VERSION 5.8 ;
BUSBITCHARS "[]" ;
DIVIDERCHAR "/" ;
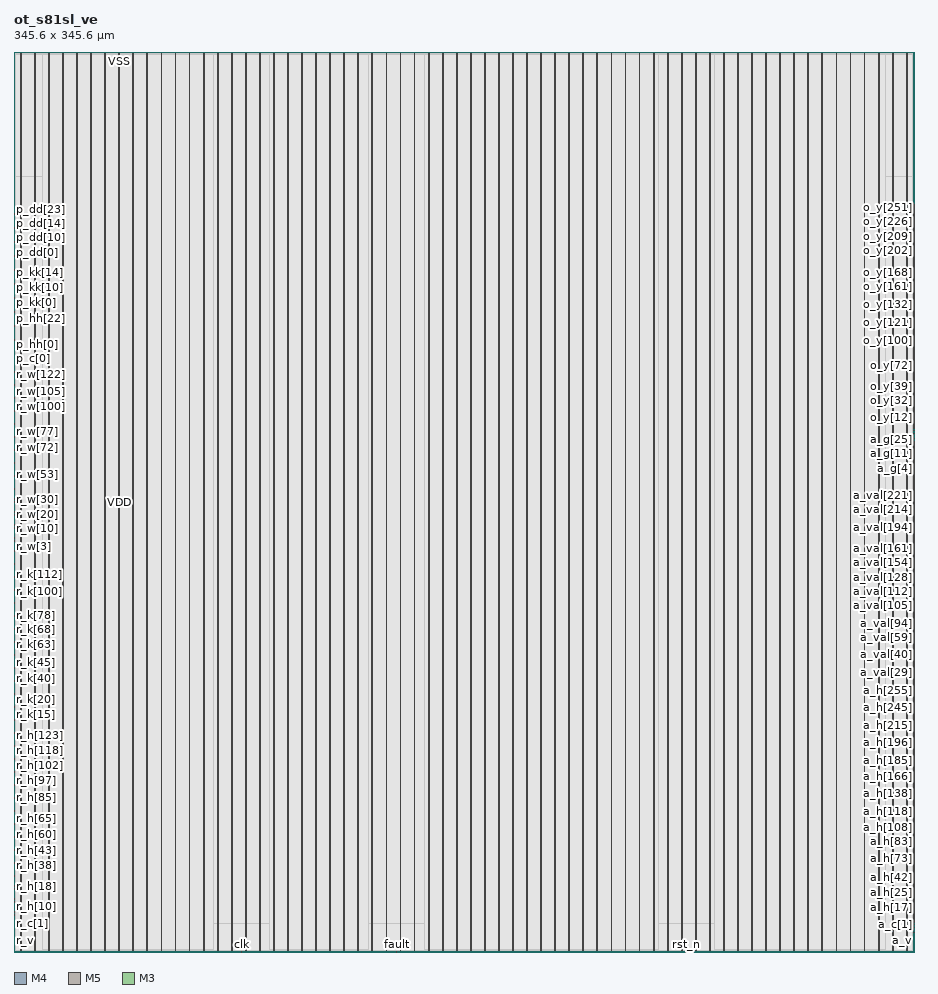
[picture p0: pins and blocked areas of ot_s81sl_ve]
MACRO ot_s81sl_ve
  CLASS BLOCK ;
  ORIGIN 0 0 ;
  FOREIGN ot_s81sl_ve 0 0 ;
  SIZE 345.6 BY 345.6 ;
  SYMMETRY X Y ;
  PIN r_v
    DIRECTION INPUT ;
    USE SIGNAL ;
    PORT
      LAYER M4 ;
        RECT 0.000 7.632 0.192 7.656 ;
    END
  END r_v
  PIN r_c[0]
    DIRECTION INPUT ;
    USE SIGNAL ;
    PORT
      LAYER M4 ;
        RECT 0.000 9.552 0.192 9.576 ;
    END
  END r_c[0]
  PIN r_c[1]
    DIRECTION INPUT ;
    USE SIGNAL ;
    PORT
      LAYER M4 ;
        RECT 0.000 10.992 0.192 11.016 ;
    END
  END r_c[1]
  PIN r_h[0]
    DIRECTION INPUT ;
    USE SIGNAL ;
    PORT
      LAYER M4 ;
        RECT 0.000 12.000 0.192 12.024 ;
    END
  END r_h[0]
  PIN r_h[1]
    DIRECTION INPUT ;
    USE SIGNAL ;
    PORT
      LAYER M4 ;
        RECT 0.000 12.576 0.192 12.600 ;
    END
  END r_h[1]
  PIN r_h[2]
    DIRECTION INPUT ;
    USE SIGNAL ;
    PORT
      LAYER M4 ;
        RECT 0.000 13.104 0.192 13.128 ;
    END
  END r_h[2]
  PIN r_h[3]
    DIRECTION INPUT ;
    USE SIGNAL ;
    PORT
      LAYER M4 ;
        RECT 0.000 13.680 0.192 13.704 ;
    END
  END r_h[3]
  PIN r_h[4]
    DIRECTION INPUT ;
    USE SIGNAL ;
    PORT
      LAYER M4 ;
        RECT 0.000 14.208 0.192 14.232 ;
    END
  END r_h[4]
  PIN r_h[5]
    DIRECTION INPUT ;
    USE SIGNAL ;
    PORT
      LAYER M4 ;
        RECT 0.000 14.784 0.192 14.808 ;
    END
  END r_h[5]
  PIN r_h[6]
    DIRECTION INPUT ;
    USE SIGNAL ;
    PORT
      LAYER M4 ;
        RECT 0.000 15.360 0.192 15.384 ;
    END
  END r_h[6]
  PIN r_h[7]
    DIRECTION INPUT ;
    USE SIGNAL ;
    PORT
      LAYER M4 ;
        RECT 0.000 15.888 0.192 15.912 ;
    END
  END r_h[7]
  PIN r_h[8]
    DIRECTION INPUT ;
    USE SIGNAL ;
    PORT
      LAYER M4 ;
        RECT 0.000 16.464 0.192 16.488 ;
    END
  END r_h[8]
  PIN r_h[9]
    DIRECTION INPUT ;
    USE SIGNAL ;
    PORT
      LAYER M4 ;
        RECT 0.000 16.992 0.192 17.016 ;
    END
  END r_h[9]
  PIN r_h[10]
    DIRECTION INPUT ;
    USE SIGNAL ;
    PORT
      LAYER M4 ;
        RECT 0.000 17.568 0.192 17.592 ;
    END
  END r_h[10]
  PIN r_h[11]
    DIRECTION INPUT ;
    USE SIGNAL ;
    PORT
      LAYER M4 ;
        RECT 0.000 18.096 0.192 18.120 ;
    END
  END r_h[11]
  PIN r_h[12]
    DIRECTION INPUT ;
    USE SIGNAL ;
    PORT
      LAYER M4 ;
        RECT 0.000 18.672 0.192 18.696 ;
    END
  END r_h[12]
  PIN r_h[13]
    DIRECTION INPUT ;
    USE SIGNAL ;
    PORT
      LAYER M4 ;
        RECT 0.000 19.200 0.192 19.224 ;
    END
  END r_h[13]
  PIN r_h[14]
    DIRECTION INPUT ;
    USE SIGNAL ;
    PORT
      LAYER M4 ;
        RECT 0.000 19.776 0.192 19.800 ;
    END
  END r_h[14]
  PIN r_h[15]
    DIRECTION INPUT ;
    USE SIGNAL ;
    PORT
      LAYER M4 ;
        RECT 0.000 20.352 0.192 20.376 ;
    END
  END r_h[15]
  PIN r_h[16]
    DIRECTION INPUT ;
    USE SIGNAL ;
    PORT
      LAYER M4 ;
        RECT 0.000 20.880 0.192 20.904 ;
    END
  END r_h[16]
  PIN r_h[17]
    DIRECTION INPUT ;
    USE SIGNAL ;
    PORT
      LAYER M4 ;
        RECT 0.000 21.456 0.192 21.480 ;
    END
  END r_h[17]
  PIN r_h[18]
    DIRECTION INPUT ;
    USE SIGNAL ;
    PORT
      LAYER M4 ;
        RECT 0.000 21.984 0.192 22.008 ;
    END
  END r_h[18]
  PIN r_h[19]
    DIRECTION INPUT ;
    USE SIGNAL ;
    PORT
      LAYER M4 ;
        RECT 0.000 22.560 0.192 22.584 ;
    END
  END r_h[19]
  PIN r_h[20]
    DIRECTION INPUT ;
    USE SIGNAL ;
    PORT
      LAYER M4 ;
        RECT 0.000 23.088 0.192 23.112 ;
    END
  END r_h[20]
  PIN r_h[21]
    DIRECTION INPUT ;
    USE SIGNAL ;
    PORT
      LAYER M4 ;
        RECT 0.000 23.664 0.192 23.688 ;
    END
  END r_h[21]
  PIN r_h[22]
    DIRECTION INPUT ;
    USE SIGNAL ;
    PORT
      LAYER M4 ;
        RECT 0.000 24.192 0.192 24.216 ;
    END
  END r_h[22]
  PIN r_h[23]
    DIRECTION INPUT ;
    USE SIGNAL ;
    PORT
      LAYER M4 ;
        RECT 0.000 24.768 0.192 24.792 ;
    END
  END r_h[23]
  PIN r_h[24]
    DIRECTION INPUT ;
    USE SIGNAL ;
    PORT
      LAYER M4 ;
        RECT 0.000 25.344 0.192 25.368 ;
    END
  END r_h[24]
  PIN r_h[25]
    DIRECTION INPUT ;
    USE SIGNAL ;
    PORT
      LAYER M4 ;
        RECT 0.000 25.872 0.192 25.896 ;
    END
  END r_h[25]
  PIN r_h[26]
    DIRECTION INPUT ;
    USE SIGNAL ;
    PORT
      LAYER M4 ;
        RECT 0.000 26.448 0.192 26.472 ;
    END
  END r_h[26]
  PIN r_h[27]
    DIRECTION INPUT ;
    USE SIGNAL ;
    PORT
      LAYER M4 ;
        RECT 0.000 26.976 0.192 27.000 ;
    END
  END r_h[27]
  PIN r_h[28]
    DIRECTION INPUT ;
    USE SIGNAL ;
    PORT
      LAYER M4 ;
        RECT 0.000 27.552 0.192 27.576 ;
    END
  END r_h[28]
  PIN r_h[29]
    DIRECTION INPUT ;
    USE SIGNAL ;
    PORT
      LAYER M4 ;
        RECT 0.000 28.080 0.192 28.104 ;
    END
  END r_h[29]
  PIN r_h[30]
    DIRECTION INPUT ;
    USE SIGNAL ;
    PORT
      LAYER M4 ;
        RECT 0.000 28.656 0.192 28.680 ;
    END
  END r_h[30]
  PIN r_h[31]
    DIRECTION INPUT ;
    USE SIGNAL ;
    PORT
      LAYER M4 ;
        RECT 0.000 29.184 0.192 29.208 ;
    END
  END r_h[31]
  PIN r_h[32]
    DIRECTION INPUT ;
    USE SIGNAL ;
    PORT
      LAYER M4 ;
        RECT 0.000 29.760 0.192 29.784 ;
    END
  END r_h[32]
  PIN r_h[33]
    DIRECTION INPUT ;
    USE SIGNAL ;
    PORT
      LAYER M4 ;
        RECT 0.000 30.288 0.192 30.312 ;
    END
  END r_h[33]
  PIN r_h[34]
    DIRECTION INPUT ;
    USE SIGNAL ;
    PORT
      LAYER M4 ;
        RECT 0.000 30.864 0.192 30.888 ;
    END
  END r_h[34]
  PIN r_h[35]
    DIRECTION INPUT ;
    USE SIGNAL ;
    PORT
      LAYER M4 ;
        RECT 0.000 31.440 0.192 31.464 ;
    END
  END r_h[35]
  PIN r_h[36]
    DIRECTION INPUT ;
    USE SIGNAL ;
    PORT
      LAYER M4 ;
        RECT 0.000 31.968 0.192 31.992 ;
    END
  END r_h[36]
  PIN r_h[37]
    DIRECTION INPUT ;
    USE SIGNAL ;
    PORT
      LAYER M4 ;
        RECT 0.000 32.544 0.192 32.568 ;
    END
  END r_h[37]
  PIN r_h[38]
    DIRECTION INPUT ;
    USE SIGNAL ;
    PORT
      LAYER M4 ;
        RECT 0.000 33.072 0.192 33.096 ;
    END
  END r_h[38]
  PIN r_h[39]
    DIRECTION INPUT ;
    USE SIGNAL ;
    PORT
      LAYER M4 ;
        RECT 0.000 33.648 0.192 33.672 ;
    END
  END r_h[39]
  PIN r_h[40]
    DIRECTION INPUT ;
    USE SIGNAL ;
    PORT
      LAYER M4 ;
        RECT 0.000 34.176 0.192 34.200 ;
    END
  END r_h[40]
  PIN r_h[41]
    DIRECTION INPUT ;
    USE SIGNAL ;
    PORT
      LAYER M4 ;
        RECT 0.000 34.752 0.192 34.776 ;
    END
  END r_h[41]
  PIN r_h[42]
    DIRECTION INPUT ;
    USE SIGNAL ;
    PORT
      LAYER M4 ;
        RECT 0.000 35.280 0.192 35.304 ;
    END
  END r_h[42]
  PIN r_h[43]
    DIRECTION INPUT ;
    USE SIGNAL ;
    PORT
      LAYER M4 ;
        RECT 0.000 35.856 0.192 35.880 ;
    END
  END r_h[43]
  PIN r_h[44]
    DIRECTION INPUT ;
    USE SIGNAL ;
    PORT
      LAYER M4 ;
        RECT 0.000 36.432 0.192 36.456 ;
    END
  END r_h[44]
  PIN r_h[45]
    DIRECTION INPUT ;
    USE SIGNAL ;
    PORT
      LAYER M4 ;
        RECT 0.000 36.960 0.192 36.984 ;
    END
  END r_h[45]
  PIN r_h[46]
    DIRECTION INPUT ;
    USE SIGNAL ;
    PORT
      LAYER M4 ;
        RECT 0.000 37.536 0.192 37.560 ;
    END
  END r_h[46]
  PIN r_h[47]
    DIRECTION INPUT ;
    USE SIGNAL ;
    PORT
      LAYER M4 ;
        RECT 0.000 38.064 0.192 38.088 ;
    END
  END r_h[47]
  PIN r_h[48]
    DIRECTION INPUT ;
    USE SIGNAL ;
    PORT
      LAYER M4 ;
        RECT 0.000 38.640 0.192 38.664 ;
    END
  END r_h[48]
  PIN r_h[49]
    DIRECTION INPUT ;
    USE SIGNAL ;
    PORT
      LAYER M4 ;
        RECT 0.000 39.168 0.192 39.192 ;
    END
  END r_h[49]
  PIN r_h[50]
    DIRECTION INPUT ;
    USE SIGNAL ;
    PORT
      LAYER M4 ;
        RECT 0.000 39.744 0.192 39.768 ;
    END
  END r_h[50]
  PIN r_h[51]
    DIRECTION INPUT ;
    USE SIGNAL ;
    PORT
      LAYER M4 ;
        RECT 0.000 40.272 0.192 40.296 ;
    END
  END r_h[51]
  PIN r_h[52]
    DIRECTION INPUT ;
    USE SIGNAL ;
    PORT
      LAYER M4 ;
        RECT 0.000 40.848 0.192 40.872 ;
    END
  END r_h[52]
  PIN r_h[53]
    DIRECTION INPUT ;
    USE SIGNAL ;
    PORT
      LAYER M4 ;
        RECT 0.000 41.424 0.192 41.448 ;
    END
  END r_h[53]
  PIN r_h[54]
    DIRECTION INPUT ;
    USE SIGNAL ;
    PORT
      LAYER M4 ;
        RECT 0.000 41.952 0.192 41.976 ;
    END
  END r_h[54]
  PIN r_h[55]
    DIRECTION INPUT ;
    USE SIGNAL ;
    PORT
      LAYER M4 ;
        RECT 0.000 42.528 0.192 42.552 ;
    END
  END r_h[55]
  PIN r_h[56]
    DIRECTION INPUT ;
    USE SIGNAL ;
    PORT
      LAYER M4 ;
        RECT 0.000 43.056 0.192 43.080 ;
    END
  END r_h[56]
  PIN r_h[57]
    DIRECTION INPUT ;
    USE SIGNAL ;
    PORT
      LAYER M4 ;
        RECT 0.000 43.632 0.192 43.656 ;
    END
  END r_h[57]
  PIN r_h[58]
    DIRECTION INPUT ;
    USE SIGNAL ;
    PORT
      LAYER M4 ;
        RECT 0.000 44.160 0.192 44.184 ;
    END
  END r_h[58]
  PIN r_h[59]
    DIRECTION INPUT ;
    USE SIGNAL ;
    PORT
      LAYER M4 ;
        RECT 0.000 44.736 0.192 44.760 ;
    END
  END r_h[59]
  PIN r_h[60]
    DIRECTION INPUT ;
    USE SIGNAL ;
    PORT
      LAYER M4 ;
        RECT 0.000 45.264 0.192 45.288 ;
    END
  END r_h[60]
  PIN r_h[61]
    DIRECTION INPUT ;
    USE SIGNAL ;
    PORT
      LAYER M4 ;
        RECT 0.000 45.840 0.192 45.864 ;
    END
  END r_h[61]
  PIN r_h[62]
    DIRECTION INPUT ;
    USE SIGNAL ;
    PORT
      LAYER M4 ;
        RECT 0.000 46.416 0.192 46.440 ;
    END
  END r_h[62]
  PIN r_h[63]
    DIRECTION INPUT ;
    USE SIGNAL ;
    PORT
      LAYER M4 ;
        RECT 0.000 46.944 0.192 46.968 ;
    END
  END r_h[63]
  PIN r_h[64]
    DIRECTION INPUT ;
    USE SIGNAL ;
    PORT
      LAYER M4 ;
        RECT 0.000 47.520 0.192 47.544 ;
    END
  END r_h[64]
  PIN r_h[65]
    DIRECTION INPUT ;
    USE SIGNAL ;
    PORT
      LAYER M4 ;
        RECT 0.000 48.048 0.192 48.072 ;
    END
  END r_h[65]
  PIN r_h[66]
    DIRECTION INPUT ;
    USE SIGNAL ;
    PORT
      LAYER M4 ;
        RECT 0.000 48.624 0.192 48.648 ;
    END
  END r_h[66]
  PIN r_h[67]
    DIRECTION INPUT ;
    USE SIGNAL ;
    PORT
      LAYER M4 ;
        RECT 0.000 49.152 0.192 49.176 ;
    END
  END r_h[67]
  PIN r_h[68]
    DIRECTION INPUT ;
    USE SIGNAL ;
    PORT
      LAYER M4 ;
        RECT 0.000 49.728 0.192 49.752 ;
    END
  END r_h[68]
  PIN r_h[69]
    DIRECTION INPUT ;
    USE SIGNAL ;
    PORT
      LAYER M4 ;
        RECT 0.000 50.256 0.192 50.280 ;
    END
  END r_h[69]
  PIN r_h[70]
    DIRECTION INPUT ;
    USE SIGNAL ;
    PORT
      LAYER M4 ;
        RECT 0.000 50.832 0.192 50.856 ;
    END
  END r_h[70]
  PIN r_h[71]
    DIRECTION INPUT ;
    USE SIGNAL ;
    PORT
      LAYER M4 ;
        RECT 0.000 51.360 0.192 51.384 ;
    END
  END r_h[71]
  PIN r_h[72]
    DIRECTION INPUT ;
    USE SIGNAL ;
    PORT
      LAYER M4 ;
        RECT 0.000 51.936 0.192 51.960 ;
    END
  END r_h[72]
  PIN r_h[73]
    DIRECTION INPUT ;
    USE SIGNAL ;
    PORT
      LAYER M4 ;
        RECT 0.000 52.512 0.192 52.536 ;
    END
  END r_h[73]
  PIN r_h[74]
    DIRECTION INPUT ;
    USE SIGNAL ;
    PORT
      LAYER M4 ;
        RECT 0.000 53.040 0.192 53.064 ;
    END
  END r_h[74]
  PIN r_h[75]
    DIRECTION INPUT ;
    USE SIGNAL ;
    PORT
      LAYER M4 ;
        RECT 0.000 53.616 0.192 53.640 ;
    END
  END r_h[75]
  PIN r_h[76]
    DIRECTION INPUT ;
    USE SIGNAL ;
    PORT
      LAYER M4 ;
        RECT 0.000 54.144 0.192 54.168 ;
    END
  END r_h[76]
  PIN r_h[77]
    DIRECTION INPUT ;
    USE SIGNAL ;
    PORT
      LAYER M4 ;
        RECT 0.000 54.720 0.192 54.744 ;
    END
  END r_h[77]
  PIN r_h[78]
    DIRECTION INPUT ;
    USE SIGNAL ;
    PORT
      LAYER M4 ;
        RECT 0.000 55.248 0.192 55.272 ;
    END
  END r_h[78]
  PIN r_h[79]
    DIRECTION INPUT ;
    USE SIGNAL ;
    PORT
      LAYER M4 ;
        RECT 0.000 55.824 0.192 55.848 ;
    END
  END r_h[79]
  PIN r_h[80]
    DIRECTION INPUT ;
    USE SIGNAL ;
    PORT
      LAYER M4 ;
        RECT 0.000 56.352 0.192 56.376 ;
    END
  END r_h[80]
  PIN r_h[81]
    DIRECTION INPUT ;
    USE SIGNAL ;
    PORT
      LAYER M4 ;
        RECT 0.000 56.928 0.192 56.952 ;
    END
  END r_h[81]
  PIN r_h[82]
    DIRECTION INPUT ;
    USE SIGNAL ;
    PORT
      LAYER M4 ;
        RECT 0.000 57.504 0.192 57.528 ;
    END
  END r_h[82]
  PIN r_h[83]
    DIRECTION INPUT ;
    USE SIGNAL ;
    PORT
      LAYER M4 ;
        RECT 0.000 58.032 0.192 58.056 ;
    END
  END r_h[83]
  PIN r_h[84]
    DIRECTION INPUT ;
    USE SIGNAL ;
    PORT
      LAYER M4 ;
        RECT 0.000 58.608 0.192 58.632 ;
    END
  END r_h[84]
  PIN r_h[85]
    DIRECTION INPUT ;
    USE SIGNAL ;
    PORT
      LAYER M4 ;
        RECT 0.000 59.136 0.192 59.160 ;
    END
  END r_h[85]
  PIN r_h[86]
    DIRECTION INPUT ;
    USE SIGNAL ;
    PORT
      LAYER M4 ;
        RECT 0.000 59.712 0.192 59.736 ;
    END
  END r_h[86]
  PIN r_h[87]
    DIRECTION INPUT ;
    USE SIGNAL ;
    PORT
      LAYER M4 ;
        RECT 0.000 60.240 0.192 60.264 ;
    END
  END r_h[87]
  PIN r_h[88]
    DIRECTION INPUT ;
    USE SIGNAL ;
    PORT
      LAYER M4 ;
        RECT 0.000 60.816 0.192 60.840 ;
    END
  END r_h[88]
  PIN r_h[89]
    DIRECTION INPUT ;
    USE SIGNAL ;
    PORT
      LAYER M4 ;
        RECT 0.000 61.344 0.192 61.368 ;
    END
  END r_h[89]
  PIN r_h[90]
    DIRECTION INPUT ;
    USE SIGNAL ;
    PORT
      LAYER M4 ;
        RECT 0.000 61.920 0.192 61.944 ;
    END
  END r_h[90]
  PIN r_h[91]
    DIRECTION INPUT ;
    USE SIGNAL ;
    PORT
      LAYER M4 ;
        RECT 0.000 62.496 0.192 62.520 ;
    END
  END r_h[91]
  PIN r_h[92]
    DIRECTION INPUT ;
    USE SIGNAL ;
    PORT
      LAYER M4 ;
        RECT 0.000 63.024 0.192 63.048 ;
    END
  END r_h[92]
  PIN r_h[93]
    DIRECTION INPUT ;
    USE SIGNAL ;
    PORT
      LAYER M4 ;
        RECT 0.000 63.600 0.192 63.624 ;
    END
  END r_h[93]
  PIN r_h[94]
    DIRECTION INPUT ;
    USE SIGNAL ;
    PORT
      LAYER M4 ;
        RECT 0.000 64.128 0.192 64.152 ;
    END
  END r_h[94]
  PIN r_h[95]
    DIRECTION INPUT ;
    USE SIGNAL ;
    PORT
      LAYER M4 ;
        RECT 0.000 64.704 0.192 64.728 ;
    END
  END r_h[95]
  PIN r_h[96]
    DIRECTION INPUT ;
    USE SIGNAL ;
    PORT
      LAYER M4 ;
        RECT 0.000 65.232 0.192 65.256 ;
    END
  END r_h[96]
  PIN r_h[97]
    DIRECTION INPUT ;
    USE SIGNAL ;
    PORT
      LAYER M4 ;
        RECT 0.000 65.808 0.192 65.832 ;
    END
  END r_h[97]
  PIN r_h[98]
    DIRECTION INPUT ;
    USE SIGNAL ;
    PORT
      LAYER M4 ;
        RECT 0.000 66.336 0.192 66.360 ;
    END
  END r_h[98]
  PIN r_h[99]
    DIRECTION INPUT ;
    USE SIGNAL ;
    PORT
      LAYER M4 ;
        RECT 0.000 66.912 0.192 66.936 ;
    END
  END r_h[99]
  PIN r_h[100]
    DIRECTION INPUT ;
    USE SIGNAL ;
    PORT
      LAYER M4 ;
        RECT 0.000 67.440 0.192 67.464 ;
    END
  END r_h[100]
  PIN r_h[101]
    DIRECTION INPUT ;
    USE SIGNAL ;
    PORT
      LAYER M4 ;
        RECT 0.000 68.016 0.192 68.040 ;
    END
  END r_h[101]
  PIN r_h[102]
    DIRECTION INPUT ;
    USE SIGNAL ;
    PORT
      LAYER M4 ;
        RECT 0.000 68.592 0.192 68.616 ;
    END
  END r_h[102]
  PIN r_h[103]
    DIRECTION INPUT ;
    USE SIGNAL ;
    PORT
      LAYER M4 ;
        RECT 0.000 69.120 0.192 69.144 ;
    END
  END r_h[103]
  PIN r_h[104]
    DIRECTION INPUT ;
    USE SIGNAL ;
    PORT
      LAYER M4 ;
        RECT 0.000 69.696 0.192 69.720 ;
    END
  END r_h[104]
  PIN r_h[105]
    DIRECTION INPUT ;
    USE SIGNAL ;
    PORT
      LAYER M4 ;
        RECT 0.000 70.224 0.192 70.248 ;
    END
  END r_h[105]
  PIN r_h[106]
    DIRECTION INPUT ;
    USE SIGNAL ;
    PORT
      LAYER M4 ;
        RECT 0.000 70.800 0.192 70.824 ;
    END
  END r_h[106]
  PIN r_h[107]
    DIRECTION INPUT ;
    USE SIGNAL ;
    PORT
      LAYER M4 ;
        RECT 0.000 71.328 0.192 71.352 ;
    END
  END r_h[107]
  PIN r_h[108]
    DIRECTION INPUT ;
    USE SIGNAL ;
    PORT
      LAYER M4 ;
        RECT 0.000 71.904 0.192 71.928 ;
    END
  END r_h[108]
  PIN r_h[109]
    DIRECTION INPUT ;
    USE SIGNAL ;
    PORT
      LAYER M4 ;
        RECT 0.000 72.432 0.192 72.456 ;
    END
  END r_h[109]
  PIN r_h[110]
    DIRECTION INPUT ;
    USE SIGNAL ;
    PORT
      LAYER M4 ;
        RECT 0.000 73.008 0.192 73.032 ;
    END
  END r_h[110]
  PIN r_h[111]
    DIRECTION INPUT ;
    USE SIGNAL ;
    PORT
      LAYER M4 ;
        RECT 0.000 73.584 0.192 73.608 ;
    END
  END r_h[111]
  PIN r_h[112]
    DIRECTION INPUT ;
    USE SIGNAL ;
    PORT
      LAYER M4 ;
        RECT 0.000 74.112 0.192 74.136 ;
    END
  END r_h[112]
  PIN r_h[113]
    DIRECTION INPUT ;
    USE SIGNAL ;
    PORT
      LAYER M4 ;
        RECT 0.000 74.688 0.192 74.712 ;
    END
  END r_h[113]
  PIN r_h[114]
    DIRECTION INPUT ;
    USE SIGNAL ;
    PORT
      LAYER M4 ;
        RECT 0.000 75.216 0.192 75.240 ;
    END
  END r_h[114]
  PIN r_h[115]
    DIRECTION INPUT ;
    USE SIGNAL ;
    PORT
      LAYER M4 ;
        RECT 0.000 75.792 0.192 75.816 ;
    END
  END r_h[115]
  PIN r_h[116]
    DIRECTION INPUT ;
    USE SIGNAL ;
    PORT
      LAYER M4 ;
        RECT 0.000 76.320 0.192 76.344 ;
    END
  END r_h[116]
  PIN r_h[117]
    DIRECTION INPUT ;
    USE SIGNAL ;
    PORT
      LAYER M4 ;
        RECT 0.000 76.896 0.192 76.920 ;
    END
  END r_h[117]
  PIN r_h[118]
    DIRECTION INPUT ;
    USE SIGNAL ;
    PORT
      LAYER M4 ;
        RECT 0.000 77.424 0.192 77.448 ;
    END
  END r_h[118]
  PIN r_h[119]
    DIRECTION INPUT ;
    USE SIGNAL ;
    PORT
      LAYER M4 ;
        RECT 0.000 78.000 0.192 78.024 ;
    END
  END r_h[119]
  PIN r_h[120]
    DIRECTION INPUT ;
    USE SIGNAL ;
    PORT
      LAYER M4 ;
        RECT 0.000 78.576 0.192 78.600 ;
    END
  END r_h[120]
  PIN r_h[121]
    DIRECTION INPUT ;
    USE SIGNAL ;
    PORT
      LAYER M4 ;
        RECT 0.000 79.104 0.192 79.128 ;
    END
  END r_h[121]
  PIN r_h[122]
    DIRECTION INPUT ;
    USE SIGNAL ;
    PORT
      LAYER M4 ;
        RECT 0.000 79.680 0.192 79.704 ;
    END
  END r_h[122]
  PIN r_h[123]
    DIRECTION INPUT ;
    USE SIGNAL ;
    PORT
      LAYER M4 ;
        RECT 0.000 80.208 0.192 80.232 ;
    END
  END r_h[123]
  PIN r_h[124]
    DIRECTION INPUT ;
    USE SIGNAL ;
    PORT
      LAYER M4 ;
        RECT 0.000 80.784 0.192 80.808 ;
    END
  END r_h[124]
  PIN r_h[125]
    DIRECTION INPUT ;
    USE SIGNAL ;
    PORT
      LAYER M4 ;
        RECT 0.000 81.312 0.192 81.336 ;
    END
  END r_h[125]
  PIN r_h[126]
    DIRECTION INPUT ;
    USE SIGNAL ;
    PORT
      LAYER M4 ;
        RECT 0.000 81.888 0.192 81.912 ;
    END
  END r_h[126]
  PIN r_h[127]
    DIRECTION INPUT ;
    USE SIGNAL ;
    PORT
      LAYER M4 ;
        RECT 0.000 82.416 0.192 82.440 ;
    END
  END r_h[127]
  PIN r_k[0]
    DIRECTION INPUT ;
    USE SIGNAL ;
    PORT
      LAYER M4 ;
        RECT 0.000 82.992 0.192 83.016 ;
    END
  END r_k[0]
  PIN r_k[1]
    DIRECTION INPUT ;
    USE SIGNAL ;
    PORT
      LAYER M4 ;
        RECT 0.000 83.520 0.192 83.544 ;
    END
  END r_k[1]
  PIN r_k[2]
    DIRECTION INPUT ;
    USE SIGNAL ;
    PORT
      LAYER M4 ;
        RECT 0.000 84.096 0.192 84.120 ;
    END
  END r_k[2]
  PIN r_k[3]
    DIRECTION INPUT ;
    USE SIGNAL ;
    PORT
      LAYER M4 ;
        RECT 0.000 84.672 0.192 84.696 ;
    END
  END r_k[3]
  PIN r_k[4]
    DIRECTION INPUT ;
    USE SIGNAL ;
    PORT
      LAYER M4 ;
        RECT 0.000 85.200 0.192 85.224 ;
    END
  END r_k[4]
  PIN r_k[5]
    DIRECTION INPUT ;
    USE SIGNAL ;
    PORT
      LAYER M4 ;
        RECT 0.000 85.776 0.192 85.800 ;
    END
  END r_k[5]
  PIN r_k[6]
    DIRECTION INPUT ;
    USE SIGNAL ;
    PORT
      LAYER M4 ;
        RECT 0.000 86.304 0.192 86.328 ;
    END
  END r_k[6]
  PIN r_k[7]
    DIRECTION INPUT ;
    USE SIGNAL ;
    PORT
      LAYER M4 ;
        RECT 0.000 86.880 0.192 86.904 ;
    END
  END r_k[7]
  PIN r_k[8]
    DIRECTION INPUT ;
    USE SIGNAL ;
    PORT
      LAYER M4 ;
        RECT 0.000 87.408 0.192 87.432 ;
    END
  END r_k[8]
  PIN r_k[9]
    DIRECTION INPUT ;
    USE SIGNAL ;
    PORT
      LAYER M4 ;
        RECT 0.000 87.984 0.192 88.008 ;
    END
  END r_k[9]
  PIN r_k[10]
    DIRECTION INPUT ;
    USE SIGNAL ;
    PORT
      LAYER M4 ;
        RECT 0.000 88.512 0.192 88.536 ;
    END
  END r_k[10]
  PIN r_k[11]
    DIRECTION INPUT ;
    USE SIGNAL ;
    PORT
      LAYER M4 ;
        RECT 0.000 89.088 0.192 89.112 ;
    END
  END r_k[11]
  PIN r_k[12]
    DIRECTION INPUT ;
    USE SIGNAL ;
    PORT
      LAYER M4 ;
        RECT 0.000 89.664 0.192 89.688 ;
    END
  END r_k[12]
  PIN r_k[13]
    DIRECTION INPUT ;
    USE SIGNAL ;
    PORT
      LAYER M4 ;
        RECT 0.000 90.192 0.192 90.216 ;
    END
  END r_k[13]
  PIN r_k[14]
    DIRECTION INPUT ;
    USE SIGNAL ;
    PORT
      LAYER M4 ;
        RECT 0.000 90.768 0.192 90.792 ;
    END
  END r_k[14]
  PIN r_k[15]
    DIRECTION INPUT ;
    USE SIGNAL ;
    PORT
      LAYER M4 ;
        RECT 0.000 91.296 0.192 91.320 ;
    END
  END r_k[15]
  PIN r_k[16]
    DIRECTION INPUT ;
    USE SIGNAL ;
    PORT
      LAYER M4 ;
        RECT 0.000 91.872 0.192 91.896 ;
    END
  END r_k[16]
  PIN r_k[17]
    DIRECTION INPUT ;
    USE SIGNAL ;
    PORT
      LAYER M4 ;
        RECT 0.000 92.400 0.192 92.424 ;
    END
  END r_k[17]
  PIN r_k[18]
    DIRECTION INPUT ;
    USE SIGNAL ;
    PORT
      LAYER M4 ;
        RECT 0.000 92.976 0.192 93.000 ;
    END
  END r_k[18]
  PIN r_k[19]
    DIRECTION INPUT ;
    USE SIGNAL ;
    PORT
      LAYER M4 ;
        RECT 0.000 93.504 0.192 93.528 ;
    END
  END r_k[19]
  PIN r_k[20]
    DIRECTION INPUT ;
    USE SIGNAL ;
    PORT
      LAYER M4 ;
        RECT 0.000 94.080 0.192 94.104 ;
    END
  END r_k[20]
  PIN r_k[21]
    DIRECTION INPUT ;
    USE SIGNAL ;
    PORT
      LAYER M4 ;
        RECT 0.000 94.656 0.192 94.680 ;
    END
  END r_k[21]
  PIN r_k[22]
    DIRECTION INPUT ;
    USE SIGNAL ;
    PORT
      LAYER M4 ;
        RECT 0.000 95.184 0.192 95.208 ;
    END
  END r_k[22]
  PIN r_k[23]
    DIRECTION INPUT ;
    USE SIGNAL ;
    PORT
      LAYER M4 ;
        RECT 0.000 95.760 0.192 95.784 ;
    END
  END r_k[23]
  PIN r_k[24]
    DIRECTION INPUT ;
    USE SIGNAL ;
    PORT
      LAYER M4 ;
        RECT 0.000 96.288 0.192 96.312 ;
    END
  END r_k[24]
  PIN r_k[25]
    DIRECTION INPUT ;
    USE SIGNAL ;
    PORT
      LAYER M4 ;
        RECT 0.000 96.864 0.192 96.888 ;
    END
  END r_k[25]
  PIN r_k[26]
    DIRECTION INPUT ;
    USE SIGNAL ;
    PORT
      LAYER M4 ;
        RECT 0.000 97.392 0.192 97.416 ;
    END
  END r_k[26]
  PIN r_k[27]
    DIRECTION INPUT ;
    USE SIGNAL ;
    PORT
      LAYER M4 ;
        RECT 0.000 97.968 0.192 97.992 ;
    END
  END r_k[27]
  PIN r_k[28]
    DIRECTION INPUT ;
    USE SIGNAL ;
    PORT
      LAYER M4 ;
        RECT 0.000 98.496 0.192 98.520 ;
    END
  END r_k[28]
  PIN r_k[29]
    DIRECTION INPUT ;
    USE SIGNAL ;
    PORT
      LAYER M4 ;
        RECT 0.000 99.072 0.192 99.096 ;
    END
  END r_k[29]
  PIN r_k[30]
    DIRECTION INPUT ;
    USE SIGNAL ;
    PORT
      LAYER M4 ;
        RECT 0.000 99.648 0.192 99.672 ;
    END
  END r_k[30]
  PIN r_k[31]
    DIRECTION INPUT ;
    USE SIGNAL ;
    PORT
      LAYER M4 ;
        RECT 0.000 100.176 0.192 100.200 ;
    END
  END r_k[31]
  PIN r_k[32]
    DIRECTION INPUT ;
    USE SIGNAL ;
    PORT
      LAYER M4 ;
        RECT 0.000 100.752 0.192 100.776 ;
    END
  END r_k[32]
  PIN r_k[33]
    DIRECTION INPUT ;
    USE SIGNAL ;
    PORT
      LAYER M4 ;
        RECT 0.000 101.280 0.192 101.304 ;
    END
  END r_k[33]
  PIN r_k[34]
    DIRECTION INPUT ;
    USE SIGNAL ;
    PORT
      LAYER M4 ;
        RECT 0.000 101.856 0.192 101.880 ;
    END
  END r_k[34]
  PIN r_k[35]
    DIRECTION INPUT ;
    USE SIGNAL ;
    PORT
      LAYER M4 ;
        RECT 0.000 102.384 0.192 102.408 ;
    END
  END r_k[35]
  PIN r_k[36]
    DIRECTION INPUT ;
    USE SIGNAL ;
    PORT
      LAYER M4 ;
        RECT 0.000 102.960 0.192 102.984 ;
    END
  END r_k[36]
  PIN r_k[37]
    DIRECTION INPUT ;
    USE SIGNAL ;
    PORT
      LAYER M4 ;
        RECT 0.000 103.488 0.192 103.512 ;
    END
  END r_k[37]
  PIN r_k[38]
    DIRECTION INPUT ;
    USE SIGNAL ;
    PORT
      LAYER M4 ;
        RECT 0.000 104.064 0.192 104.088 ;
    END
  END r_k[38]
  PIN r_k[39]
    DIRECTION INPUT ;
    USE SIGNAL ;
    PORT
      LAYER M4 ;
        RECT 0.000 104.592 0.192 104.616 ;
    END
  END r_k[39]
  PIN r_k[40]
    DIRECTION INPUT ;
    USE SIGNAL ;
    PORT
      LAYER M4 ;
        RECT 0.000 105.168 0.192 105.192 ;
    END
  END r_k[40]
  PIN r_k[41]
    DIRECTION INPUT ;
    USE SIGNAL ;
    PORT
      LAYER M4 ;
        RECT 0.000 105.744 0.192 105.768 ;
    END
  END r_k[41]
  PIN r_k[42]
    DIRECTION INPUT ;
    USE SIGNAL ;
    PORT
      LAYER M4 ;
        RECT 0.000 106.272 0.192 106.296 ;
    END
  END r_k[42]
  PIN r_k[43]
    DIRECTION INPUT ;
    USE SIGNAL ;
    PORT
      LAYER M4 ;
        RECT 0.000 106.848 0.192 106.872 ;
    END
  END r_k[43]
  PIN r_k[44]
    DIRECTION INPUT ;
    USE SIGNAL ;
    PORT
      LAYER M4 ;
        RECT 0.000 107.376 0.192 107.400 ;
    END
  END r_k[44]
  PIN r_k[45]
    DIRECTION INPUT ;
    USE SIGNAL ;
    PORT
      LAYER M4 ;
        RECT 0.000 107.952 0.192 107.976 ;
    END
  END r_k[45]
  PIN r_k[46]
    DIRECTION INPUT ;
    USE SIGNAL ;
    PORT
      LAYER M4 ;
        RECT 0.000 108.480 0.192 108.504 ;
    END
  END r_k[46]
  PIN r_k[47]
    DIRECTION INPUT ;
    USE SIGNAL ;
    PORT
      LAYER M4 ;
        RECT 0.000 109.056 0.192 109.080 ;
    END
  END r_k[47]
  PIN r_k[48]
    DIRECTION INPUT ;
    USE SIGNAL ;
    PORT
      LAYER M4 ;
        RECT 0.000 109.584 0.192 109.608 ;
    END
  END r_k[48]
  PIN r_k[49]
    DIRECTION INPUT ;
    USE SIGNAL ;
    PORT
      LAYER M4 ;
        RECT 0.000 110.160 0.192 110.184 ;
    END
  END r_k[49]
  PIN r_k[50]
    DIRECTION INPUT ;
    USE SIGNAL ;
    PORT
      LAYER M4 ;
        RECT 0.000 110.736 0.192 110.760 ;
    END
  END r_k[50]
  PIN r_k[51]
    DIRECTION INPUT ;
    USE SIGNAL ;
    PORT
      LAYER M4 ;
        RECT 0.000 111.264 0.192 111.288 ;
    END
  END r_k[51]
  PIN r_k[52]
    DIRECTION INPUT ;
    USE SIGNAL ;
    PORT
      LAYER M4 ;
        RECT 0.000 111.840 0.192 111.864 ;
    END
  END r_k[52]
  PIN r_k[53]
    DIRECTION INPUT ;
    USE SIGNAL ;
    PORT
      LAYER M4 ;
        RECT 0.000 112.368 0.192 112.392 ;
    END
  END r_k[53]
  PIN r_k[54]
    DIRECTION INPUT ;
    USE SIGNAL ;
    PORT
      LAYER M4 ;
        RECT 0.000 112.944 0.192 112.968 ;
    END
  END r_k[54]
  PIN r_k[55]
    DIRECTION INPUT ;
    USE SIGNAL ;
    PORT
      LAYER M4 ;
        RECT 0.000 113.472 0.192 113.496 ;
    END
  END r_k[55]
  PIN r_k[56]
    DIRECTION INPUT ;
    USE SIGNAL ;
    PORT
      LAYER M4 ;
        RECT 0.000 114.048 0.192 114.072 ;
    END
  END r_k[56]
  PIN r_k[57]
    DIRECTION INPUT ;
    USE SIGNAL ;
    PORT
      LAYER M4 ;
        RECT 0.000 114.576 0.192 114.600 ;
    END
  END r_k[57]
  PIN r_k[58]
    DIRECTION INPUT ;
    USE SIGNAL ;
    PORT
      LAYER M4 ;
        RECT 0.000 115.152 0.192 115.176 ;
    END
  END r_k[58]
  PIN r_k[59]
    DIRECTION INPUT ;
    USE SIGNAL ;
    PORT
      LAYER M4 ;
        RECT 0.000 115.728 0.192 115.752 ;
    END
  END r_k[59]
  PIN r_k[60]
    DIRECTION INPUT ;
    USE SIGNAL ;
    PORT
      LAYER M4 ;
        RECT 0.000 116.256 0.192 116.280 ;
    END
  END r_k[60]
  PIN r_k[61]
    DIRECTION INPUT ;
    USE SIGNAL ;
    PORT
      LAYER M4 ;
        RECT 0.000 116.832 0.192 116.856 ;
    END
  END r_k[61]
  PIN r_k[62]
    DIRECTION INPUT ;
    USE SIGNAL ;
    PORT
      LAYER M4 ;
        RECT 0.000 117.360 0.192 117.384 ;
    END
  END r_k[62]
  PIN r_k[63]
    DIRECTION INPUT ;
    USE SIGNAL ;
    PORT
      LAYER M4 ;
        RECT 0.000 117.936 0.192 117.960 ;
    END
  END r_k[63]
  PIN r_k[64]
    DIRECTION INPUT ;
    USE SIGNAL ;
    PORT
      LAYER M4 ;
        RECT 0.000 118.464 0.192 118.488 ;
    END
  END r_k[64]
  PIN r_k[65]
    DIRECTION INPUT ;
    USE SIGNAL ;
    PORT
      LAYER M4 ;
        RECT 0.000 119.040 0.192 119.064 ;
    END
  END r_k[65]
  PIN r_k[66]
    DIRECTION INPUT ;
    USE SIGNAL ;
    PORT
      LAYER M4 ;
        RECT 0.000 119.568 0.192 119.592 ;
    END
  END r_k[66]
  PIN r_k[67]
    DIRECTION INPUT ;
    USE SIGNAL ;
    PORT
      LAYER M4 ;
        RECT 0.000 120.144 0.192 120.168 ;
    END
  END r_k[67]
  PIN r_k[68]
    DIRECTION INPUT ;
    USE SIGNAL ;
    PORT
      LAYER M4 ;
        RECT 0.000 120.672 0.192 120.696 ;
    END
  END r_k[68]
  PIN r_k[69]
    DIRECTION INPUT ;
    USE SIGNAL ;
    PORT
      LAYER M4 ;
        RECT 0.000 121.248 0.192 121.272 ;
    END
  END r_k[69]
  PIN r_k[70]
    DIRECTION INPUT ;
    USE SIGNAL ;
    PORT
      LAYER M4 ;
        RECT 0.000 121.824 0.192 121.848 ;
    END
  END r_k[70]
  PIN r_k[71]
    DIRECTION INPUT ;
    USE SIGNAL ;
    PORT
      LAYER M4 ;
        RECT 0.000 122.352 0.192 122.376 ;
    END
  END r_k[71]
  PIN r_k[72]
    DIRECTION INPUT ;
    USE SIGNAL ;
    PORT
      LAYER M4 ;
        RECT 0.000 122.928 0.192 122.952 ;
    END
  END r_k[72]
  PIN r_k[73]
    DIRECTION INPUT ;
    USE SIGNAL ;
    PORT
      LAYER M4 ;
        RECT 0.000 123.456 0.192 123.480 ;
    END
  END r_k[73]
  PIN r_k[74]
    DIRECTION INPUT ;
    USE SIGNAL ;
    PORT
      LAYER M4 ;
        RECT 0.000 124.032 0.192 124.056 ;
    END
  END r_k[74]
  PIN r_k[75]
    DIRECTION INPUT ;
    USE SIGNAL ;
    PORT
      LAYER M4 ;
        RECT 0.000 124.560 0.192 124.584 ;
    END
  END r_k[75]
  PIN r_k[76]
    DIRECTION INPUT ;
    USE SIGNAL ;
    PORT
      LAYER M4 ;
        RECT 0.000 125.136 0.192 125.160 ;
    END
  END r_k[76]
  PIN r_k[77]
    DIRECTION INPUT ;
    USE SIGNAL ;
    PORT
      LAYER M4 ;
        RECT 0.000 125.664 0.192 125.688 ;
    END
  END r_k[77]
  PIN r_k[78]
    DIRECTION INPUT ;
    USE SIGNAL ;
    PORT
      LAYER M4 ;
        RECT 0.000 126.240 0.192 126.264 ;
    END
  END r_k[78]
  PIN r_k[79]
    DIRECTION INPUT ;
    USE SIGNAL ;
    PORT
      LAYER M4 ;
        RECT 0.000 126.816 0.192 126.840 ;
    END
  END r_k[79]
  PIN r_k[80]
    DIRECTION INPUT ;
    USE SIGNAL ;
    PORT
      LAYER M4 ;
        RECT 0.000 127.344 0.192 127.368 ;
    END
  END r_k[80]
  PIN r_k[81]
    DIRECTION INPUT ;
    USE SIGNAL ;
    PORT
      LAYER M4 ;
        RECT 0.000 127.920 0.192 127.944 ;
    END
  END r_k[81]
  PIN r_k[82]
    DIRECTION INPUT ;
    USE SIGNAL ;
    PORT
      LAYER M4 ;
        RECT 0.000 128.448 0.192 128.472 ;
    END
  END r_k[82]
  PIN r_k[83]
    DIRECTION INPUT ;
    USE SIGNAL ;
    PORT
      LAYER M4 ;
        RECT 0.000 129.024 0.192 129.048 ;
    END
  END r_k[83]
  PIN r_k[84]
    DIRECTION INPUT ;
    USE SIGNAL ;
    PORT
      LAYER M4 ;
        RECT 0.000 129.552 0.192 129.576 ;
    END
  END r_k[84]
  PIN r_k[85]
    DIRECTION INPUT ;
    USE SIGNAL ;
    PORT
      LAYER M4 ;
        RECT 0.000 130.128 0.192 130.152 ;
    END
  END r_k[85]
  PIN r_k[86]
    DIRECTION INPUT ;
    USE SIGNAL ;
    PORT
      LAYER M4 ;
        RECT 0.000 130.656 0.192 130.680 ;
    END
  END r_k[86]
  PIN r_k[87]
    DIRECTION INPUT ;
    USE SIGNAL ;
    PORT
      LAYER M4 ;
        RECT 0.000 131.232 0.192 131.256 ;
    END
  END r_k[87]
  PIN r_k[88]
    DIRECTION INPUT ;
    USE SIGNAL ;
    PORT
      LAYER M4 ;
        RECT 0.000 131.808 0.192 131.832 ;
    END
  END r_k[88]
  PIN r_k[89]
    DIRECTION INPUT ;
    USE SIGNAL ;
    PORT
      LAYER M4 ;
        RECT 0.000 132.336 0.192 132.360 ;
    END
  END r_k[89]
  PIN r_k[90]
    DIRECTION INPUT ;
    USE SIGNAL ;
    PORT
      LAYER M4 ;
        RECT 0.000 132.912 0.192 132.936 ;
    END
  END r_k[90]
  PIN r_k[91]
    DIRECTION INPUT ;
    USE SIGNAL ;
    PORT
      LAYER M4 ;
        RECT 0.000 133.440 0.192 133.464 ;
    END
  END r_k[91]
  PIN r_k[92]
    DIRECTION INPUT ;
    USE SIGNAL ;
    PORT
      LAYER M4 ;
        RECT 0.000 134.016 0.192 134.040 ;
    END
  END r_k[92]
  PIN r_k[93]
    DIRECTION INPUT ;
    USE SIGNAL ;
    PORT
      LAYER M4 ;
        RECT 0.000 134.544 0.192 134.568 ;
    END
  END r_k[93]
  PIN r_k[94]
    DIRECTION INPUT ;
    USE SIGNAL ;
    PORT
      LAYER M4 ;
        RECT 0.000 135.120 0.192 135.144 ;
    END
  END r_k[94]
  PIN r_k[95]
    DIRECTION INPUT ;
    USE SIGNAL ;
    PORT
      LAYER M4 ;
        RECT 0.000 135.648 0.192 135.672 ;
    END
  END r_k[95]
  PIN r_k[96]
    DIRECTION INPUT ;
    USE SIGNAL ;
    PORT
      LAYER M4 ;
        RECT 0.000 136.224 0.192 136.248 ;
    END
  END r_k[96]
  PIN r_k[97]
    DIRECTION INPUT ;
    USE SIGNAL ;
    PORT
      LAYER M4 ;
        RECT 0.000 136.800 0.192 136.824 ;
    END
  END r_k[97]
  PIN r_k[98]
    DIRECTION INPUT ;
    USE SIGNAL ;
    PORT
      LAYER M4 ;
        RECT 0.000 137.328 0.192 137.352 ;
    END
  END r_k[98]
  PIN r_k[99]
    DIRECTION INPUT ;
    USE SIGNAL ;
    PORT
      LAYER M4 ;
        RECT 0.000 137.904 0.192 137.928 ;
    END
  END r_k[99]
  PIN r_k[100]
    DIRECTION INPUT ;
    USE SIGNAL ;
    PORT
      LAYER M4 ;
        RECT 0.000 138.432 0.192 138.456 ;
    END
  END r_k[100]
  PIN r_k[101]
    DIRECTION INPUT ;
    USE SIGNAL ;
    PORT
      LAYER M4 ;
        RECT 0.000 139.008 0.192 139.032 ;
    END
  END r_k[101]
  PIN r_k[102]
    DIRECTION INPUT ;
    USE SIGNAL ;
    PORT
      LAYER M4 ;
        RECT 0.000 139.536 0.192 139.560 ;
    END
  END r_k[102]
  PIN r_k[103]
    DIRECTION INPUT ;
    USE SIGNAL ;
    PORT
      LAYER M4 ;
        RECT 0.000 140.112 0.192 140.136 ;
    END
  END r_k[103]
  PIN r_k[104]
    DIRECTION INPUT ;
    USE SIGNAL ;
    PORT
      LAYER M4 ;
        RECT 0.000 140.640 0.192 140.664 ;
    END
  END r_k[104]
  PIN r_k[105]
    DIRECTION INPUT ;
    USE SIGNAL ;
    PORT
      LAYER M4 ;
        RECT 0.000 141.216 0.192 141.240 ;
    END
  END r_k[105]
  PIN r_k[106]
    DIRECTION INPUT ;
    USE SIGNAL ;
    PORT
      LAYER M4 ;
        RECT 0.000 141.744 0.192 141.768 ;
    END
  END r_k[106]
  PIN r_k[107]
    DIRECTION INPUT ;
    USE SIGNAL ;
    PORT
      LAYER M4 ;
        RECT 0.000 142.320 0.192 142.344 ;
    END
  END r_k[107]
  PIN r_k[108]
    DIRECTION INPUT ;
    USE SIGNAL ;
    PORT
      LAYER M4 ;
        RECT 0.000 142.896 0.192 142.920 ;
    END
  END r_k[108]
  PIN r_k[109]
    DIRECTION INPUT ;
    USE SIGNAL ;
    PORT
      LAYER M4 ;
        RECT 0.000 143.424 0.192 143.448 ;
    END
  END r_k[109]
  PIN r_k[110]
    DIRECTION INPUT ;
    USE SIGNAL ;
    PORT
      LAYER M4 ;
        RECT 0.000 144.000 0.192 144.024 ;
    END
  END r_k[110]
  PIN r_k[111]
    DIRECTION INPUT ;
    USE SIGNAL ;
    PORT
      LAYER M4 ;
        RECT 0.000 144.528 0.192 144.552 ;
    END
  END r_k[111]
  PIN r_k[112]
    DIRECTION INPUT ;
    USE SIGNAL ;
    PORT
      LAYER M4 ;
        RECT 0.000 145.104 0.192 145.128 ;
    END
  END r_k[112]
  PIN r_k[113]
    DIRECTION INPUT ;
    USE SIGNAL ;
    PORT
      LAYER M4 ;
        RECT 0.000 145.632 0.192 145.656 ;
    END
  END r_k[113]
  PIN r_k[114]
    DIRECTION INPUT ;
    USE SIGNAL ;
    PORT
      LAYER M4 ;
        RECT 0.000 146.208 0.192 146.232 ;
    END
  END r_k[114]
  PIN r_k[115]
    DIRECTION INPUT ;
    USE SIGNAL ;
    PORT
      LAYER M4 ;
        RECT 0.000 146.736 0.192 146.760 ;
    END
  END r_k[115]
  PIN r_k[116]
    DIRECTION INPUT ;
    USE SIGNAL ;
    PORT
      LAYER M4 ;
        RECT 0.000 147.312 0.192 147.336 ;
    END
  END r_k[116]
  PIN r_k[117]
    DIRECTION INPUT ;
    USE SIGNAL ;
    PORT
      LAYER M4 ;
        RECT 0.000 147.888 0.192 147.912 ;
    END
  END r_k[117]
  PIN r_k[118]
    DIRECTION INPUT ;
    USE SIGNAL ;
    PORT
      LAYER M4 ;
        RECT 0.000 148.416 0.192 148.440 ;
    END
  END r_k[118]
  PIN r_k[119]
    DIRECTION INPUT ;
    USE SIGNAL ;
    PORT
      LAYER M4 ;
        RECT 0.000 148.992 0.192 149.016 ;
    END
  END r_k[119]
  PIN r_k[120]
    DIRECTION INPUT ;
    USE SIGNAL ;
    PORT
      LAYER M4 ;
        RECT 0.000 149.520 0.192 149.544 ;
    END
  END r_k[120]
  PIN r_k[121]
    DIRECTION INPUT ;
    USE SIGNAL ;
    PORT
      LAYER M4 ;
        RECT 0.000 150.096 0.192 150.120 ;
    END
  END r_k[121]
  PIN r_k[122]
    DIRECTION INPUT ;
    USE SIGNAL ;
    PORT
      LAYER M4 ;
        RECT 0.000 150.624 0.192 150.648 ;
    END
  END r_k[122]
  PIN r_k[123]
    DIRECTION INPUT ;
    USE SIGNAL ;
    PORT
      LAYER M4 ;
        RECT 0.000 151.200 0.192 151.224 ;
    END
  END r_k[123]
  PIN r_k[124]
    DIRECTION INPUT ;
    USE SIGNAL ;
    PORT
      LAYER M4 ;
        RECT 0.000 151.728 0.192 151.752 ;
    END
  END r_k[124]
  PIN r_k[125]
    DIRECTION INPUT ;
    USE SIGNAL ;
    PORT
      LAYER M4 ;
        RECT 0.000 152.304 0.192 152.328 ;
    END
  END r_k[125]
  PIN r_k[126]
    DIRECTION INPUT ;
    USE SIGNAL ;
    PORT
      LAYER M4 ;
        RECT 0.000 152.880 0.192 152.904 ;
    END
  END r_k[126]
  PIN r_k[127]
    DIRECTION INPUT ;
    USE SIGNAL ;
    PORT
      LAYER M4 ;
        RECT 0.000 153.408 0.192 153.432 ;
    END
  END r_k[127]
  PIN r_w[0]
    DIRECTION INPUT ;
    USE SIGNAL ;
    PORT
      LAYER M4 ;
        RECT 0.000 153.984 0.192 154.008 ;
    END
  END r_w[0]
  PIN r_w[1]
    DIRECTION INPUT ;
    USE SIGNAL ;
    PORT
      LAYER M4 ;
        RECT 0.000 154.512 0.192 154.536 ;
    END
  END r_w[1]
  PIN r_w[2]
    DIRECTION INPUT ;
    USE SIGNAL ;
    PORT
      LAYER M4 ;
        RECT 0.000 155.088 0.192 155.112 ;
    END
  END r_w[2]
  PIN r_w[3]
    DIRECTION INPUT ;
    USE SIGNAL ;
    PORT
      LAYER M4 ;
        RECT 0.000 155.616 0.192 155.640 ;
    END
  END r_w[3]
  PIN r_w[4]
    DIRECTION INPUT ;
    USE SIGNAL ;
    PORT
      LAYER M4 ;
        RECT 0.000 156.192 0.192 156.216 ;
    END
  END r_w[4]
  PIN r_w[5]
    DIRECTION INPUT ;
    USE SIGNAL ;
    PORT
      LAYER M4 ;
        RECT 0.000 156.720 0.192 156.744 ;
    END
  END r_w[5]
  PIN r_w[6]
    DIRECTION INPUT ;
    USE SIGNAL ;
    PORT
      LAYER M4 ;
        RECT 0.000 157.296 0.192 157.320 ;
    END
  END r_w[6]
  PIN r_w[7]
    DIRECTION INPUT ;
    USE SIGNAL ;
    PORT
      LAYER M4 ;
        RECT 0.000 157.824 0.192 157.848 ;
    END
  END r_w[7]
  PIN r_w[8]
    DIRECTION INPUT ;
    USE SIGNAL ;
    PORT
      LAYER M4 ;
        RECT 0.000 158.400 0.192 158.424 ;
    END
  END r_w[8]
  PIN r_w[9]
    DIRECTION INPUT ;
    USE SIGNAL ;
    PORT
      LAYER M4 ;
        RECT 0.000 158.976 0.192 159.000 ;
    END
  END r_w[9]
  PIN r_w[10]
    DIRECTION INPUT ;
    USE SIGNAL ;
    PORT
      LAYER M4 ;
        RECT 0.000 159.504 0.192 159.528 ;
    END
  END r_w[10]
  PIN r_w[11]
    DIRECTION INPUT ;
    USE SIGNAL ;
    PORT
      LAYER M4 ;
        RECT 0.000 160.080 0.192 160.104 ;
    END
  END r_w[11]
  PIN r_w[12]
    DIRECTION INPUT ;
    USE SIGNAL ;
    PORT
      LAYER M4 ;
        RECT 0.000 160.608 0.192 160.632 ;
    END
  END r_w[12]
  PIN r_w[13]
    DIRECTION INPUT ;
    USE SIGNAL ;
    PORT
      LAYER M4 ;
        RECT 0.000 161.184 0.192 161.208 ;
    END
  END r_w[13]
  PIN r_w[14]
    DIRECTION INPUT ;
    USE SIGNAL ;
    PORT
      LAYER M4 ;
        RECT 0.000 161.712 0.192 161.736 ;
    END
  END r_w[14]
  PIN r_w[15]
    DIRECTION INPUT ;
    USE SIGNAL ;
    PORT
      LAYER M4 ;
        RECT 0.000 162.288 0.192 162.312 ;
    END
  END r_w[15]
  PIN r_w[16]
    DIRECTION INPUT ;
    USE SIGNAL ;
    PORT
      LAYER M4 ;
        RECT 0.000 162.816 0.192 162.840 ;
    END
  END r_w[16]
  PIN r_w[17]
    DIRECTION INPUT ;
    USE SIGNAL ;
    PORT
      LAYER M4 ;
        RECT 0.000 163.392 0.192 163.416 ;
    END
  END r_w[17]
  PIN r_w[18]
    DIRECTION INPUT ;
    USE SIGNAL ;
    PORT
      LAYER M4 ;
        RECT 0.000 163.968 0.192 163.992 ;
    END
  END r_w[18]
  PIN r_w[19]
    DIRECTION INPUT ;
    USE SIGNAL ;
    PORT
      LAYER M4 ;
        RECT 0.000 164.496 0.192 164.520 ;
    END
  END r_w[19]
  PIN r_w[20]
    DIRECTION INPUT ;
    USE SIGNAL ;
    PORT
      LAYER M4 ;
        RECT 0.000 165.072 0.192 165.096 ;
    END
  END r_w[20]
  PIN r_w[21]
    DIRECTION INPUT ;
    USE SIGNAL ;
    PORT
      LAYER M4 ;
        RECT 0.000 165.600 0.192 165.624 ;
    END
  END r_w[21]
  PIN r_w[22]
    DIRECTION INPUT ;
    USE SIGNAL ;
    PORT
      LAYER M4 ;
        RECT 0.000 166.176 0.192 166.200 ;
    END
  END r_w[22]
  PIN r_w[23]
    DIRECTION INPUT ;
    USE SIGNAL ;
    PORT
      LAYER M4 ;
        RECT 0.000 166.704 0.192 166.728 ;
    END
  END r_w[23]
  PIN r_w[24]
    DIRECTION INPUT ;
    USE SIGNAL ;
    PORT
      LAYER M4 ;
        RECT 0.000 167.280 0.192 167.304 ;
    END
  END r_w[24]
  PIN r_w[25]
    DIRECTION INPUT ;
    USE SIGNAL ;
    PORT
      LAYER M4 ;
        RECT 0.000 167.808 0.192 167.832 ;
    END
  END r_w[25]
  PIN r_w[26]
    DIRECTION INPUT ;
    USE SIGNAL ;
    PORT
      LAYER M4 ;
        RECT 0.000 168.384 0.192 168.408 ;
    END
  END r_w[26]
  PIN r_w[27]
    DIRECTION INPUT ;
    USE SIGNAL ;
    PORT
      LAYER M4 ;
        RECT 0.000 168.960 0.192 168.984 ;
    END
  END r_w[27]
  PIN r_w[28]
    DIRECTION INPUT ;
    USE SIGNAL ;
    PORT
      LAYER M4 ;
        RECT 0.000 169.488 0.192 169.512 ;
    END
  END r_w[28]
  PIN r_w[29]
    DIRECTION INPUT ;
    USE SIGNAL ;
    PORT
      LAYER M4 ;
        RECT 0.000 170.064 0.192 170.088 ;
    END
  END r_w[29]
  PIN r_w[30]
    DIRECTION INPUT ;
    USE SIGNAL ;
    PORT
      LAYER M4 ;
        RECT 0.000 170.592 0.192 170.616 ;
    END
  END r_w[30]
  PIN r_w[31]
    DIRECTION INPUT ;
    USE SIGNAL ;
    PORT
      LAYER M4 ;
        RECT 0.000 171.168 0.192 171.192 ;
    END
  END r_w[31]
  PIN r_w[32]
    DIRECTION INPUT ;
    USE SIGNAL ;
    PORT
      LAYER M4 ;
        RECT 0.000 171.696 0.192 171.720 ;
    END
  END r_w[32]
  PIN r_w[33]
    DIRECTION INPUT ;
    USE SIGNAL ;
    PORT
      LAYER M4 ;
        RECT 0.000 172.272 0.192 172.296 ;
    END
  END r_w[33]
  PIN r_w[34]
    DIRECTION INPUT ;
    USE SIGNAL ;
    PORT
      LAYER M4 ;
        RECT 0.000 172.800 0.192 172.824 ;
    END
  END r_w[34]
  PIN r_w[35]
    DIRECTION INPUT ;
    USE SIGNAL ;
    PORT
      LAYER M4 ;
        RECT 0.000 173.376 0.192 173.400 ;
    END
  END r_w[35]
  PIN r_w[36]
    DIRECTION INPUT ;
    USE SIGNAL ;
    PORT
      LAYER M4 ;
        RECT 0.000 173.952 0.192 173.976 ;
    END
  END r_w[36]
  PIN r_w[37]
    DIRECTION INPUT ;
    USE SIGNAL ;
    PORT
      LAYER M4 ;
        RECT 0.000 174.480 0.192 174.504 ;
    END
  END r_w[37]
  PIN r_w[38]
    DIRECTION INPUT ;
    USE SIGNAL ;
    PORT
      LAYER M4 ;
        RECT 0.000 175.056 0.192 175.080 ;
    END
  END r_w[38]
  PIN r_w[39]
    DIRECTION INPUT ;
    USE SIGNAL ;
    PORT
      LAYER M4 ;
        RECT 0.000 175.584 0.192 175.608 ;
    END
  END r_w[39]
  PIN r_w[40]
    DIRECTION INPUT ;
    USE SIGNAL ;
    PORT
      LAYER M4 ;
        RECT 0.000 176.160 0.192 176.184 ;
    END
  END r_w[40]
  PIN r_w[41]
    DIRECTION INPUT ;
    USE SIGNAL ;
    PORT
      LAYER M4 ;
        RECT 0.000 176.688 0.192 176.712 ;
    END
  END r_w[41]
  PIN r_w[42]
    DIRECTION INPUT ;
    USE SIGNAL ;
    PORT
      LAYER M4 ;
        RECT 0.000 177.264 0.192 177.288 ;
    END
  END r_w[42]
  PIN r_w[43]
    DIRECTION INPUT ;
    USE SIGNAL ;
    PORT
      LAYER M4 ;
        RECT 0.000 177.792 0.192 177.816 ;
    END
  END r_w[43]
  PIN r_w[44]
    DIRECTION INPUT ;
    USE SIGNAL ;
    PORT
      LAYER M4 ;
        RECT 0.000 178.368 0.192 178.392 ;
    END
  END r_w[44]
  PIN r_w[45]
    DIRECTION INPUT ;
    USE SIGNAL ;
    PORT
      LAYER M4 ;
        RECT 0.000 178.896 0.192 178.920 ;
    END
  END r_w[45]
  PIN r_w[46]
    DIRECTION INPUT ;
    USE SIGNAL ;
    PORT
      LAYER M4 ;
        RECT 0.000 179.472 0.192 179.496 ;
    END
  END r_w[46]
  PIN r_w[47]
    DIRECTION INPUT ;
    USE SIGNAL ;
    PORT
      LAYER M4 ;
        RECT 0.000 180.048 0.192 180.072 ;
    END
  END r_w[47]
  PIN r_w[48]
    DIRECTION INPUT ;
    USE SIGNAL ;
    PORT
      LAYER M4 ;
        RECT 0.000 180.576 0.192 180.600 ;
    END
  END r_w[48]
  PIN r_w[49]
    DIRECTION INPUT ;
    USE SIGNAL ;
    PORT
      LAYER M4 ;
        RECT 0.000 181.152 0.192 181.176 ;
    END
  END r_w[49]
  PIN r_w[50]
    DIRECTION INPUT ;
    USE SIGNAL ;
    PORT
      LAYER M4 ;
        RECT 0.000 181.680 0.192 181.704 ;
    END
  END r_w[50]
  PIN r_w[51]
    DIRECTION INPUT ;
    USE SIGNAL ;
    PORT
      LAYER M4 ;
        RECT 0.000 182.256 0.192 182.280 ;
    END
  END r_w[51]
  PIN r_w[52]
    DIRECTION INPUT ;
    USE SIGNAL ;
    PORT
      LAYER M4 ;
        RECT 0.000 182.784 0.192 182.808 ;
    END
  END r_w[52]
  PIN r_w[53]
    DIRECTION INPUT ;
    USE SIGNAL ;
    PORT
      LAYER M4 ;
        RECT 0.000 183.360 0.192 183.384 ;
    END
  END r_w[53]
  PIN r_w[54]
    DIRECTION INPUT ;
    USE SIGNAL ;
    PORT
      LAYER M4 ;
        RECT 0.000 183.888 0.192 183.912 ;
    END
  END r_w[54]
  PIN r_w[55]
    DIRECTION INPUT ;
    USE SIGNAL ;
    PORT
      LAYER M4 ;
        RECT 0.000 184.464 0.192 184.488 ;
    END
  END r_w[55]
  PIN r_w[56]
    DIRECTION INPUT ;
    USE SIGNAL ;
    PORT
      LAYER M4 ;
        RECT 0.000 185.040 0.192 185.064 ;
    END
  END r_w[56]
  PIN r_w[57]
    DIRECTION INPUT ;
    USE SIGNAL ;
    PORT
      LAYER M4 ;
        RECT 0.000 185.568 0.192 185.592 ;
    END
  END r_w[57]
  PIN r_w[58]
    DIRECTION INPUT ;
    USE SIGNAL ;
    PORT
      LAYER M4 ;
        RECT 0.000 186.144 0.192 186.168 ;
    END
  END r_w[58]
  PIN r_w[59]
    DIRECTION INPUT ;
    USE SIGNAL ;
    PORT
      LAYER M4 ;
        RECT 0.000 186.672 0.192 186.696 ;
    END
  END r_w[59]
  PIN r_w[60]
    DIRECTION INPUT ;
    USE SIGNAL ;
    PORT
      LAYER M4 ;
        RECT 0.000 187.248 0.192 187.272 ;
    END
  END r_w[60]
  PIN r_w[61]
    DIRECTION INPUT ;
    USE SIGNAL ;
    PORT
      LAYER M4 ;
        RECT 0.000 187.776 0.192 187.800 ;
    END
  END r_w[61]
  PIN r_w[62]
    DIRECTION INPUT ;
    USE SIGNAL ;
    PORT
      LAYER M4 ;
        RECT 0.000 188.352 0.192 188.376 ;
    END
  END r_w[62]
  PIN r_w[63]
    DIRECTION INPUT ;
    USE SIGNAL ;
    PORT
      LAYER M4 ;
        RECT 0.000 188.880 0.192 188.904 ;
    END
  END r_w[63]
  PIN r_w[64]
    DIRECTION INPUT ;
    USE SIGNAL ;
    PORT
      LAYER M4 ;
        RECT 0.000 189.456 0.192 189.480 ;
    END
  END r_w[64]
  PIN r_w[65]
    DIRECTION INPUT ;
    USE SIGNAL ;
    PORT
      LAYER M4 ;
        RECT 0.000 190.032 0.192 190.056 ;
    END
  END r_w[65]
  PIN r_w[66]
    DIRECTION INPUT ;
    USE SIGNAL ;
    PORT
      LAYER M4 ;
        RECT 0.000 190.560 0.192 190.584 ;
    END
  END r_w[66]
  PIN r_w[67]
    DIRECTION INPUT ;
    USE SIGNAL ;
    PORT
      LAYER M4 ;
        RECT 0.000 191.136 0.192 191.160 ;
    END
  END r_w[67]
  PIN r_w[68]
    DIRECTION INPUT ;
    USE SIGNAL ;
    PORT
      LAYER M4 ;
        RECT 0.000 191.664 0.192 191.688 ;
    END
  END r_w[68]
  PIN r_w[69]
    DIRECTION INPUT ;
    USE SIGNAL ;
    PORT
      LAYER M4 ;
        RECT 0.000 192.240 0.192 192.264 ;
    END
  END r_w[69]
  PIN r_w[70]
    DIRECTION INPUT ;
    USE SIGNAL ;
    PORT
      LAYER M4 ;
        RECT 0.000 192.768 0.192 192.792 ;
    END
  END r_w[70]
  PIN r_w[71]
    DIRECTION INPUT ;
    USE SIGNAL ;
    PORT
      LAYER M4 ;
        RECT 0.000 193.344 0.192 193.368 ;
    END
  END r_w[71]
  PIN r_w[72]
    DIRECTION INPUT ;
    USE SIGNAL ;
    PORT
      LAYER M4 ;
        RECT 0.000 193.872 0.192 193.896 ;
    END
  END r_w[72]
  PIN r_w[73]
    DIRECTION INPUT ;
    USE SIGNAL ;
    PORT
      LAYER M4 ;
        RECT 0.000 194.448 0.192 194.472 ;
    END
  END r_w[73]
  PIN r_w[74]
    DIRECTION INPUT ;
    USE SIGNAL ;
    PORT
      LAYER M4 ;
        RECT 0.000 194.976 0.192 195.000 ;
    END
  END r_w[74]
  PIN r_w[75]
    DIRECTION INPUT ;
    USE SIGNAL ;
    PORT
      LAYER M4 ;
        RECT 0.000 195.552 0.192 195.576 ;
    END
  END r_w[75]
  PIN r_w[76]
    DIRECTION INPUT ;
    USE SIGNAL ;
    PORT
      LAYER M4 ;
        RECT 0.000 196.128 0.192 196.152 ;
    END
  END r_w[76]
  PIN r_w[77]
    DIRECTION INPUT ;
    USE SIGNAL ;
    PORT
      LAYER M4 ;
        RECT 0.000 196.656 0.192 196.680 ;
    END
  END r_w[77]
  PIN r_w[78]
    DIRECTION INPUT ;
    USE SIGNAL ;
    PORT
      LAYER M4 ;
        RECT 0.000 197.232 0.192 197.256 ;
    END
  END r_w[78]
  PIN r_w[79]
    DIRECTION INPUT ;
    USE SIGNAL ;
    PORT
      LAYER M4 ;
        RECT 0.000 197.760 0.192 197.784 ;
    END
  END r_w[79]
  PIN r_w[80]
    DIRECTION INPUT ;
    USE SIGNAL ;
    PORT
      LAYER M4 ;
        RECT 0.000 198.336 0.192 198.360 ;
    END
  END r_w[80]
  PIN r_w[81]
    DIRECTION INPUT ;
    USE SIGNAL ;
    PORT
      LAYER M4 ;
        RECT 0.000 198.864 0.192 198.888 ;
    END
  END r_w[81]
  PIN r_w[82]
    DIRECTION INPUT ;
    USE SIGNAL ;
    PORT
      LAYER M4 ;
        RECT 0.000 199.440 0.192 199.464 ;
    END
  END r_w[82]
  PIN r_w[83]
    DIRECTION INPUT ;
    USE SIGNAL ;
    PORT
      LAYER M4 ;
        RECT 0.000 199.968 0.192 199.992 ;
    END
  END r_w[83]
  PIN r_w[84]
    DIRECTION INPUT ;
    USE SIGNAL ;
    PORT
      LAYER M4 ;
        RECT 0.000 200.544 0.192 200.568 ;
    END
  END r_w[84]
  PIN r_w[85]
    DIRECTION INPUT ;
    USE SIGNAL ;
    PORT
      LAYER M4 ;
        RECT 0.000 201.120 0.192 201.144 ;
    END
  END r_w[85]
  PIN r_w[86]
    DIRECTION INPUT ;
    USE SIGNAL ;
    PORT
      LAYER M4 ;
        RECT 0.000 201.648 0.192 201.672 ;
    END
  END r_w[86]
  PIN r_w[87]
    DIRECTION INPUT ;
    USE SIGNAL ;
    PORT
      LAYER M4 ;
        RECT 0.000 202.224 0.192 202.248 ;
    END
  END r_w[87]
  PIN r_w[88]
    DIRECTION INPUT ;
    USE SIGNAL ;
    PORT
      LAYER M4 ;
        RECT 0.000 202.752 0.192 202.776 ;
    END
  END r_w[88]
  PIN r_w[89]
    DIRECTION INPUT ;
    USE SIGNAL ;
    PORT
      LAYER M4 ;
        RECT 0.000 203.328 0.192 203.352 ;
    END
  END r_w[89]
  PIN r_w[90]
    DIRECTION INPUT ;
    USE SIGNAL ;
    PORT
      LAYER M4 ;
        RECT 0.000 203.856 0.192 203.880 ;
    END
  END r_w[90]
  PIN r_w[91]
    DIRECTION INPUT ;
    USE SIGNAL ;
    PORT
      LAYER M4 ;
        RECT 0.000 204.432 0.192 204.456 ;
    END
  END r_w[91]
  PIN r_w[92]
    DIRECTION INPUT ;
    USE SIGNAL ;
    PORT
      LAYER M4 ;
        RECT 0.000 204.960 0.192 204.984 ;
    END
  END r_w[92]
  PIN r_w[93]
    DIRECTION INPUT ;
    USE SIGNAL ;
    PORT
      LAYER M4 ;
        RECT 0.000 205.536 0.192 205.560 ;
    END
  END r_w[93]
  PIN r_w[94]
    DIRECTION INPUT ;
    USE SIGNAL ;
    PORT
      LAYER M4 ;
        RECT 0.000 206.112 0.192 206.136 ;
    END
  END r_w[94]
  PIN r_w[95]
    DIRECTION INPUT ;
    USE SIGNAL ;
    PORT
      LAYER M4 ;
        RECT 0.000 206.640 0.192 206.664 ;
    END
  END r_w[95]
  PIN r_w[96]
    DIRECTION INPUT ;
    USE SIGNAL ;
    PORT
      LAYER M4 ;
        RECT 0.000 207.216 0.192 207.240 ;
    END
  END r_w[96]
  PIN r_w[97]
    DIRECTION INPUT ;
    USE SIGNAL ;
    PORT
      LAYER M4 ;
        RECT 0.000 207.744 0.192 207.768 ;
    END
  END r_w[97]
  PIN r_w[98]
    DIRECTION INPUT ;
    USE SIGNAL ;
    PORT
      LAYER M4 ;
        RECT 0.000 208.320 0.192 208.344 ;
    END
  END r_w[98]
  PIN r_w[99]
    DIRECTION INPUT ;
    USE SIGNAL ;
    PORT
      LAYER M4 ;
        RECT 0.000 208.848 0.192 208.872 ;
    END
  END r_w[99]
  PIN r_w[100]
    DIRECTION INPUT ;
    USE SIGNAL ;
    PORT
      LAYER M4 ;
        RECT 0.000 209.424 0.192 209.448 ;
    END
  END r_w[100]
  PIN r_w[101]
    DIRECTION INPUT ;
    USE SIGNAL ;
    PORT
      LAYER M4 ;
        RECT 0.000 209.952 0.192 209.976 ;
    END
  END r_w[101]
  PIN r_w[102]
    DIRECTION INPUT ;
    USE SIGNAL ;
    PORT
      LAYER M4 ;
        RECT 0.000 210.528 0.192 210.552 ;
    END
  END r_w[102]
  PIN r_w[103]
    DIRECTION INPUT ;
    USE SIGNAL ;
    PORT
      LAYER M4 ;
        RECT 0.000 211.056 0.192 211.080 ;
    END
  END r_w[103]
  PIN r_w[104]
    DIRECTION INPUT ;
    USE SIGNAL ;
    PORT
      LAYER M4 ;
        RECT 0.000 211.632 0.192 211.656 ;
    END
  END r_w[104]
  PIN r_w[105]
    DIRECTION INPUT ;
    USE SIGNAL ;
    PORT
      LAYER M4 ;
        RECT 0.000 212.208 0.192 212.232 ;
    END
  END r_w[105]
  PIN r_w[106]
    DIRECTION INPUT ;
    USE SIGNAL ;
    PORT
      LAYER M4 ;
        RECT 0.000 212.736 0.192 212.760 ;
    END
  END r_w[106]
  PIN r_w[107]
    DIRECTION INPUT ;
    USE SIGNAL ;
    PORT
      LAYER M4 ;
        RECT 0.000 213.312 0.192 213.336 ;
    END
  END r_w[107]
  PIN r_w[108]
    DIRECTION INPUT ;
    USE SIGNAL ;
    PORT
      LAYER M4 ;
        RECT 0.000 213.840 0.192 213.864 ;
    END
  END r_w[108]
  PIN r_w[109]
    DIRECTION INPUT ;
    USE SIGNAL ;
    PORT
      LAYER M4 ;
        RECT 0.000 214.416 0.192 214.440 ;
    END
  END r_w[109]
  PIN r_w[110]
    DIRECTION INPUT ;
    USE SIGNAL ;
    PORT
      LAYER M4 ;
        RECT 0.000 214.944 0.192 214.968 ;
    END
  END r_w[110]
  PIN r_w[111]
    DIRECTION INPUT ;
    USE SIGNAL ;
    PORT
      LAYER M4 ;
        RECT 0.000 215.520 0.192 215.544 ;
    END
  END r_w[111]
  PIN r_w[112]
    DIRECTION INPUT ;
    USE SIGNAL ;
    PORT
      LAYER M4 ;
        RECT 0.000 216.048 0.192 216.072 ;
    END
  END r_w[112]
  PIN r_w[113]
    DIRECTION INPUT ;
    USE SIGNAL ;
    PORT
      LAYER M4 ;
        RECT 0.000 216.624 0.192 216.648 ;
    END
  END r_w[113]
  PIN r_w[114]
    DIRECTION INPUT ;
    USE SIGNAL ;
    PORT
      LAYER M4 ;
        RECT 0.000 217.200 0.192 217.224 ;
    END
  END r_w[114]
  PIN r_w[115]
    DIRECTION INPUT ;
    USE SIGNAL ;
    PORT
      LAYER M4 ;
        RECT 0.000 217.728 0.192 217.752 ;
    END
  END r_w[115]
  PIN r_w[116]
    DIRECTION INPUT ;
    USE SIGNAL ;
    PORT
      LAYER M4 ;
        RECT 0.000 218.304 0.192 218.328 ;
    END
  END r_w[116]
  PIN r_w[117]
    DIRECTION INPUT ;
    USE SIGNAL ;
    PORT
      LAYER M4 ;
        RECT 0.000 218.832 0.192 218.856 ;
    END
  END r_w[117]
  PIN r_w[118]
    DIRECTION INPUT ;
    USE SIGNAL ;
    PORT
      LAYER M4 ;
        RECT 0.000 219.408 0.192 219.432 ;
    END
  END r_w[118]
  PIN r_w[119]
    DIRECTION INPUT ;
    USE SIGNAL ;
    PORT
      LAYER M4 ;
        RECT 0.000 219.936 0.192 219.960 ;
    END
  END r_w[119]
  PIN r_w[120]
    DIRECTION INPUT ;
    USE SIGNAL ;
    PORT
      LAYER M4 ;
        RECT 0.000 220.512 0.192 220.536 ;
    END
  END r_w[120]
  PIN r_w[121]
    DIRECTION INPUT ;
    USE SIGNAL ;
    PORT
      LAYER M4 ;
        RECT 0.000 221.040 0.192 221.064 ;
    END
  END r_w[121]
  PIN r_w[122]
    DIRECTION INPUT ;
    USE SIGNAL ;
    PORT
      LAYER M4 ;
        RECT 0.000 221.616 0.192 221.640 ;
    END
  END r_w[122]
  PIN r_w[123]
    DIRECTION INPUT ;
    USE SIGNAL ;
    PORT
      LAYER M4 ;
        RECT 0.000 222.192 0.192 222.216 ;
    END
  END r_w[123]
  PIN r_w[124]
    DIRECTION INPUT ;
    USE SIGNAL ;
    PORT
      LAYER M4 ;
        RECT 0.000 222.720 0.192 222.744 ;
    END
  END r_w[124]
  PIN r_w[125]
    DIRECTION INPUT ;
    USE SIGNAL ;
    PORT
      LAYER M4 ;
        RECT 0.000 223.296 0.192 223.320 ;
    END
  END r_w[125]
  PIN r_w[126]
    DIRECTION INPUT ;
    USE SIGNAL ;
    PORT
      LAYER M4 ;
        RECT 0.000 223.824 0.192 223.848 ;
    END
  END r_w[126]
  PIN r_w[127]
    DIRECTION INPUT ;
    USE SIGNAL ;
    PORT
      LAYER M4 ;
        RECT 0.000 224.400 0.192 224.424 ;
    END
  END r_w[127]
  PIN p_v
    DIRECTION OUTPUT ;
    USE SIGNAL ;
    PORT
      LAYER M4 ;
        RECT 0.000 225.840 0.192 225.864 ;
    END
  END p_v
  PIN p_c[0]
    DIRECTION OUTPUT ;
    USE SIGNAL ;
    PORT
      LAYER M4 ;
        RECT 0.000 227.760 0.192 227.784 ;
    END
  END p_c[0]
  PIN p_c[1]
    DIRECTION OUTPUT ;
    USE SIGNAL ;
    PORT
      LAYER M4 ;
        RECT 0.000 229.200 0.192 229.224 ;
    END
  END p_c[1]
  PIN p_hh[0]
    DIRECTION OUTPUT ;
    USE SIGNAL ;
    PORT
      LAYER M4 ;
        RECT 0.000 230.208 0.192 230.232 ;
    END
  END p_hh[0]
  PIN p_hh[1]
    DIRECTION OUTPUT ;
    USE SIGNAL ;
    PORT
      LAYER M4 ;
        RECT 0.000 230.832 0.192 230.856 ;
    END
  END p_hh[1]
  PIN p_hh[2]
    DIRECTION OUTPUT ;
    USE SIGNAL ;
    PORT
      LAYER M4 ;
        RECT 0.000 231.408 0.192 231.432 ;
    END
  END p_hh[2]
  PIN p_hh[3]
    DIRECTION OUTPUT ;
    USE SIGNAL ;
    PORT
      LAYER M4 ;
        RECT 0.000 232.032 0.192 232.056 ;
    END
  END p_hh[3]
  PIN p_hh[4]
    DIRECTION OUTPUT ;
    USE SIGNAL ;
    PORT
      LAYER M4 ;
        RECT 0.000 232.608 0.192 232.632 ;
    END
  END p_hh[4]
  PIN p_hh[5]
    DIRECTION OUTPUT ;
    USE SIGNAL ;
    PORT
      LAYER M4 ;
        RECT 0.000 233.232 0.192 233.256 ;
    END
  END p_hh[5]
  PIN p_hh[6]
    DIRECTION OUTPUT ;
    USE SIGNAL ;
    PORT
      LAYER M4 ;
        RECT 0.000 233.808 0.192 233.832 ;
    END
  END p_hh[6]
  PIN p_hh[7]
    DIRECTION OUTPUT ;
    USE SIGNAL ;
    PORT
      LAYER M4 ;
        RECT 0.000 234.432 0.192 234.456 ;
    END
  END p_hh[7]
  PIN p_hh[8]
    DIRECTION OUTPUT ;
    USE SIGNAL ;
    PORT
      LAYER M4 ;
        RECT 0.000 235.008 0.192 235.032 ;
    END
  END p_hh[8]
  PIN p_hh[9]
    DIRECTION OUTPUT ;
    USE SIGNAL ;
    PORT
      LAYER M4 ;
        RECT 0.000 235.584 0.192 235.608 ;
    END
  END p_hh[9]
  PIN p_hh[10]
    DIRECTION OUTPUT ;
    USE SIGNAL ;
    PORT
      LAYER M4 ;
        RECT 0.000 236.208 0.192 236.232 ;
    END
  END p_hh[10]
  PIN p_hh[11]
    DIRECTION OUTPUT ;
    USE SIGNAL ;
    PORT
      LAYER M4 ;
        RECT 0.000 236.784 0.192 236.808 ;
    END
  END p_hh[11]
  PIN p_hh[12]
    DIRECTION OUTPUT ;
    USE SIGNAL ;
    PORT
      LAYER M4 ;
        RECT 0.000 237.408 0.192 237.432 ;
    END
  END p_hh[12]
  PIN p_hh[13]
    DIRECTION OUTPUT ;
    USE SIGNAL ;
    PORT
      LAYER M4 ;
        RECT 0.000 237.984 0.192 238.008 ;
    END
  END p_hh[13]
  PIN p_hh[14]
    DIRECTION OUTPUT ;
    USE SIGNAL ;
    PORT
      LAYER M4 ;
        RECT 0.000 238.608 0.192 238.632 ;
    END
  END p_hh[14]
  PIN p_hh[15]
    DIRECTION OUTPUT ;
    USE SIGNAL ;
    PORT
      LAYER M4 ;
        RECT 0.000 239.184 0.192 239.208 ;
    END
  END p_hh[15]
  PIN p_hh[16]
    DIRECTION OUTPUT ;
    USE SIGNAL ;
    PORT
      LAYER M4 ;
        RECT 0.000 239.808 0.192 239.832 ;
    END
  END p_hh[16]
  PIN p_hh[17]
    DIRECTION OUTPUT ;
    USE SIGNAL ;
    PORT
      LAYER M4 ;
        RECT 0.000 240.384 0.192 240.408 ;
    END
  END p_hh[17]
  PIN p_hh[18]
    DIRECTION OUTPUT ;
    USE SIGNAL ;
    PORT
      LAYER M4 ;
        RECT 0.000 240.960 0.192 240.984 ;
    END
  END p_hh[18]
  PIN p_hh[19]
    DIRECTION OUTPUT ;
    USE SIGNAL ;
    PORT
      LAYER M4 ;
        RECT 0.000 241.584 0.192 241.608 ;
    END
  END p_hh[19]
  PIN p_hh[20]
    DIRECTION OUTPUT ;
    USE SIGNAL ;
    PORT
      LAYER M4 ;
        RECT 0.000 242.160 0.192 242.184 ;
    END
  END p_hh[20]
  PIN p_hh[21]
    DIRECTION OUTPUT ;
    USE SIGNAL ;
    PORT
      LAYER M4 ;
        RECT 0.000 242.784 0.192 242.808 ;
    END
  END p_hh[21]
  PIN p_hh[22]
    DIRECTION OUTPUT ;
    USE SIGNAL ;
    PORT
      LAYER M4 ;
        RECT 0.000 243.360 0.192 243.384 ;
    END
  END p_hh[22]
  PIN p_hh[23]
    DIRECTION OUTPUT ;
    USE SIGNAL ;
    PORT
      LAYER M4 ;
        RECT 0.000 243.984 0.192 244.008 ;
    END
  END p_hh[23]
  PIN p_hh[24]
    DIRECTION OUTPUT ;
    USE SIGNAL ;
    PORT
      LAYER M4 ;
        RECT 0.000 244.560 0.192 244.584 ;
    END
  END p_hh[24]
  PIN p_hh[25]
    DIRECTION OUTPUT ;
    USE SIGNAL ;
    PORT
      LAYER M4 ;
        RECT 0.000 245.184 0.192 245.208 ;
    END
  END p_hh[25]
  PIN p_hh[26]
    DIRECTION OUTPUT ;
    USE SIGNAL ;
    PORT
      LAYER M4 ;
        RECT 0.000 245.760 0.192 245.784 ;
    END
  END p_hh[26]
  PIN p_hh[27]
    DIRECTION OUTPUT ;
    USE SIGNAL ;
    PORT
      LAYER M4 ;
        RECT 0.000 246.336 0.192 246.360 ;
    END
  END p_hh[27]
  PIN p_hh[28]
    DIRECTION OUTPUT ;
    USE SIGNAL ;
    PORT
      LAYER M4 ;
        RECT 0.000 246.960 0.192 246.984 ;
    END
  END p_hh[28]
  PIN p_hh[29]
    DIRECTION OUTPUT ;
    USE SIGNAL ;
    PORT
      LAYER M4 ;
        RECT 0.000 247.536 0.192 247.560 ;
    END
  END p_hh[29]
  PIN p_hh[30]
    DIRECTION OUTPUT ;
    USE SIGNAL ;
    PORT
      LAYER M4 ;
        RECT 0.000 248.160 0.192 248.184 ;
    END
  END p_hh[30]
  PIN p_hh[31]
    DIRECTION OUTPUT ;
    USE SIGNAL ;
    PORT
      LAYER M4 ;
        RECT 0.000 248.736 0.192 248.760 ;
    END
  END p_hh[31]
  PIN p_kk[0]
    DIRECTION OUTPUT ;
    USE SIGNAL ;
    PORT
      LAYER M4 ;
        RECT 0.000 249.360 0.192 249.384 ;
    END
  END p_kk[0]
  PIN p_kk[1]
    DIRECTION OUTPUT ;
    USE SIGNAL ;
    PORT
      LAYER M4 ;
        RECT 0.000 249.936 0.192 249.960 ;
    END
  END p_kk[1]
  PIN p_kk[2]
    DIRECTION OUTPUT ;
    USE SIGNAL ;
    PORT
      LAYER M4 ;
        RECT 0.000 250.560 0.192 250.584 ;
    END
  END p_kk[2]
  PIN p_kk[3]
    DIRECTION OUTPUT ;
    USE SIGNAL ;
    PORT
      LAYER M4 ;
        RECT 0.000 251.136 0.192 251.160 ;
    END
  END p_kk[3]
  PIN p_kk[4]
    DIRECTION OUTPUT ;
    USE SIGNAL ;
    PORT
      LAYER M4 ;
        RECT 0.000 251.712 0.192 251.736 ;
    END
  END p_kk[4]
  PIN p_kk[5]
    DIRECTION OUTPUT ;
    USE SIGNAL ;
    PORT
      LAYER M4 ;
        RECT 0.000 252.336 0.192 252.360 ;
    END
  END p_kk[5]
  PIN p_kk[6]
    DIRECTION OUTPUT ;
    USE SIGNAL ;
    PORT
      LAYER M4 ;
        RECT 0.000 252.912 0.192 252.936 ;
    END
  END p_kk[6]
  PIN p_kk[7]
    DIRECTION OUTPUT ;
    USE SIGNAL ;
    PORT
      LAYER M4 ;
        RECT 0.000 253.536 0.192 253.560 ;
    END
  END p_kk[7]
  PIN p_kk[8]
    DIRECTION OUTPUT ;
    USE SIGNAL ;
    PORT
      LAYER M4 ;
        RECT 0.000 254.112 0.192 254.136 ;
    END
  END p_kk[8]
  PIN p_kk[9]
    DIRECTION OUTPUT ;
    USE SIGNAL ;
    PORT
      LAYER M4 ;
        RECT 0.000 254.736 0.192 254.760 ;
    END
  END p_kk[9]
  PIN p_kk[10]
    DIRECTION OUTPUT ;
    USE SIGNAL ;
    PORT
      LAYER M4 ;
        RECT 0.000 255.312 0.192 255.336 ;
    END
  END p_kk[10]
  PIN p_kk[11]
    DIRECTION OUTPUT ;
    USE SIGNAL ;
    PORT
      LAYER M4 ;
        RECT 0.000 255.936 0.192 255.960 ;
    END
  END p_kk[11]
  PIN p_kk[12]
    DIRECTION OUTPUT ;
    USE SIGNAL ;
    PORT
      LAYER M4 ;
        RECT 0.000 256.512 0.192 256.536 ;
    END
  END p_kk[12]
  PIN p_kk[13]
    DIRECTION OUTPUT ;
    USE SIGNAL ;
    PORT
      LAYER M4 ;
        RECT 0.000 257.088 0.192 257.112 ;
    END
  END p_kk[13]
  PIN p_kk[14]
    DIRECTION OUTPUT ;
    USE SIGNAL ;
    PORT
      LAYER M4 ;
        RECT 0.000 257.712 0.192 257.736 ;
    END
  END p_kk[14]
  PIN p_kk[15]
    DIRECTION OUTPUT ;
    USE SIGNAL ;
    PORT
      LAYER M4 ;
        RECT 0.000 258.288 0.192 258.312 ;
    END
  END p_kk[15]
  PIN p_kk[16]
    DIRECTION OUTPUT ;
    USE SIGNAL ;
    PORT
      LAYER M4 ;
        RECT 0.000 258.912 0.192 258.936 ;
    END
  END p_kk[16]
  PIN p_kk[17]
    DIRECTION OUTPUT ;
    USE SIGNAL ;
    PORT
      LAYER M4 ;
        RECT 0.000 259.488 0.192 259.512 ;
    END
  END p_kk[17]
  PIN p_kk[18]
    DIRECTION OUTPUT ;
    USE SIGNAL ;
    PORT
      LAYER M4 ;
        RECT 0.000 260.112 0.192 260.136 ;
    END
  END p_kk[18]
  PIN p_kk[19]
    DIRECTION OUTPUT ;
    USE SIGNAL ;
    PORT
      LAYER M4 ;
        RECT 0.000 260.688 0.192 260.712 ;
    END
  END p_kk[19]
  PIN p_kk[20]
    DIRECTION OUTPUT ;
    USE SIGNAL ;
    PORT
      LAYER M4 ;
        RECT 0.000 261.264 0.192 261.288 ;
    END
  END p_kk[20]
  PIN p_kk[21]
    DIRECTION OUTPUT ;
    USE SIGNAL ;
    PORT
      LAYER M4 ;
        RECT 0.000 261.888 0.192 261.912 ;
    END
  END p_kk[21]
  PIN p_kk[22]
    DIRECTION OUTPUT ;
    USE SIGNAL ;
    PORT
      LAYER M4 ;
        RECT 0.000 262.464 0.192 262.488 ;
    END
  END p_kk[22]
  PIN p_kk[23]
    DIRECTION OUTPUT ;
    USE SIGNAL ;
    PORT
      LAYER M4 ;
        RECT 0.000 263.088 0.192 263.112 ;
    END
  END p_kk[23]
  PIN p_kk[24]
    DIRECTION OUTPUT ;
    USE SIGNAL ;
    PORT
      LAYER M4 ;
        RECT 0.000 263.664 0.192 263.688 ;
    END
  END p_kk[24]
  PIN p_kk[25]
    DIRECTION OUTPUT ;
    USE SIGNAL ;
    PORT
      LAYER M4 ;
        RECT 0.000 264.288 0.192 264.312 ;
    END
  END p_kk[25]
  PIN p_kk[26]
    DIRECTION OUTPUT ;
    USE SIGNAL ;
    PORT
      LAYER M4 ;
        RECT 0.000 264.864 0.192 264.888 ;
    END
  END p_kk[26]
  PIN p_kk[27]
    DIRECTION OUTPUT ;
    USE SIGNAL ;
    PORT
      LAYER M4 ;
        RECT 0.000 265.488 0.192 265.512 ;
    END
  END p_kk[27]
  PIN p_kk[28]
    DIRECTION OUTPUT ;
    USE SIGNAL ;
    PORT
      LAYER M4 ;
        RECT 0.000 266.064 0.192 266.088 ;
    END
  END p_kk[28]
  PIN p_kk[29]
    DIRECTION OUTPUT ;
    USE SIGNAL ;
    PORT
      LAYER M4 ;
        RECT 0.000 266.640 0.192 266.664 ;
    END
  END p_kk[29]
  PIN p_kk[30]
    DIRECTION OUTPUT ;
    USE SIGNAL ;
    PORT
      LAYER M4 ;
        RECT 0.000 267.264 0.192 267.288 ;
    END
  END p_kk[30]
  PIN p_kk[31]
    DIRECTION OUTPUT ;
    USE SIGNAL ;
    PORT
      LAYER M4 ;
        RECT 0.000 267.840 0.192 267.864 ;
    END
  END p_kk[31]
  PIN p_dd[0]
    DIRECTION OUTPUT ;
    USE SIGNAL ;
    PORT
      LAYER M4 ;
        RECT 0.000 268.464 0.192 268.488 ;
    END
  END p_dd[0]
  PIN p_dd[1]
    DIRECTION OUTPUT ;
    USE SIGNAL ;
    PORT
      LAYER M4 ;
        RECT 0.000 269.040 0.192 269.064 ;
    END
  END p_dd[1]
  PIN p_dd[2]
    DIRECTION OUTPUT ;
    USE SIGNAL ;
    PORT
      LAYER M4 ;
        RECT 0.000 269.664 0.192 269.688 ;
    END
  END p_dd[2]
  PIN p_dd[3]
    DIRECTION OUTPUT ;
    USE SIGNAL ;
    PORT
      LAYER M4 ;
        RECT 0.000 270.240 0.192 270.264 ;
    END
  END p_dd[3]
  PIN p_dd[4]
    DIRECTION OUTPUT ;
    USE SIGNAL ;
    PORT
      LAYER M4 ;
        RECT 0.000 270.864 0.192 270.888 ;
    END
  END p_dd[4]
  PIN p_dd[5]
    DIRECTION OUTPUT ;
    USE SIGNAL ;
    PORT
      LAYER M4 ;
        RECT 0.000 271.440 0.192 271.464 ;
    END
  END p_dd[5]
  PIN p_dd[6]
    DIRECTION OUTPUT ;
    USE SIGNAL ;
    PORT
      LAYER M4 ;
        RECT 0.000 272.016 0.192 272.040 ;
    END
  END p_dd[6]
  PIN p_dd[7]
    DIRECTION OUTPUT ;
    USE SIGNAL ;
    PORT
      LAYER M4 ;
        RECT 0.000 272.640 0.192 272.664 ;
    END
  END p_dd[7]
  PIN p_dd[8]
    DIRECTION OUTPUT ;
    USE SIGNAL ;
    PORT
      LAYER M4 ;
        RECT 0.000 273.216 0.192 273.240 ;
    END
  END p_dd[8]
  PIN p_dd[9]
    DIRECTION OUTPUT ;
    USE SIGNAL ;
    PORT
      LAYER M4 ;
        RECT 0.000 273.840 0.192 273.864 ;
    END
  END p_dd[9]
  PIN p_dd[10]
    DIRECTION OUTPUT ;
    USE SIGNAL ;
    PORT
      LAYER M4 ;
        RECT 0.000 274.416 0.192 274.440 ;
    END
  END p_dd[10]
  PIN p_dd[11]
    DIRECTION OUTPUT ;
    USE SIGNAL ;
    PORT
      LAYER M4 ;
        RECT 0.000 275.040 0.192 275.064 ;
    END
  END p_dd[11]
  PIN p_dd[12]
    DIRECTION OUTPUT ;
    USE SIGNAL ;
    PORT
      LAYER M4 ;
        RECT 0.000 275.616 0.192 275.640 ;
    END
  END p_dd[12]
  PIN p_dd[13]
    DIRECTION OUTPUT ;
    USE SIGNAL ;
    PORT
      LAYER M4 ;
        RECT 0.000 276.240 0.192 276.264 ;
    END
  END p_dd[13]
  PIN p_dd[14]
    DIRECTION OUTPUT ;
    USE SIGNAL ;
    PORT
      LAYER M4 ;
        RECT 0.000 276.816 0.192 276.840 ;
    END
  END p_dd[14]
  PIN p_dd[15]
    DIRECTION OUTPUT ;
    USE SIGNAL ;
    PORT
      LAYER M4 ;
        RECT 0.000 277.392 0.192 277.416 ;
    END
  END p_dd[15]
  PIN p_dd[16]
    DIRECTION OUTPUT ;
    USE SIGNAL ;
    PORT
      LAYER M4 ;
        RECT 0.000 278.016 0.192 278.040 ;
    END
  END p_dd[16]
  PIN p_dd[17]
    DIRECTION OUTPUT ;
    USE SIGNAL ;
    PORT
      LAYER M4 ;
        RECT 0.000 278.592 0.192 278.616 ;
    END
  END p_dd[17]
  PIN p_dd[18]
    DIRECTION OUTPUT ;
    USE SIGNAL ;
    PORT
      LAYER M4 ;
        RECT 0.000 279.216 0.192 279.240 ;
    END
  END p_dd[18]
  PIN p_dd[19]
    DIRECTION OUTPUT ;
    USE SIGNAL ;
    PORT
      LAYER M4 ;
        RECT 0.000 279.792 0.192 279.816 ;
    END
  END p_dd[19]
  PIN p_dd[20]
    DIRECTION OUTPUT ;
    USE SIGNAL ;
    PORT
      LAYER M4 ;
        RECT 0.000 280.416 0.192 280.440 ;
    END
  END p_dd[20]
  PIN p_dd[21]
    DIRECTION OUTPUT ;
    USE SIGNAL ;
    PORT
      LAYER M4 ;
        RECT 0.000 280.992 0.192 281.016 ;
    END
  END p_dd[21]
  PIN p_dd[22]
    DIRECTION OUTPUT ;
    USE SIGNAL ;
    PORT
      LAYER M4 ;
        RECT 0.000 281.616 0.192 281.640 ;
    END
  END p_dd[22]
  PIN p_dd[23]
    DIRECTION OUTPUT ;
    USE SIGNAL ;
    PORT
      LAYER M4 ;
        RECT 0.000 282.192 0.192 282.216 ;
    END
  END p_dd[23]
  PIN p_dd[24]
    DIRECTION OUTPUT ;
    USE SIGNAL ;
    PORT
      LAYER M4 ;
        RECT 0.000 282.768 0.192 282.792 ;
    END
  END p_dd[24]
  PIN p_dd[25]
    DIRECTION OUTPUT ;
    USE SIGNAL ;
    PORT
      LAYER M4 ;
        RECT 0.000 283.392 0.192 283.416 ;
    END
  END p_dd[25]
  PIN p_dd[26]
    DIRECTION OUTPUT ;
    USE SIGNAL ;
    PORT
      LAYER M4 ;
        RECT 0.000 283.968 0.192 283.992 ;
    END
  END p_dd[26]
  PIN p_dd[27]
    DIRECTION OUTPUT ;
    USE SIGNAL ;
    PORT
      LAYER M4 ;
        RECT 0.000 284.592 0.192 284.616 ;
    END
  END p_dd[27]
  PIN p_dd[28]
    DIRECTION OUTPUT ;
    USE SIGNAL ;
    PORT
      LAYER M4 ;
        RECT 0.000 285.168 0.192 285.192 ;
    END
  END p_dd[28]
  PIN p_dd[29]
    DIRECTION OUTPUT ;
    USE SIGNAL ;
    PORT
      LAYER M4 ;
        RECT 0.000 285.792 0.192 285.816 ;
    END
  END p_dd[29]
  PIN p_dd[30]
    DIRECTION OUTPUT ;
    USE SIGNAL ;
    PORT
      LAYER M4 ;
        RECT 0.000 286.368 0.192 286.392 ;
    END
  END p_dd[30]
  PIN p_dd[31]
    DIRECTION OUTPUT ;
    USE SIGNAL ;
    PORT
      LAYER M4 ;
        RECT 0.000 286.992 0.192 287.016 ;
    END
  END p_dd[31]
  PIN a_v
    DIRECTION INPUT ;
    USE SIGNAL ;
    PORT
      LAYER M4 ;
        RECT 345.408 7.536 345.600 7.560 ;
    END
  END a_v
  PIN a_c[0]
    DIRECTION INPUT ;
    USE SIGNAL ;
    PORT
      LAYER M4 ;
        RECT 345.408 9.264 345.600 9.288 ;
    END
  END a_c[0]
  PIN a_c[1]
    DIRECTION INPUT ;
    USE SIGNAL ;
    PORT
      LAYER M4 ;
        RECT 345.408 10.464 345.600 10.488 ;
    END
  END a_c[1]
  PIN a_h[0]
    DIRECTION INPUT ;
    USE SIGNAL ;
    PORT
      LAYER M4 ;
        RECT 345.408 11.280 345.600 11.304 ;
    END
  END a_h[0]
  PIN a_h[1]
    DIRECTION INPUT ;
    USE SIGNAL ;
    PORT
      LAYER M4 ;
        RECT 345.408 11.616 345.600 11.640 ;
    END
  END a_h[1]
  PIN a_h[2]
    DIRECTION INPUT ;
    USE SIGNAL ;
    PORT
      LAYER M4 ;
        RECT 345.408 11.952 345.600 11.976 ;
    END
  END a_h[2]
  PIN a_h[3]
    DIRECTION INPUT ;
    USE SIGNAL ;
    PORT
      LAYER M4 ;
        RECT 345.408 12.288 345.600 12.312 ;
    END
  END a_h[3]
  PIN a_h[4]
    DIRECTION INPUT ;
    USE SIGNAL ;
    PORT
      LAYER M4 ;
        RECT 345.408 12.624 345.600 12.648 ;
    END
  END a_h[4]
  PIN a_h[5]
    DIRECTION INPUT ;
    USE SIGNAL ;
    PORT
      LAYER M4 ;
        RECT 345.408 12.960 345.600 12.984 ;
    END
  END a_h[5]
  PIN a_h[6]
    DIRECTION INPUT ;
    USE SIGNAL ;
    PORT
      LAYER M4 ;
        RECT 345.408 13.296 345.600 13.320 ;
    END
  END a_h[6]
  PIN a_h[7]
    DIRECTION INPUT ;
    USE SIGNAL ;
    PORT
      LAYER M4 ;
        RECT 345.408 13.632 345.600 13.656 ;
    END
  END a_h[7]
  PIN a_h[8]
    DIRECTION INPUT ;
    USE SIGNAL ;
    PORT
      LAYER M4 ;
        RECT 345.408 13.968 345.600 13.992 ;
    END
  END a_h[8]
  PIN a_h[9]
    DIRECTION INPUT ;
    USE SIGNAL ;
    PORT
      LAYER M4 ;
        RECT 345.408 14.304 345.600 14.328 ;
    END
  END a_h[9]
  PIN a_h[10]
    DIRECTION INPUT ;
    USE SIGNAL ;
    PORT
      LAYER M4 ;
        RECT 345.408 14.640 345.600 14.664 ;
    END
  END a_h[10]
  PIN a_h[11]
    DIRECTION INPUT ;
    USE SIGNAL ;
    PORT
      LAYER M4 ;
        RECT 345.408 14.976 345.600 15.000 ;
    END
  END a_h[11]
  PIN a_h[12]
    DIRECTION INPUT ;
    USE SIGNAL ;
    PORT
      LAYER M4 ;
        RECT 345.408 15.312 345.600 15.336 ;
    END
  END a_h[12]
  PIN a_h[13]
    DIRECTION INPUT ;
    USE SIGNAL ;
    PORT
      LAYER M4 ;
        RECT 345.408 15.648 345.600 15.672 ;
    END
  END a_h[13]
  PIN a_h[14]
    DIRECTION INPUT ;
    USE SIGNAL ;
    PORT
      LAYER M4 ;
        RECT 345.408 15.984 345.600 16.008 ;
    END
  END a_h[14]
  PIN a_h[15]
    DIRECTION INPUT ;
    USE SIGNAL ;
    PORT
      LAYER M4 ;
        RECT 345.408 16.320 345.600 16.344 ;
    END
  END a_h[15]
  PIN a_h[16]
    DIRECTION INPUT ;
    USE SIGNAL ;
    PORT
      LAYER M4 ;
        RECT 345.408 16.656 345.600 16.680 ;
    END
  END a_h[16]
  PIN a_h[17]
    DIRECTION INPUT ;
    USE SIGNAL ;
    PORT
      LAYER M4 ;
        RECT 345.408 16.992 345.600 17.016 ;
    END
  END a_h[17]
  PIN a_h[18]
    DIRECTION INPUT ;
    USE SIGNAL ;
    PORT
      LAYER M4 ;
        RECT 345.408 17.328 345.600 17.352 ;
    END
  END a_h[18]
  PIN a_h[19]
    DIRECTION INPUT ;
    USE SIGNAL ;
    PORT
      LAYER M4 ;
        RECT 345.408 17.664 345.600 17.688 ;
    END
  END a_h[19]
  PIN a_h[20]
    DIRECTION INPUT ;
    USE SIGNAL ;
    PORT
      LAYER M4 ;
        RECT 345.408 18.000 345.600 18.024 ;
    END
  END a_h[20]
  PIN a_h[21]
    DIRECTION INPUT ;
    USE SIGNAL ;
    PORT
      LAYER M4 ;
        RECT 345.408 18.384 345.600 18.408 ;
    END
  END a_h[21]
  PIN a_h[22]
    DIRECTION INPUT ;
    USE SIGNAL ;
    PORT
      LAYER M4 ;
        RECT 345.408 18.720 345.600 18.744 ;
    END
  END a_h[22]
  PIN a_h[23]
    DIRECTION INPUT ;
    USE SIGNAL ;
    PORT
      LAYER M4 ;
        RECT 345.408 19.056 345.600 19.080 ;
    END
  END a_h[23]
  PIN a_h[24]
    DIRECTION INPUT ;
    USE SIGNAL ;
    PORT
      LAYER M4 ;
        RECT 345.408 19.392 345.600 19.416 ;
    END
  END a_h[24]
  PIN a_h[25]
    DIRECTION INPUT ;
    USE SIGNAL ;
    PORT
      LAYER M4 ;
        RECT 345.408 19.728 345.600 19.752 ;
    END
  END a_h[25]
  PIN a_h[26]
    DIRECTION INPUT ;
    USE SIGNAL ;
    PORT
      LAYER M4 ;
        RECT 345.408 20.064 345.600 20.088 ;
    END
  END a_h[26]
  PIN a_h[27]
    DIRECTION INPUT ;
    USE SIGNAL ;
    PORT
      LAYER M4 ;
        RECT 345.408 20.400 345.600 20.424 ;
    END
  END a_h[27]
  PIN a_h[28]
    DIRECTION INPUT ;
    USE SIGNAL ;
    PORT
      LAYER M4 ;
        RECT 345.408 20.736 345.600 20.760 ;
    END
  END a_h[28]
  PIN a_h[29]
    DIRECTION INPUT ;
    USE SIGNAL ;
    PORT
      LAYER M4 ;
        RECT 345.408 21.072 345.600 21.096 ;
    END
  END a_h[29]
  PIN a_h[30]
    DIRECTION INPUT ;
    USE SIGNAL ;
    PORT
      LAYER M4 ;
        RECT 345.408 21.408 345.600 21.432 ;
    END
  END a_h[30]
  PIN a_h[31]
    DIRECTION INPUT ;
    USE SIGNAL ;
    PORT
      LAYER M4 ;
        RECT 345.408 21.744 345.600 21.768 ;
    END
  END a_h[31]
  PIN a_h[32]
    DIRECTION INPUT ;
    USE SIGNAL ;
    PORT
      LAYER M4 ;
        RECT 345.408 22.080 345.600 22.104 ;
    END
  END a_h[32]
  PIN a_h[33]
    DIRECTION INPUT ;
    USE SIGNAL ;
    PORT
      LAYER M4 ;
        RECT 345.408 22.416 345.600 22.440 ;
    END
  END a_h[33]
  PIN a_h[34]
    DIRECTION INPUT ;
    USE SIGNAL ;
    PORT
      LAYER M4 ;
        RECT 345.408 22.752 345.600 22.776 ;
    END
  END a_h[34]
  PIN a_h[35]
    DIRECTION INPUT ;
    USE SIGNAL ;
    PORT
      LAYER M4 ;
        RECT 345.408 23.088 345.600 23.112 ;
    END
  END a_h[35]
  PIN a_h[36]
    DIRECTION INPUT ;
    USE SIGNAL ;
    PORT
      LAYER M4 ;
        RECT 345.408 23.424 345.600 23.448 ;
    END
  END a_h[36]
  PIN a_h[37]
    DIRECTION INPUT ;
    USE SIGNAL ;
    PORT
      LAYER M4 ;
        RECT 345.408 23.760 345.600 23.784 ;
    END
  END a_h[37]
  PIN a_h[38]
    DIRECTION INPUT ;
    USE SIGNAL ;
    PORT
      LAYER M4 ;
        RECT 345.408 24.096 345.600 24.120 ;
    END
  END a_h[38]
  PIN a_h[39]
    DIRECTION INPUT ;
    USE SIGNAL ;
    PORT
      LAYER M4 ;
        RECT 345.408 24.432 345.600 24.456 ;
    END
  END a_h[39]
  PIN a_h[40]
    DIRECTION INPUT ;
    USE SIGNAL ;
    PORT
      LAYER M4 ;
        RECT 345.408 24.768 345.600 24.792 ;
    END
  END a_h[40]
  PIN a_h[41]
    DIRECTION INPUT ;
    USE SIGNAL ;
    PORT
      LAYER M4 ;
        RECT 345.408 25.104 345.600 25.128 ;
    END
  END a_h[41]
  PIN a_h[42]
    DIRECTION INPUT ;
    USE SIGNAL ;
    PORT
      LAYER M4 ;
        RECT 345.408 25.440 345.600 25.464 ;
    END
  END a_h[42]
  PIN a_h[43]
    DIRECTION INPUT ;
    USE SIGNAL ;
    PORT
      LAYER M4 ;
        RECT 345.408 25.776 345.600 25.800 ;
    END
  END a_h[43]
  PIN a_h[44]
    DIRECTION INPUT ;
    USE SIGNAL ;
    PORT
      LAYER M4 ;
        RECT 345.408 26.112 345.600 26.136 ;
    END
  END a_h[44]
  PIN a_h[45]
    DIRECTION INPUT ;
    USE SIGNAL ;
    PORT
      LAYER M4 ;
        RECT 345.408 26.448 345.600 26.472 ;
    END
  END a_h[45]
  PIN a_h[46]
    DIRECTION INPUT ;
    USE SIGNAL ;
    PORT
      LAYER M4 ;
        RECT 345.408 26.784 345.600 26.808 ;
    END
  END a_h[46]
  PIN a_h[47]
    DIRECTION INPUT ;
    USE SIGNAL ;
    PORT
      LAYER M4 ;
        RECT 345.408 27.120 345.600 27.144 ;
    END
  END a_h[47]
  PIN a_h[48]
    DIRECTION INPUT ;
    USE SIGNAL ;
    PORT
      LAYER M4 ;
        RECT 345.408 27.456 345.600 27.480 ;
    END
  END a_h[48]
  PIN a_h[49]
    DIRECTION INPUT ;
    USE SIGNAL ;
    PORT
      LAYER M4 ;
        RECT 345.408 27.792 345.600 27.816 ;
    END
  END a_h[49]
  PIN a_h[50]
    DIRECTION INPUT ;
    USE SIGNAL ;
    PORT
      LAYER M4 ;
        RECT 345.408 28.128 345.600 28.152 ;
    END
  END a_h[50]
  PIN a_h[51]
    DIRECTION INPUT ;
    USE SIGNAL ;
    PORT
      LAYER M4 ;
        RECT 345.408 28.464 345.600 28.488 ;
    END
  END a_h[51]
  PIN a_h[52]
    DIRECTION INPUT ;
    USE SIGNAL ;
    PORT
      LAYER M4 ;
        RECT 345.408 28.800 345.600 28.824 ;
    END
  END a_h[52]
  PIN a_h[53]
    DIRECTION INPUT ;
    USE SIGNAL ;
    PORT
      LAYER M4 ;
        RECT 345.408 29.136 345.600 29.160 ;
    END
  END a_h[53]
  PIN a_h[54]
    DIRECTION INPUT ;
    USE SIGNAL ;
    PORT
      LAYER M4 ;
        RECT 345.408 29.472 345.600 29.496 ;
    END
  END a_h[54]
  PIN a_h[55]
    DIRECTION INPUT ;
    USE SIGNAL ;
    PORT
      LAYER M4 ;
        RECT 345.408 29.856 345.600 29.880 ;
    END
  END a_h[55]
  PIN a_h[56]
    DIRECTION INPUT ;
    USE SIGNAL ;
    PORT
      LAYER M4 ;
        RECT 345.408 30.192 345.600 30.216 ;
    END
  END a_h[56]
  PIN a_h[57]
    DIRECTION INPUT ;
    USE SIGNAL ;
    PORT
      LAYER M4 ;
        RECT 345.408 30.528 345.600 30.552 ;
    END
  END a_h[57]
  PIN a_h[58]
    DIRECTION INPUT ;
    USE SIGNAL ;
    PORT
      LAYER M4 ;
        RECT 345.408 30.864 345.600 30.888 ;
    END
  END a_h[58]
  PIN a_h[59]
    DIRECTION INPUT ;
    USE SIGNAL ;
    PORT
      LAYER M4 ;
        RECT 345.408 31.200 345.600 31.224 ;
    END
  END a_h[59]
  PIN a_h[60]
    DIRECTION INPUT ;
    USE SIGNAL ;
    PORT
      LAYER M4 ;
        RECT 345.408 31.536 345.600 31.560 ;
    END
  END a_h[60]
  PIN a_h[61]
    DIRECTION INPUT ;
    USE SIGNAL ;
    PORT
      LAYER M4 ;
        RECT 345.408 31.872 345.600 31.896 ;
    END
  END a_h[61]
  PIN a_h[62]
    DIRECTION INPUT ;
    USE SIGNAL ;
    PORT
      LAYER M4 ;
        RECT 345.408 32.208 345.600 32.232 ;
    END
  END a_h[62]
  PIN a_h[63]
    DIRECTION INPUT ;
    USE SIGNAL ;
    PORT
      LAYER M4 ;
        RECT 345.408 32.544 345.600 32.568 ;
    END
  END a_h[63]
  PIN a_h[64]
    DIRECTION INPUT ;
    USE SIGNAL ;
    PORT
      LAYER M4 ;
        RECT 345.408 32.880 345.600 32.904 ;
    END
  END a_h[64]
  PIN a_h[65]
    DIRECTION INPUT ;
    USE SIGNAL ;
    PORT
      LAYER M4 ;
        RECT 345.408 33.216 345.600 33.240 ;
    END
  END a_h[65]
  PIN a_h[66]
    DIRECTION INPUT ;
    USE SIGNAL ;
    PORT
      LAYER M4 ;
        RECT 345.408 33.552 345.600 33.576 ;
    END
  END a_h[66]
  PIN a_h[67]
    DIRECTION INPUT ;
    USE SIGNAL ;
    PORT
      LAYER M4 ;
        RECT 345.408 33.888 345.600 33.912 ;
    END
  END a_h[67]
  PIN a_h[68]
    DIRECTION INPUT ;
    USE SIGNAL ;
    PORT
      LAYER M4 ;
        RECT 345.408 34.224 345.600 34.248 ;
    END
  END a_h[68]
  PIN a_h[69]
    DIRECTION INPUT ;
    USE SIGNAL ;
    PORT
      LAYER M4 ;
        RECT 345.408 34.560 345.600 34.584 ;
    END
  END a_h[69]
  PIN a_h[70]
    DIRECTION INPUT ;
    USE SIGNAL ;
    PORT
      LAYER M4 ;
        RECT 345.408 34.896 345.600 34.920 ;
    END
  END a_h[70]
  PIN a_h[71]
    DIRECTION INPUT ;
    USE SIGNAL ;
    PORT
      LAYER M4 ;
        RECT 345.408 35.232 345.600 35.256 ;
    END
  END a_h[71]
  PIN a_h[72]
    DIRECTION INPUT ;
    USE SIGNAL ;
    PORT
      LAYER M4 ;
        RECT 345.408 35.568 345.600 35.592 ;
    END
  END a_h[72]
  PIN a_h[73]
    DIRECTION INPUT ;
    USE SIGNAL ;
    PORT
      LAYER M4 ;
        RECT 345.408 35.904 345.600 35.928 ;
    END
  END a_h[73]
  PIN a_h[74]
    DIRECTION INPUT ;
    USE SIGNAL ;
    PORT
      LAYER M4 ;
        RECT 345.408 36.240 345.600 36.264 ;
    END
  END a_h[74]
  PIN a_h[75]
    DIRECTION INPUT ;
    USE SIGNAL ;
    PORT
      LAYER M4 ;
        RECT 345.408 36.576 345.600 36.600 ;
    END
  END a_h[75]
  PIN a_h[76]
    DIRECTION INPUT ;
    USE SIGNAL ;
    PORT
      LAYER M4 ;
        RECT 345.408 36.912 345.600 36.936 ;
    END
  END a_h[76]
  PIN a_h[77]
    DIRECTION INPUT ;
    USE SIGNAL ;
    PORT
      LAYER M4 ;
        RECT 345.408 37.248 345.600 37.272 ;
    END
  END a_h[77]
  PIN a_h[78]
    DIRECTION INPUT ;
    USE SIGNAL ;
    PORT
      LAYER M4 ;
        RECT 345.408 37.584 345.600 37.608 ;
    END
  END a_h[78]
  PIN a_h[79]
    DIRECTION INPUT ;
    USE SIGNAL ;
    PORT
      LAYER M4 ;
        RECT 345.408 37.920 345.600 37.944 ;
    END
  END a_h[79]
  PIN a_h[80]
    DIRECTION INPUT ;
    USE SIGNAL ;
    PORT
      LAYER M4 ;
        RECT 345.408 38.256 345.600 38.280 ;
    END
  END a_h[80]
  PIN a_h[81]
    DIRECTION INPUT ;
    USE SIGNAL ;
    PORT
      LAYER M4 ;
        RECT 345.408 38.592 345.600 38.616 ;
    END
  END a_h[81]
  PIN a_h[82]
    DIRECTION INPUT ;
    USE SIGNAL ;
    PORT
      LAYER M4 ;
        RECT 345.408 38.928 345.600 38.952 ;
    END
  END a_h[82]
  PIN a_h[83]
    DIRECTION INPUT ;
    USE SIGNAL ;
    PORT
      LAYER M4 ;
        RECT 345.408 39.264 345.600 39.288 ;
    END
  END a_h[83]
  PIN a_h[84]
    DIRECTION INPUT ;
    USE SIGNAL ;
    PORT
      LAYER M4 ;
        RECT 345.408 39.600 345.600 39.624 ;
    END
  END a_h[84]
  PIN a_h[85]
    DIRECTION INPUT ;
    USE SIGNAL ;
    PORT
      LAYER M4 ;
        RECT 345.408 39.936 345.600 39.960 ;
    END
  END a_h[85]
  PIN a_h[86]
    DIRECTION INPUT ;
    USE SIGNAL ;
    PORT
      LAYER M4 ;
        RECT 345.408 40.272 345.600 40.296 ;
    END
  END a_h[86]
  PIN a_h[87]
    DIRECTION INPUT ;
    USE SIGNAL ;
    PORT
      LAYER M4 ;
        RECT 345.408 40.608 345.600 40.632 ;
    END
  END a_h[87]
  PIN a_h[88]
    DIRECTION INPUT ;
    USE SIGNAL ;
    PORT
      LAYER M4 ;
        RECT 345.408 40.944 345.600 40.968 ;
    END
  END a_h[88]
  PIN a_h[89]
    DIRECTION INPUT ;
    USE SIGNAL ;
    PORT
      LAYER M4 ;
        RECT 345.408 41.328 345.600 41.352 ;
    END
  END a_h[89]
  PIN a_h[90]
    DIRECTION INPUT ;
    USE SIGNAL ;
    PORT
      LAYER M4 ;
        RECT 345.408 41.664 345.600 41.688 ;
    END
  END a_h[90]
  PIN a_h[91]
    DIRECTION INPUT ;
    USE SIGNAL ;
    PORT
      LAYER M4 ;
        RECT 345.408 42.000 345.600 42.024 ;
    END
  END a_h[91]
  PIN a_h[92]
    DIRECTION INPUT ;
    USE SIGNAL ;
    PORT
      LAYER M4 ;
        RECT 345.408 42.336 345.600 42.360 ;
    END
  END a_h[92]
  PIN a_h[93]
    DIRECTION INPUT ;
    USE SIGNAL ;
    PORT
      LAYER M4 ;
        RECT 345.408 42.672 345.600 42.696 ;
    END
  END a_h[93]
  PIN a_h[94]
    DIRECTION INPUT ;
    USE SIGNAL ;
    PORT
      LAYER M4 ;
        RECT 345.408 43.008 345.600 43.032 ;
    END
  END a_h[94]
  PIN a_h[95]
    DIRECTION INPUT ;
    USE SIGNAL ;
    PORT
      LAYER M4 ;
        RECT 345.408 43.344 345.600 43.368 ;
    END
  END a_h[95]
  PIN a_h[96]
    DIRECTION INPUT ;
    USE SIGNAL ;
    PORT
      LAYER M4 ;
        RECT 345.408 43.680 345.600 43.704 ;
    END
  END a_h[96]
  PIN a_h[97]
    DIRECTION INPUT ;
    USE SIGNAL ;
    PORT
      LAYER M4 ;
        RECT 345.408 44.016 345.600 44.040 ;
    END
  END a_h[97]
  PIN a_h[98]
    DIRECTION INPUT ;
    USE SIGNAL ;
    PORT
      LAYER M4 ;
        RECT 345.408 44.352 345.600 44.376 ;
    END
  END a_h[98]
  PIN a_h[99]
    DIRECTION INPUT ;
    USE SIGNAL ;
    PORT
      LAYER M4 ;
        RECT 345.408 44.688 345.600 44.712 ;
    END
  END a_h[99]
  PIN a_h[100]
    DIRECTION INPUT ;
    USE SIGNAL ;
    PORT
      LAYER M4 ;
        RECT 345.408 45.024 345.600 45.048 ;
    END
  END a_h[100]
  PIN a_h[101]
    DIRECTION INPUT ;
    USE SIGNAL ;
    PORT
      LAYER M4 ;
        RECT 345.408 45.360 345.600 45.384 ;
    END
  END a_h[101]
  PIN a_h[102]
    DIRECTION INPUT ;
    USE SIGNAL ;
    PORT
      LAYER M4 ;
        RECT 345.408 45.696 345.600 45.720 ;
    END
  END a_h[102]
  PIN a_h[103]
    DIRECTION INPUT ;
    USE SIGNAL ;
    PORT
      LAYER M4 ;
        RECT 345.408 46.032 345.600 46.056 ;
    END
  END a_h[103]
  PIN a_h[104]
    DIRECTION INPUT ;
    USE SIGNAL ;
    PORT
      LAYER M4 ;
        RECT 345.408 46.368 345.600 46.392 ;
    END
  END a_h[104]
  PIN a_h[105]
    DIRECTION INPUT ;
    USE SIGNAL ;
    PORT
      LAYER M4 ;
        RECT 345.408 46.704 345.600 46.728 ;
    END
  END a_h[105]
  PIN a_h[106]
    DIRECTION INPUT ;
    USE SIGNAL ;
    PORT
      LAYER M4 ;
        RECT 345.408 47.040 345.600 47.064 ;
    END
  END a_h[106]
  PIN a_h[107]
    DIRECTION INPUT ;
    USE SIGNAL ;
    PORT
      LAYER M4 ;
        RECT 345.408 47.376 345.600 47.400 ;
    END
  END a_h[107]
  PIN a_h[108]
    DIRECTION INPUT ;
    USE SIGNAL ;
    PORT
      LAYER M4 ;
        RECT 345.408 47.712 345.600 47.736 ;
    END
  END a_h[108]
  PIN a_h[109]
    DIRECTION INPUT ;
    USE SIGNAL ;
    PORT
      LAYER M4 ;
        RECT 345.408 48.048 345.600 48.072 ;
    END
  END a_h[109]
  PIN a_h[110]
    DIRECTION INPUT ;
    USE SIGNAL ;
    PORT
      LAYER M4 ;
        RECT 345.408 48.384 345.600 48.408 ;
    END
  END a_h[110]
  PIN a_h[111]
    DIRECTION INPUT ;
    USE SIGNAL ;
    PORT
      LAYER M4 ;
        RECT 345.408 48.720 345.600 48.744 ;
    END
  END a_h[111]
  PIN a_h[112]
    DIRECTION INPUT ;
    USE SIGNAL ;
    PORT
      LAYER M4 ;
        RECT 345.408 49.056 345.600 49.080 ;
    END
  END a_h[112]
  PIN a_h[113]
    DIRECTION INPUT ;
    USE SIGNAL ;
    PORT
      LAYER M4 ;
        RECT 345.408 49.392 345.600 49.416 ;
    END
  END a_h[113]
  PIN a_h[114]
    DIRECTION INPUT ;
    USE SIGNAL ;
    PORT
      LAYER M4 ;
        RECT 345.408 49.728 345.600 49.752 ;
    END
  END a_h[114]
  PIN a_h[115]
    DIRECTION INPUT ;
    USE SIGNAL ;
    PORT
      LAYER M4 ;
        RECT 345.408 50.064 345.600 50.088 ;
    END
  END a_h[115]
  PIN a_h[116]
    DIRECTION INPUT ;
    USE SIGNAL ;
    PORT
      LAYER M4 ;
        RECT 345.408 50.400 345.600 50.424 ;
    END
  END a_h[116]
  PIN a_h[117]
    DIRECTION INPUT ;
    USE SIGNAL ;
    PORT
      LAYER M4 ;
        RECT 345.408 50.736 345.600 50.760 ;
    END
  END a_h[117]
  PIN a_h[118]
    DIRECTION INPUT ;
    USE SIGNAL ;
    PORT
      LAYER M4 ;
        RECT 345.408 51.072 345.600 51.096 ;
    END
  END a_h[118]
  PIN a_h[119]
    DIRECTION INPUT ;
    USE SIGNAL ;
    PORT
      LAYER M4 ;
        RECT 345.408 51.408 345.600 51.432 ;
    END
  END a_h[119]
  PIN a_h[120]
    DIRECTION INPUT ;
    USE SIGNAL ;
    PORT
      LAYER M4 ;
        RECT 345.408 51.744 345.600 51.768 ;
    END
  END a_h[120]
  PIN a_h[121]
    DIRECTION INPUT ;
    USE SIGNAL ;
    PORT
      LAYER M4 ;
        RECT 345.408 52.080 345.600 52.104 ;
    END
  END a_h[121]
  PIN a_h[122]
    DIRECTION INPUT ;
    USE SIGNAL ;
    PORT
      LAYER M4 ;
        RECT 345.408 52.416 345.600 52.440 ;
    END
  END a_h[122]
  PIN a_h[123]
    DIRECTION INPUT ;
    USE SIGNAL ;
    PORT
      LAYER M4 ;
        RECT 345.408 52.800 345.600 52.824 ;
    END
  END a_h[123]
  PIN a_h[124]
    DIRECTION INPUT ;
    USE SIGNAL ;
    PORT
      LAYER M4 ;
        RECT 345.408 53.136 345.600 53.160 ;
    END
  END a_h[124]
  PIN a_h[125]
    DIRECTION INPUT ;
    USE SIGNAL ;
    PORT
      LAYER M4 ;
        RECT 345.408 53.472 345.600 53.496 ;
    END
  END a_h[125]
  PIN a_h[126]
    DIRECTION INPUT ;
    USE SIGNAL ;
    PORT
      LAYER M4 ;
        RECT 345.408 53.808 345.600 53.832 ;
    END
  END a_h[126]
  PIN a_h[127]
    DIRECTION INPUT ;
    USE SIGNAL ;
    PORT
      LAYER M4 ;
        RECT 345.408 54.144 345.600 54.168 ;
    END
  END a_h[127]
  PIN a_h[128]
    DIRECTION INPUT ;
    USE SIGNAL ;
    PORT
      LAYER M4 ;
        RECT 345.408 54.480 345.600 54.504 ;
    END
  END a_h[128]
  PIN a_h[129]
    DIRECTION INPUT ;
    USE SIGNAL ;
    PORT
      LAYER M4 ;
        RECT 345.408 54.816 345.600 54.840 ;
    END
  END a_h[129]
  PIN a_h[130]
    DIRECTION INPUT ;
    USE SIGNAL ;
    PORT
      LAYER M4 ;
        RECT 345.408 55.152 345.600 55.176 ;
    END
  END a_h[130]
  PIN a_h[131]
    DIRECTION INPUT ;
    USE SIGNAL ;
    PORT
      LAYER M4 ;
        RECT 345.408 55.488 345.600 55.512 ;
    END
  END a_h[131]
  PIN a_h[132]
    DIRECTION INPUT ;
    USE SIGNAL ;
    PORT
      LAYER M4 ;
        RECT 345.408 55.824 345.600 55.848 ;
    END
  END a_h[132]
  PIN a_h[133]
    DIRECTION INPUT ;
    USE SIGNAL ;
    PORT
      LAYER M4 ;
        RECT 345.408 56.160 345.600 56.184 ;
    END
  END a_h[133]
  PIN a_h[134]
    DIRECTION INPUT ;
    USE SIGNAL ;
    PORT
      LAYER M4 ;
        RECT 345.408 56.496 345.600 56.520 ;
    END
  END a_h[134]
  PIN a_h[135]
    DIRECTION INPUT ;
    USE SIGNAL ;
    PORT
      LAYER M4 ;
        RECT 345.408 56.832 345.600 56.856 ;
    END
  END a_h[135]
  PIN a_h[136]
    DIRECTION INPUT ;
    USE SIGNAL ;
    PORT
      LAYER M4 ;
        RECT 345.408 57.168 345.600 57.192 ;
    END
  END a_h[136]
  PIN a_h[137]
    DIRECTION INPUT ;
    USE SIGNAL ;
    PORT
      LAYER M4 ;
        RECT 345.408 57.504 345.600 57.528 ;
    END
  END a_h[137]
  PIN a_h[138]
    DIRECTION INPUT ;
    USE SIGNAL ;
    PORT
      LAYER M4 ;
        RECT 345.408 57.840 345.600 57.864 ;
    END
  END a_h[138]
  PIN a_h[139]
    DIRECTION INPUT ;
    USE SIGNAL ;
    PORT
      LAYER M4 ;
        RECT 345.408 58.176 345.600 58.200 ;
    END
  END a_h[139]
  PIN a_h[140]
    DIRECTION INPUT ;
    USE SIGNAL ;
    PORT
      LAYER M4 ;
        RECT 345.408 58.512 345.600 58.536 ;
    END
  END a_h[140]
  PIN a_h[141]
    DIRECTION INPUT ;
    USE SIGNAL ;
    PORT
      LAYER M4 ;
        RECT 345.408 58.848 345.600 58.872 ;
    END
  END a_h[141]
  PIN a_h[142]
    DIRECTION INPUT ;
    USE SIGNAL ;
    PORT
      LAYER M4 ;
        RECT 345.408 59.184 345.600 59.208 ;
    END
  END a_h[142]
  PIN a_h[143]
    DIRECTION INPUT ;
    USE SIGNAL ;
    PORT
      LAYER M4 ;
        RECT 345.408 59.520 345.600 59.544 ;
    END
  END a_h[143]
  PIN a_h[144]
    DIRECTION INPUT ;
    USE SIGNAL ;
    PORT
      LAYER M4 ;
        RECT 345.408 59.856 345.600 59.880 ;
    END
  END a_h[144]
  PIN a_h[145]
    DIRECTION INPUT ;
    USE SIGNAL ;
    PORT
      LAYER M4 ;
        RECT 345.408 60.192 345.600 60.216 ;
    END
  END a_h[145]
  PIN a_h[146]
    DIRECTION INPUT ;
    USE SIGNAL ;
    PORT
      LAYER M4 ;
        RECT 345.408 60.528 345.600 60.552 ;
    END
  END a_h[146]
  PIN a_h[147]
    DIRECTION INPUT ;
    USE SIGNAL ;
    PORT
      LAYER M4 ;
        RECT 345.408 60.864 345.600 60.888 ;
    END
  END a_h[147]
  PIN a_h[148]
    DIRECTION INPUT ;
    USE SIGNAL ;
    PORT
      LAYER M4 ;
        RECT 345.408 61.200 345.600 61.224 ;
    END
  END a_h[148]
  PIN a_h[149]
    DIRECTION INPUT ;
    USE SIGNAL ;
    PORT
      LAYER M4 ;
        RECT 345.408 61.536 345.600 61.560 ;
    END
  END a_h[149]
  PIN a_h[150]
    DIRECTION INPUT ;
    USE SIGNAL ;
    PORT
      LAYER M4 ;
        RECT 345.408 61.872 345.600 61.896 ;
    END
  END a_h[150]
  PIN a_h[151]
    DIRECTION INPUT ;
    USE SIGNAL ;
    PORT
      LAYER M4 ;
        RECT 345.408 62.208 345.600 62.232 ;
    END
  END a_h[151]
  PIN a_h[152]
    DIRECTION INPUT ;
    USE SIGNAL ;
    PORT
      LAYER M4 ;
        RECT 345.408 62.544 345.600 62.568 ;
    END
  END a_h[152]
  PIN a_h[153]
    DIRECTION INPUT ;
    USE SIGNAL ;
    PORT
      LAYER M4 ;
        RECT 345.408 62.880 345.600 62.904 ;
    END
  END a_h[153]
  PIN a_h[154]
    DIRECTION INPUT ;
    USE SIGNAL ;
    PORT
      LAYER M4 ;
        RECT 345.408 63.216 345.600 63.240 ;
    END
  END a_h[154]
  PIN a_h[155]
    DIRECTION INPUT ;
    USE SIGNAL ;
    PORT
      LAYER M4 ;
        RECT 345.408 63.552 345.600 63.576 ;
    END
  END a_h[155]
  PIN a_h[156]
    DIRECTION INPUT ;
    USE SIGNAL ;
    PORT
      LAYER M4 ;
        RECT 345.408 63.888 345.600 63.912 ;
    END
  END a_h[156]
  PIN a_h[157]
    DIRECTION INPUT ;
    USE SIGNAL ;
    PORT
      LAYER M4 ;
        RECT 345.408 64.272 345.600 64.296 ;
    END
  END a_h[157]
  PIN a_h[158]
    DIRECTION INPUT ;
    USE SIGNAL ;
    PORT
      LAYER M4 ;
        RECT 345.408 64.608 345.600 64.632 ;
    END
  END a_h[158]
  PIN a_h[159]
    DIRECTION INPUT ;
    USE SIGNAL ;
    PORT
      LAYER M4 ;
        RECT 345.408 64.944 345.600 64.968 ;
    END
  END a_h[159]
  PIN a_h[160]
    DIRECTION INPUT ;
    USE SIGNAL ;
    PORT
      LAYER M4 ;
        RECT 345.408 65.280 345.600 65.304 ;
    END
  END a_h[160]
  PIN a_h[161]
    DIRECTION INPUT ;
    USE SIGNAL ;
    PORT
      LAYER M4 ;
        RECT 345.408 65.616 345.600 65.640 ;
    END
  END a_h[161]
  PIN a_h[162]
    DIRECTION INPUT ;
    USE SIGNAL ;
    PORT
      LAYER M4 ;
        RECT 345.408 65.952 345.600 65.976 ;
    END
  END a_h[162]
  PIN a_h[163]
    DIRECTION INPUT ;
    USE SIGNAL ;
    PORT
      LAYER M4 ;
        RECT 345.408 66.288 345.600 66.312 ;
    END
  END a_h[163]
  PIN a_h[164]
    DIRECTION INPUT ;
    USE SIGNAL ;
    PORT
      LAYER M4 ;
        RECT 345.408 66.624 345.600 66.648 ;
    END
  END a_h[164]
  PIN a_h[165]
    DIRECTION INPUT ;
    USE SIGNAL ;
    PORT
      LAYER M4 ;
        RECT 345.408 66.960 345.600 66.984 ;
    END
  END a_h[165]
  PIN a_h[166]
    DIRECTION INPUT ;
    USE SIGNAL ;
    PORT
      LAYER M4 ;
        RECT 345.408 67.296 345.600 67.320 ;
    END
  END a_h[166]
  PIN a_h[167]
    DIRECTION INPUT ;
    USE SIGNAL ;
    PORT
      LAYER M4 ;
        RECT 345.408 67.632 345.600 67.656 ;
    END
  END a_h[167]
  PIN a_h[168]
    DIRECTION INPUT ;
    USE SIGNAL ;
    PORT
      LAYER M4 ;
        RECT 345.408 67.968 345.600 67.992 ;
    END
  END a_h[168]
  PIN a_h[169]
    DIRECTION INPUT ;
    USE SIGNAL ;
    PORT
      LAYER M4 ;
        RECT 345.408 68.304 345.600 68.328 ;
    END
  END a_h[169]
  PIN a_h[170]
    DIRECTION INPUT ;
    USE SIGNAL ;
    PORT
      LAYER M4 ;
        RECT 345.408 68.640 345.600 68.664 ;
    END
  END a_h[170]
  PIN a_h[171]
    DIRECTION INPUT ;
    USE SIGNAL ;
    PORT
      LAYER M4 ;
        RECT 345.408 68.976 345.600 69.000 ;
    END
  END a_h[171]
  PIN a_h[172]
    DIRECTION INPUT ;
    USE SIGNAL ;
    PORT
      LAYER M4 ;
        RECT 345.408 69.312 345.600 69.336 ;
    END
  END a_h[172]
  PIN a_h[173]
    DIRECTION INPUT ;
    USE SIGNAL ;
    PORT
      LAYER M4 ;
        RECT 345.408 69.648 345.600 69.672 ;
    END
  END a_h[173]
  PIN a_h[174]
    DIRECTION INPUT ;
    USE SIGNAL ;
    PORT
      LAYER M4 ;
        RECT 345.408 69.984 345.600 70.008 ;
    END
  END a_h[174]
  PIN a_h[175]
    DIRECTION INPUT ;
    USE SIGNAL ;
    PORT
      LAYER M4 ;
        RECT 345.408 70.320 345.600 70.344 ;
    END
  END a_h[175]
  PIN a_h[176]
    DIRECTION INPUT ;
    USE SIGNAL ;
    PORT
      LAYER M4 ;
        RECT 345.408 70.656 345.600 70.680 ;
    END
  END a_h[176]
  PIN a_h[177]
    DIRECTION INPUT ;
    USE SIGNAL ;
    PORT
      LAYER M4 ;
        RECT 345.408 70.992 345.600 71.016 ;
    END
  END a_h[177]
  PIN a_h[178]
    DIRECTION INPUT ;
    USE SIGNAL ;
    PORT
      LAYER M4 ;
        RECT 345.408 71.328 345.600 71.352 ;
    END
  END a_h[178]
  PIN a_h[179]
    DIRECTION INPUT ;
    USE SIGNAL ;
    PORT
      LAYER M4 ;
        RECT 345.408 71.664 345.600 71.688 ;
    END
  END a_h[179]
  PIN a_h[180]
    DIRECTION INPUT ;
    USE SIGNAL ;
    PORT
      LAYER M4 ;
        RECT 345.408 72.000 345.600 72.024 ;
    END
  END a_h[180]
  PIN a_h[181]
    DIRECTION INPUT ;
    USE SIGNAL ;
    PORT
      LAYER M4 ;
        RECT 345.408 72.336 345.600 72.360 ;
    END
  END a_h[181]
  PIN a_h[182]
    DIRECTION INPUT ;
    USE SIGNAL ;
    PORT
      LAYER M4 ;
        RECT 345.408 72.672 345.600 72.696 ;
    END
  END a_h[182]
  PIN a_h[183]
    DIRECTION INPUT ;
    USE SIGNAL ;
    PORT
      LAYER M4 ;
        RECT 345.408 73.008 345.600 73.032 ;
    END
  END a_h[183]
  PIN a_h[184]
    DIRECTION INPUT ;
    USE SIGNAL ;
    PORT
      LAYER M4 ;
        RECT 345.408 73.344 345.600 73.368 ;
    END
  END a_h[184]
  PIN a_h[185]
    DIRECTION INPUT ;
    USE SIGNAL ;
    PORT
      LAYER M4 ;
        RECT 345.408 73.680 345.600 73.704 ;
    END
  END a_h[185]
  PIN a_h[186]
    DIRECTION INPUT ;
    USE SIGNAL ;
    PORT
      LAYER M4 ;
        RECT 345.408 74.016 345.600 74.040 ;
    END
  END a_h[186]
  PIN a_h[187]
    DIRECTION INPUT ;
    USE SIGNAL ;
    PORT
      LAYER M4 ;
        RECT 345.408 74.352 345.600 74.376 ;
    END
  END a_h[187]
  PIN a_h[188]
    DIRECTION INPUT ;
    USE SIGNAL ;
    PORT
      LAYER M4 ;
        RECT 345.408 74.688 345.600 74.712 ;
    END
  END a_h[188]
  PIN a_h[189]
    DIRECTION INPUT ;
    USE SIGNAL ;
    PORT
      LAYER M4 ;
        RECT 345.408 75.024 345.600 75.048 ;
    END
  END a_h[189]
  PIN a_h[190]
    DIRECTION INPUT ;
    USE SIGNAL ;
    PORT
      LAYER M4 ;
        RECT 345.408 75.360 345.600 75.384 ;
    END
  END a_h[190]
  PIN a_h[191]
    DIRECTION INPUT ;
    USE SIGNAL ;
    PORT
      LAYER M4 ;
        RECT 345.408 75.744 345.600 75.768 ;
    END
  END a_h[191]
  PIN a_h[192]
    DIRECTION INPUT ;
    USE SIGNAL ;
    PORT
      LAYER M4 ;
        RECT 345.408 76.080 345.600 76.104 ;
    END
  END a_h[192]
  PIN a_h[193]
    DIRECTION INPUT ;
    USE SIGNAL ;
    PORT
      LAYER M4 ;
        RECT 345.408 76.416 345.600 76.440 ;
    END
  END a_h[193]
  PIN a_h[194]
    DIRECTION INPUT ;
    USE SIGNAL ;
    PORT
      LAYER M4 ;
        RECT 345.408 76.752 345.600 76.776 ;
    END
  END a_h[194]
  PIN a_h[195]
    DIRECTION INPUT ;
    USE SIGNAL ;
    PORT
      LAYER M4 ;
        RECT 345.408 77.088 345.600 77.112 ;
    END
  END a_h[195]
  PIN a_h[196]
    DIRECTION INPUT ;
    USE SIGNAL ;
    PORT
      LAYER M4 ;
        RECT 345.408 77.424 345.600 77.448 ;
    END
  END a_h[196]
  PIN a_h[197]
    DIRECTION INPUT ;
    USE SIGNAL ;
    PORT
      LAYER M4 ;
        RECT 345.408 77.760 345.600 77.784 ;
    END
  END a_h[197]
  PIN a_h[198]
    DIRECTION INPUT ;
    USE SIGNAL ;
    PORT
      LAYER M4 ;
        RECT 345.408 78.096 345.600 78.120 ;
    END
  END a_h[198]
  PIN a_h[199]
    DIRECTION INPUT ;
    USE SIGNAL ;
    PORT
      LAYER M4 ;
        RECT 345.408 78.432 345.600 78.456 ;
    END
  END a_h[199]
  PIN a_h[200]
    DIRECTION INPUT ;
    USE SIGNAL ;
    PORT
      LAYER M4 ;
        RECT 345.408 78.768 345.600 78.792 ;
    END
  END a_h[200]
  PIN a_h[201]
    DIRECTION INPUT ;
    USE SIGNAL ;
    PORT
      LAYER M4 ;
        RECT 345.408 79.104 345.600 79.128 ;
    END
  END a_h[201]
  PIN a_h[202]
    DIRECTION INPUT ;
    USE SIGNAL ;
    PORT
      LAYER M4 ;
        RECT 345.408 79.440 345.600 79.464 ;
    END
  END a_h[202]
  PIN a_h[203]
    DIRECTION INPUT ;
    USE SIGNAL ;
    PORT
      LAYER M4 ;
        RECT 345.408 79.776 345.600 79.800 ;
    END
  END a_h[203]
  PIN a_h[204]
    DIRECTION INPUT ;
    USE SIGNAL ;
    PORT
      LAYER M4 ;
        RECT 345.408 80.112 345.600 80.136 ;
    END
  END a_h[204]
  PIN a_h[205]
    DIRECTION INPUT ;
    USE SIGNAL ;
    PORT
      LAYER M4 ;
        RECT 345.408 80.448 345.600 80.472 ;
    END
  END a_h[205]
  PIN a_h[206]
    DIRECTION INPUT ;
    USE SIGNAL ;
    PORT
      LAYER M4 ;
        RECT 345.408 80.784 345.600 80.808 ;
    END
  END a_h[206]
  PIN a_h[207]
    DIRECTION INPUT ;
    USE SIGNAL ;
    PORT
      LAYER M4 ;
        RECT 345.408 81.120 345.600 81.144 ;
    END
  END a_h[207]
  PIN a_h[208]
    DIRECTION INPUT ;
    USE SIGNAL ;
    PORT
      LAYER M4 ;
        RECT 345.408 81.456 345.600 81.480 ;
    END
  END a_h[208]
  PIN a_h[209]
    DIRECTION INPUT ;
    USE SIGNAL ;
    PORT
      LAYER M4 ;
        RECT 345.408 81.792 345.600 81.816 ;
    END
  END a_h[209]
  PIN a_h[210]
    DIRECTION INPUT ;
    USE SIGNAL ;
    PORT
      LAYER M4 ;
        RECT 345.408 82.128 345.600 82.152 ;
    END
  END a_h[210]
  PIN a_h[211]
    DIRECTION INPUT ;
    USE SIGNAL ;
    PORT
      LAYER M4 ;
        RECT 345.408 82.464 345.600 82.488 ;
    END
  END a_h[211]
  PIN a_h[212]
    DIRECTION INPUT ;
    USE SIGNAL ;
    PORT
      LAYER M4 ;
        RECT 345.408 82.800 345.600 82.824 ;
    END
  END a_h[212]
  PIN a_h[213]
    DIRECTION INPUT ;
    USE SIGNAL ;
    PORT
      LAYER M4 ;
        RECT 345.408 83.136 345.600 83.160 ;
    END
  END a_h[213]
  PIN a_h[214]
    DIRECTION INPUT ;
    USE SIGNAL ;
    PORT
      LAYER M4 ;
        RECT 345.408 83.472 345.600 83.496 ;
    END
  END a_h[214]
  PIN a_h[215]
    DIRECTION INPUT ;
    USE SIGNAL ;
    PORT
      LAYER M4 ;
        RECT 345.408 83.808 345.600 83.832 ;
    END
  END a_h[215]
  PIN a_h[216]
    DIRECTION INPUT ;
    USE SIGNAL ;
    PORT
      LAYER M4 ;
        RECT 345.408 84.144 345.600 84.168 ;
    END
  END a_h[216]
  PIN a_h[217]
    DIRECTION INPUT ;
    USE SIGNAL ;
    PORT
      LAYER M4 ;
        RECT 345.408 84.480 345.600 84.504 ;
    END
  END a_h[217]
  PIN a_h[218]
    DIRECTION INPUT ;
    USE SIGNAL ;
    PORT
      LAYER M4 ;
        RECT 345.408 84.816 345.600 84.840 ;
    END
  END a_h[218]
  PIN a_h[219]
    DIRECTION INPUT ;
    USE SIGNAL ;
    PORT
      LAYER M4 ;
        RECT 345.408 85.152 345.600 85.176 ;
    END
  END a_h[219]
  PIN a_h[220]
    DIRECTION INPUT ;
    USE SIGNAL ;
    PORT
      LAYER M4 ;
        RECT 345.408 85.488 345.600 85.512 ;
    END
  END a_h[220]
  PIN a_h[221]
    DIRECTION INPUT ;
    USE SIGNAL ;
    PORT
      LAYER M4 ;
        RECT 345.408 85.824 345.600 85.848 ;
    END
  END a_h[221]
  PIN a_h[222]
    DIRECTION INPUT ;
    USE SIGNAL ;
    PORT
      LAYER M4 ;
        RECT 345.408 86.160 345.600 86.184 ;
    END
  END a_h[222]
  PIN a_h[223]
    DIRECTION INPUT ;
    USE SIGNAL ;
    PORT
      LAYER M4 ;
        RECT 345.408 86.496 345.600 86.520 ;
    END
  END a_h[223]
  PIN a_h[224]
    DIRECTION INPUT ;
    USE SIGNAL ;
    PORT
      LAYER M4 ;
        RECT 345.408 86.832 345.600 86.856 ;
    END
  END a_h[224]
  PIN a_h[225]
    DIRECTION INPUT ;
    USE SIGNAL ;
    PORT
      LAYER M4 ;
        RECT 345.408 87.168 345.600 87.192 ;
    END
  END a_h[225]
  PIN a_h[226]
    DIRECTION INPUT ;
    USE SIGNAL ;
    PORT
      LAYER M4 ;
        RECT 345.408 87.552 345.600 87.576 ;
    END
  END a_h[226]
  PIN a_h[227]
    DIRECTION INPUT ;
    USE SIGNAL ;
    PORT
      LAYER M4 ;
        RECT 345.408 87.888 345.600 87.912 ;
    END
  END a_h[227]
  PIN a_h[228]
    DIRECTION INPUT ;
    USE SIGNAL ;
    PORT
      LAYER M4 ;
        RECT 345.408 88.224 345.600 88.248 ;
    END
  END a_h[228]
  PIN a_h[229]
    DIRECTION INPUT ;
    USE SIGNAL ;
    PORT
      LAYER M4 ;
        RECT 345.408 88.560 345.600 88.584 ;
    END
  END a_h[229]
  PIN a_h[230]
    DIRECTION INPUT ;
    USE SIGNAL ;
    PORT
      LAYER M4 ;
        RECT 345.408 88.896 345.600 88.920 ;
    END
  END a_h[230]
  PIN a_h[231]
    DIRECTION INPUT ;
    USE SIGNAL ;
    PORT
      LAYER M4 ;
        RECT 345.408 89.232 345.600 89.256 ;
    END
  END a_h[231]
  PIN a_h[232]
    DIRECTION INPUT ;
    USE SIGNAL ;
    PORT
      LAYER M4 ;
        RECT 345.408 89.568 345.600 89.592 ;
    END
  END a_h[232]
  PIN a_h[233]
    DIRECTION INPUT ;
    USE SIGNAL ;
    PORT
      LAYER M4 ;
        RECT 345.408 89.904 345.600 89.928 ;
    END
  END a_h[233]
  PIN a_h[234]
    DIRECTION INPUT ;
    USE SIGNAL ;
    PORT
      LAYER M4 ;
        RECT 345.408 90.240 345.600 90.264 ;
    END
  END a_h[234]
  PIN a_h[235]
    DIRECTION INPUT ;
    USE SIGNAL ;
    PORT
      LAYER M4 ;
        RECT 345.408 90.576 345.600 90.600 ;
    END
  END a_h[235]
  PIN a_h[236]
    DIRECTION INPUT ;
    USE SIGNAL ;
    PORT
      LAYER M4 ;
        RECT 345.408 90.912 345.600 90.936 ;
    END
  END a_h[236]
  PIN a_h[237]
    DIRECTION INPUT ;
    USE SIGNAL ;
    PORT
      LAYER M4 ;
        RECT 345.408 91.248 345.600 91.272 ;
    END
  END a_h[237]
  PIN a_h[238]
    DIRECTION INPUT ;
    USE SIGNAL ;
    PORT
      LAYER M4 ;
        RECT 345.408 91.584 345.600 91.608 ;
    END
  END a_h[238]
  PIN a_h[239]
    DIRECTION INPUT ;
    USE SIGNAL ;
    PORT
      LAYER M4 ;
        RECT 345.408 91.920 345.600 91.944 ;
    END
  END a_h[239]
  PIN a_h[240]
    DIRECTION INPUT ;
    USE SIGNAL ;
    PORT
      LAYER M4 ;
        RECT 345.408 92.256 345.600 92.280 ;
    END
  END a_h[240]
  PIN a_h[241]
    DIRECTION INPUT ;
    USE SIGNAL ;
    PORT
      LAYER M4 ;
        RECT 345.408 92.592 345.600 92.616 ;
    END
  END a_h[241]
  PIN a_h[242]
    DIRECTION INPUT ;
    USE SIGNAL ;
    PORT
      LAYER M4 ;
        RECT 345.408 92.928 345.600 92.952 ;
    END
  END a_h[242]
  PIN a_h[243]
    DIRECTION INPUT ;
    USE SIGNAL ;
    PORT
      LAYER M4 ;
        RECT 345.408 93.264 345.600 93.288 ;
    END
  END a_h[243]
  PIN a_h[244]
    DIRECTION INPUT ;
    USE SIGNAL ;
    PORT
      LAYER M4 ;
        RECT 345.408 93.600 345.600 93.624 ;
    END
  END a_h[244]
  PIN a_h[245]
    DIRECTION INPUT ;
    USE SIGNAL ;
    PORT
      LAYER M4 ;
        RECT 345.408 93.936 345.600 93.960 ;
    END
  END a_h[245]
  PIN a_h[246]
    DIRECTION INPUT ;
    USE SIGNAL ;
    PORT
      LAYER M4 ;
        RECT 345.408 94.272 345.600 94.296 ;
    END
  END a_h[246]
  PIN a_h[247]
    DIRECTION INPUT ;
    USE SIGNAL ;
    PORT
      LAYER M4 ;
        RECT 345.408 94.608 345.600 94.632 ;
    END
  END a_h[247]
  PIN a_h[248]
    DIRECTION INPUT ;
    USE SIGNAL ;
    PORT
      LAYER M4 ;
        RECT 345.408 94.944 345.600 94.968 ;
    END
  END a_h[248]
  PIN a_h[249]
    DIRECTION INPUT ;
    USE SIGNAL ;
    PORT
      LAYER M4 ;
        RECT 345.408 95.280 345.600 95.304 ;
    END
  END a_h[249]
  PIN a_h[250]
    DIRECTION INPUT ;
    USE SIGNAL ;
    PORT
      LAYER M4 ;
        RECT 345.408 95.616 345.600 95.640 ;
    END
  END a_h[250]
  PIN a_h[251]
    DIRECTION INPUT ;
    USE SIGNAL ;
    PORT
      LAYER M4 ;
        RECT 345.408 95.952 345.600 95.976 ;
    END
  END a_h[251]
  PIN a_h[252]
    DIRECTION INPUT ;
    USE SIGNAL ;
    PORT
      LAYER M4 ;
        RECT 345.408 96.288 345.600 96.312 ;
    END
  END a_h[252]
  PIN a_h[253]
    DIRECTION INPUT ;
    USE SIGNAL ;
    PORT
      LAYER M4 ;
        RECT 345.408 96.624 345.600 96.648 ;
    END
  END a_h[253]
  PIN a_h[254]
    DIRECTION INPUT ;
    USE SIGNAL ;
    PORT
      LAYER M4 ;
        RECT 345.408 96.960 345.600 96.984 ;
    END
  END a_h[254]
  PIN a_h[255]
    DIRECTION INPUT ;
    USE SIGNAL ;
    PORT
      LAYER M4 ;
        RECT 345.408 97.296 345.600 97.320 ;
    END
  END a_h[255]
  PIN a_val[0]
    DIRECTION INPUT ;
    USE SIGNAL ;
    PORT
      LAYER M4 ;
        RECT 345.408 97.632 345.600 97.656 ;
    END
  END a_val[0]
  PIN a_val[1]
    DIRECTION INPUT ;
    USE SIGNAL ;
    PORT
      LAYER M4 ;
        RECT 345.408 97.968 345.600 97.992 ;
    END
  END a_val[1]
  PIN a_val[2]
    DIRECTION INPUT ;
    USE SIGNAL ;
    PORT
      LAYER M4 ;
        RECT 345.408 98.304 345.600 98.328 ;
    END
  END a_val[2]
  PIN a_val[3]
    DIRECTION INPUT ;
    USE SIGNAL ;
    PORT
      LAYER M4 ;
        RECT 345.408 98.640 345.600 98.664 ;
    END
  END a_val[3]
  PIN a_val[4]
    DIRECTION INPUT ;
    USE SIGNAL ;
    PORT
      LAYER M4 ;
        RECT 345.408 99.024 345.600 99.048 ;
    END
  END a_val[4]
  PIN a_val[5]
    DIRECTION INPUT ;
    USE SIGNAL ;
    PORT
      LAYER M4 ;
        RECT 345.408 99.360 345.600 99.384 ;
    END
  END a_val[5]
  PIN a_val[6]
    DIRECTION INPUT ;
    USE SIGNAL ;
    PORT
      LAYER M4 ;
        RECT 345.408 99.696 345.600 99.720 ;
    END
  END a_val[6]
  PIN a_val[7]
    DIRECTION INPUT ;
    USE SIGNAL ;
    PORT
      LAYER M4 ;
        RECT 345.408 100.032 345.600 100.056 ;
    END
  END a_val[7]
  PIN a_val[8]
    DIRECTION INPUT ;
    USE SIGNAL ;
    PORT
      LAYER M4 ;
        RECT 345.408 100.368 345.600 100.392 ;
    END
  END a_val[8]
  PIN a_val[9]
    DIRECTION INPUT ;
    USE SIGNAL ;
    PORT
      LAYER M4 ;
        RECT 345.408 100.704 345.600 100.728 ;
    END
  END a_val[9]
  PIN a_val[10]
    DIRECTION INPUT ;
    USE SIGNAL ;
    PORT
      LAYER M4 ;
        RECT 345.408 101.040 345.600 101.064 ;
    END
  END a_val[10]
  PIN a_val[11]
    DIRECTION INPUT ;
    USE SIGNAL ;
    PORT
      LAYER M4 ;
        RECT 345.408 101.376 345.600 101.400 ;
    END
  END a_val[11]
  PIN a_val[12]
    DIRECTION INPUT ;
    USE SIGNAL ;
    PORT
      LAYER M4 ;
        RECT 345.408 101.712 345.600 101.736 ;
    END
  END a_val[12]
  PIN a_val[13]
    DIRECTION INPUT ;
    USE SIGNAL ;
    PORT
      LAYER M4 ;
        RECT 345.408 102.048 345.600 102.072 ;
    END
  END a_val[13]
  PIN a_val[14]
    DIRECTION INPUT ;
    USE SIGNAL ;
    PORT
      LAYER M4 ;
        RECT 345.408 102.384 345.600 102.408 ;
    END
  END a_val[14]
  PIN a_val[15]
    DIRECTION INPUT ;
    USE SIGNAL ;
    PORT
      LAYER M4 ;
        RECT 345.408 102.720 345.600 102.744 ;
    END
  END a_val[15]
  PIN a_val[16]
    DIRECTION INPUT ;
    USE SIGNAL ;
    PORT
      LAYER M4 ;
        RECT 345.408 103.056 345.600 103.080 ;
    END
  END a_val[16]
  PIN a_val[17]
    DIRECTION INPUT ;
    USE SIGNAL ;
    PORT
      LAYER M4 ;
        RECT 345.408 103.392 345.600 103.416 ;
    END
  END a_val[17]
  PIN a_val[18]
    DIRECTION INPUT ;
    USE SIGNAL ;
    PORT
      LAYER M4 ;
        RECT 345.408 103.728 345.600 103.752 ;
    END
  END a_val[18]
  PIN a_val[19]
    DIRECTION INPUT ;
    USE SIGNAL ;
    PORT
      LAYER M4 ;
        RECT 345.408 104.064 345.600 104.088 ;
    END
  END a_val[19]
  PIN a_val[20]
    DIRECTION INPUT ;
    USE SIGNAL ;
    PORT
      LAYER M4 ;
        RECT 345.408 104.400 345.600 104.424 ;
    END
  END a_val[20]
  PIN a_val[21]
    DIRECTION INPUT ;
    USE SIGNAL ;
    PORT
      LAYER M4 ;
        RECT 345.408 104.736 345.600 104.760 ;
    END
  END a_val[21]
  PIN a_val[22]
    DIRECTION INPUT ;
    USE SIGNAL ;
    PORT
      LAYER M4 ;
        RECT 345.408 105.072 345.600 105.096 ;
    END
  END a_val[22]
  PIN a_val[23]
    DIRECTION INPUT ;
    USE SIGNAL ;
    PORT
      LAYER M4 ;
        RECT 345.408 105.408 345.600 105.432 ;
    END
  END a_val[23]
  PIN a_val[24]
    DIRECTION INPUT ;
    USE SIGNAL ;
    PORT
      LAYER M4 ;
        RECT 345.408 105.744 345.600 105.768 ;
    END
  END a_val[24]
  PIN a_val[25]
    DIRECTION INPUT ;
    USE SIGNAL ;
    PORT
      LAYER M4 ;
        RECT 345.408 106.080 345.600 106.104 ;
    END
  END a_val[25]
  PIN a_val[26]
    DIRECTION INPUT ;
    USE SIGNAL ;
    PORT
      LAYER M4 ;
        RECT 345.408 106.416 345.600 106.440 ;
    END
  END a_val[26]
  PIN a_val[27]
    DIRECTION INPUT ;
    USE SIGNAL ;
    PORT
      LAYER M4 ;
        RECT 345.408 106.752 345.600 106.776 ;
    END
  END a_val[27]
  PIN a_val[28]
    DIRECTION INPUT ;
    USE SIGNAL ;
    PORT
      LAYER M4 ;
        RECT 345.408 107.088 345.600 107.112 ;
    END
  END a_val[28]
  PIN a_val[29]
    DIRECTION INPUT ;
    USE SIGNAL ;
    PORT
      LAYER M4 ;
        RECT 345.408 107.424 345.600 107.448 ;
    END
  END a_val[29]
  PIN a_val[30]
    DIRECTION INPUT ;
    USE SIGNAL ;
    PORT
      LAYER M4 ;
        RECT 345.408 107.760 345.600 107.784 ;
    END
  END a_val[30]
  PIN a_val[31]
    DIRECTION INPUT ;
    USE SIGNAL ;
    PORT
      LAYER M4 ;
        RECT 345.408 108.096 345.600 108.120 ;
    END
  END a_val[31]
  PIN a_val[32]
    DIRECTION INPUT ;
    USE SIGNAL ;
    PORT
      LAYER M4 ;
        RECT 345.408 108.432 345.600 108.456 ;
    END
  END a_val[32]
  PIN a_val[33]
    DIRECTION INPUT ;
    USE SIGNAL ;
    PORT
      LAYER M4 ;
        RECT 345.408 108.768 345.600 108.792 ;
    END
  END a_val[33]
  PIN a_val[34]
    DIRECTION INPUT ;
    USE SIGNAL ;
    PORT
      LAYER M4 ;
        RECT 345.408 109.104 345.600 109.128 ;
    END
  END a_val[34]
  PIN a_val[35]
    DIRECTION INPUT ;
    USE SIGNAL ;
    PORT
      LAYER M4 ;
        RECT 345.408 109.440 345.600 109.464 ;
    END
  END a_val[35]
  PIN a_val[36]
    DIRECTION INPUT ;
    USE SIGNAL ;
    PORT
      LAYER M4 ;
        RECT 345.408 109.776 345.600 109.800 ;
    END
  END a_val[36]
  PIN a_val[37]
    DIRECTION INPUT ;
    USE SIGNAL ;
    PORT
      LAYER M4 ;
        RECT 345.408 110.160 345.600 110.184 ;
    END
  END a_val[37]
  PIN a_val[38]
    DIRECTION INPUT ;
    USE SIGNAL ;
    PORT
      LAYER M4 ;
        RECT 345.408 110.496 345.600 110.520 ;
    END
  END a_val[38]
  PIN a_val[39]
    DIRECTION INPUT ;
    USE SIGNAL ;
    PORT
      LAYER M4 ;
        RECT 345.408 110.832 345.600 110.856 ;
    END
  END a_val[39]
  PIN a_val[40]
    DIRECTION INPUT ;
    USE SIGNAL ;
    PORT
      LAYER M4 ;
        RECT 345.408 111.168 345.600 111.192 ;
    END
  END a_val[40]
  PIN a_val[41]
    DIRECTION INPUT ;
    USE SIGNAL ;
    PORT
      LAYER M4 ;
        RECT 345.408 111.504 345.600 111.528 ;
    END
  END a_val[41]
  PIN a_val[42]
    DIRECTION INPUT ;
    USE SIGNAL ;
    PORT
      LAYER M4 ;
        RECT 345.408 111.840 345.600 111.864 ;
    END
  END a_val[42]
  PIN a_val[43]
    DIRECTION INPUT ;
    USE SIGNAL ;
    PORT
      LAYER M4 ;
        RECT 345.408 112.176 345.600 112.200 ;
    END
  END a_val[43]
  PIN a_val[44]
    DIRECTION INPUT ;
    USE SIGNAL ;
    PORT
      LAYER M4 ;
        RECT 345.408 112.512 345.600 112.536 ;
    END
  END a_val[44]
  PIN a_val[45]
    DIRECTION INPUT ;
    USE SIGNAL ;
    PORT
      LAYER M4 ;
        RECT 345.408 112.848 345.600 112.872 ;
    END
  END a_val[45]
  PIN a_val[46]
    DIRECTION INPUT ;
    USE SIGNAL ;
    PORT
      LAYER M4 ;
        RECT 345.408 113.184 345.600 113.208 ;
    END
  END a_val[46]
  PIN a_val[47]
    DIRECTION INPUT ;
    USE SIGNAL ;
    PORT
      LAYER M4 ;
        RECT 345.408 113.520 345.600 113.544 ;
    END
  END a_val[47]
  PIN a_val[48]
    DIRECTION INPUT ;
    USE SIGNAL ;
    PORT
      LAYER M4 ;
        RECT 345.408 113.856 345.600 113.880 ;
    END
  END a_val[48]
  PIN a_val[49]
    DIRECTION INPUT ;
    USE SIGNAL ;
    PORT
      LAYER M4 ;
        RECT 345.408 114.192 345.600 114.216 ;
    END
  END a_val[49]
  PIN a_val[50]
    DIRECTION INPUT ;
    USE SIGNAL ;
    PORT
      LAYER M4 ;
        RECT 345.408 114.528 345.600 114.552 ;
    END
  END a_val[50]
  PIN a_val[51]
    DIRECTION INPUT ;
    USE SIGNAL ;
    PORT
      LAYER M4 ;
        RECT 345.408 114.864 345.600 114.888 ;
    END
  END a_val[51]
  PIN a_val[52]
    DIRECTION INPUT ;
    USE SIGNAL ;
    PORT
      LAYER M4 ;
        RECT 345.408 115.200 345.600 115.224 ;
    END
  END a_val[52]
  PIN a_val[53]
    DIRECTION INPUT ;
    USE SIGNAL ;
    PORT
      LAYER M4 ;
        RECT 345.408 115.536 345.600 115.560 ;
    END
  END a_val[53]
  PIN a_val[54]
    DIRECTION INPUT ;
    USE SIGNAL ;
    PORT
      LAYER M4 ;
        RECT 345.408 115.872 345.600 115.896 ;
    END
  END a_val[54]
  PIN a_val[55]
    DIRECTION INPUT ;
    USE SIGNAL ;
    PORT
      LAYER M4 ;
        RECT 345.408 116.208 345.600 116.232 ;
    END
  END a_val[55]
  PIN a_val[56]
    DIRECTION INPUT ;
    USE SIGNAL ;
    PORT
      LAYER M4 ;
        RECT 345.408 116.544 345.600 116.568 ;
    END
  END a_val[56]
  PIN a_val[57]
    DIRECTION INPUT ;
    USE SIGNAL ;
    PORT
      LAYER M4 ;
        RECT 345.408 116.880 345.600 116.904 ;
    END
  END a_val[57]
  PIN a_val[58]
    DIRECTION INPUT ;
    USE SIGNAL ;
    PORT
      LAYER M4 ;
        RECT 345.408 117.216 345.600 117.240 ;
    END
  END a_val[58]
  PIN a_val[59]
    DIRECTION INPUT ;
    USE SIGNAL ;
    PORT
      LAYER M4 ;
        RECT 345.408 117.552 345.600 117.576 ;
    END
  END a_val[59]
  PIN a_val[60]
    DIRECTION INPUT ;
    USE SIGNAL ;
    PORT
      LAYER M4 ;
        RECT 345.408 117.888 345.600 117.912 ;
    END
  END a_val[60]
  PIN a_val[61]
    DIRECTION INPUT ;
    USE SIGNAL ;
    PORT
      LAYER M4 ;
        RECT 345.408 118.224 345.600 118.248 ;
    END
  END a_val[61]
  PIN a_val[62]
    DIRECTION INPUT ;
    USE SIGNAL ;
    PORT
      LAYER M4 ;
        RECT 345.408 118.560 345.600 118.584 ;
    END
  END a_val[62]
  PIN a_val[63]
    DIRECTION INPUT ;
    USE SIGNAL ;
    PORT
      LAYER M4 ;
        RECT 345.408 118.896 345.600 118.920 ;
    END
  END a_val[63]
  PIN a_val[64]
    DIRECTION INPUT ;
    USE SIGNAL ;
    PORT
      LAYER M4 ;
        RECT 345.408 119.232 345.600 119.256 ;
    END
  END a_val[64]
  PIN a_val[65]
    DIRECTION INPUT ;
    USE SIGNAL ;
    PORT
      LAYER M4 ;
        RECT 345.408 119.568 345.600 119.592 ;
    END
  END a_val[65]
  PIN a_val[66]
    DIRECTION INPUT ;
    USE SIGNAL ;
    PORT
      LAYER M4 ;
        RECT 345.408 119.904 345.600 119.928 ;
    END
  END a_val[66]
  PIN a_val[67]
    DIRECTION INPUT ;
    USE SIGNAL ;
    PORT
      LAYER M4 ;
        RECT 345.408 120.240 345.600 120.264 ;
    END
  END a_val[67]
  PIN a_val[68]
    DIRECTION INPUT ;
    USE SIGNAL ;
    PORT
      LAYER M4 ;
        RECT 345.408 120.576 345.600 120.600 ;
    END
  END a_val[68]
  PIN a_val[69]
    DIRECTION INPUT ;
    USE SIGNAL ;
    PORT
      LAYER M4 ;
        RECT 345.408 120.912 345.600 120.936 ;
    END
  END a_val[69]
  PIN a_val[70]
    DIRECTION INPUT ;
    USE SIGNAL ;
    PORT
      LAYER M4 ;
        RECT 345.408 121.248 345.600 121.272 ;
    END
  END a_val[70]
  PIN a_val[71]
    DIRECTION INPUT ;
    USE SIGNAL ;
    PORT
      LAYER M4 ;
        RECT 345.408 121.632 345.600 121.656 ;
    END
  END a_val[71]
  PIN a_val[72]
    DIRECTION INPUT ;
    USE SIGNAL ;
    PORT
      LAYER M4 ;
        RECT 345.408 121.968 345.600 121.992 ;
    END
  END a_val[72]
  PIN a_val[73]
    DIRECTION INPUT ;
    USE SIGNAL ;
    PORT
      LAYER M4 ;
        RECT 345.408 122.304 345.600 122.328 ;
    END
  END a_val[73]
  PIN a_val[74]
    DIRECTION INPUT ;
    USE SIGNAL ;
    PORT
      LAYER M4 ;
        RECT 345.408 122.640 345.600 122.664 ;
    END
  END a_val[74]
  PIN a_val[75]
    DIRECTION INPUT ;
    USE SIGNAL ;
    PORT
      LAYER M4 ;
        RECT 345.408 122.976 345.600 123.000 ;
    END
  END a_val[75]
  PIN a_val[76]
    DIRECTION INPUT ;
    USE SIGNAL ;
    PORT
      LAYER M4 ;
        RECT 345.408 123.312 345.600 123.336 ;
    END
  END a_val[76]
  PIN a_val[77]
    DIRECTION INPUT ;
    USE SIGNAL ;
    PORT
      LAYER M4 ;
        RECT 345.408 123.648 345.600 123.672 ;
    END
  END a_val[77]
  PIN a_val[78]
    DIRECTION INPUT ;
    USE SIGNAL ;
    PORT
      LAYER M4 ;
        RECT 345.408 123.984 345.600 124.008 ;
    END
  END a_val[78]
  PIN a_val[79]
    DIRECTION INPUT ;
    USE SIGNAL ;
    PORT
      LAYER M4 ;
        RECT 345.408 124.320 345.600 124.344 ;
    END
  END a_val[79]
  PIN a_val[80]
    DIRECTION INPUT ;
    USE SIGNAL ;
    PORT
      LAYER M4 ;
        RECT 345.408 124.656 345.600 124.680 ;
    END
  END a_val[80]
  PIN a_val[81]
    DIRECTION INPUT ;
    USE SIGNAL ;
    PORT
      LAYER M4 ;
        RECT 345.408 124.992 345.600 125.016 ;
    END
  END a_val[81]
  PIN a_val[82]
    DIRECTION INPUT ;
    USE SIGNAL ;
    PORT
      LAYER M4 ;
        RECT 345.408 125.328 345.600 125.352 ;
    END
  END a_val[82]
  PIN a_val[83]
    DIRECTION INPUT ;
    USE SIGNAL ;
    PORT
      LAYER M4 ;
        RECT 345.408 125.664 345.600 125.688 ;
    END
  END a_val[83]
  PIN a_val[84]
    DIRECTION INPUT ;
    USE SIGNAL ;
    PORT
      LAYER M4 ;
        RECT 345.408 126.000 345.600 126.024 ;
    END
  END a_val[84]
  PIN a_val[85]
    DIRECTION INPUT ;
    USE SIGNAL ;
    PORT
      LAYER M4 ;
        RECT 345.408 126.336 345.600 126.360 ;
    END
  END a_val[85]
  PIN a_val[86]
    DIRECTION INPUT ;
    USE SIGNAL ;
    PORT
      LAYER M4 ;
        RECT 345.408 126.672 345.600 126.696 ;
    END
  END a_val[86]
  PIN a_val[87]
    DIRECTION INPUT ;
    USE SIGNAL ;
    PORT
      LAYER M4 ;
        RECT 345.408 127.008 345.600 127.032 ;
    END
  END a_val[87]
  PIN a_val[88]
    DIRECTION INPUT ;
    USE SIGNAL ;
    PORT
      LAYER M4 ;
        RECT 345.408 127.344 345.600 127.368 ;
    END
  END a_val[88]
  PIN a_val[89]
    DIRECTION INPUT ;
    USE SIGNAL ;
    PORT
      LAYER M4 ;
        RECT 345.408 127.680 345.600 127.704 ;
    END
  END a_val[89]
  PIN a_val[90]
    DIRECTION INPUT ;
    USE SIGNAL ;
    PORT
      LAYER M4 ;
        RECT 345.408 128.016 345.600 128.040 ;
    END
  END a_val[90]
  PIN a_val[91]
    DIRECTION INPUT ;
    USE SIGNAL ;
    PORT
      LAYER M4 ;
        RECT 345.408 128.352 345.600 128.376 ;
    END
  END a_val[91]
  PIN a_val[92]
    DIRECTION INPUT ;
    USE SIGNAL ;
    PORT
      LAYER M4 ;
        RECT 345.408 128.688 345.600 128.712 ;
    END
  END a_val[92]
  PIN a_val[93]
    DIRECTION INPUT ;
    USE SIGNAL ;
    PORT
      LAYER M4 ;
        RECT 345.408 129.024 345.600 129.048 ;
    END
  END a_val[93]
  PIN a_val[94]
    DIRECTION INPUT ;
    USE SIGNAL ;
    PORT
      LAYER M4 ;
        RECT 345.408 129.360 345.600 129.384 ;
    END
  END a_val[94]
  PIN a_val[95]
    DIRECTION INPUT ;
    USE SIGNAL ;
    PORT
      LAYER M4 ;
        RECT 345.408 129.696 345.600 129.720 ;
    END
  END a_val[95]
  PIN a_val[96]
    DIRECTION INPUT ;
    USE SIGNAL ;
    PORT
      LAYER M4 ;
        RECT 345.408 130.032 345.600 130.056 ;
    END
  END a_val[96]
  PIN a_val[97]
    DIRECTION INPUT ;
    USE SIGNAL ;
    PORT
      LAYER M4 ;
        RECT 345.408 130.368 345.600 130.392 ;
    END
  END a_val[97]
  PIN a_val[98]
    DIRECTION INPUT ;
    USE SIGNAL ;
    PORT
      LAYER M4 ;
        RECT 345.408 130.704 345.600 130.728 ;
    END
  END a_val[98]
  PIN a_val[99]
    DIRECTION INPUT ;
    USE SIGNAL ;
    PORT
      LAYER M4 ;
        RECT 345.408 131.040 345.600 131.064 ;
    END
  END a_val[99]
  PIN a_val[100]
    DIRECTION INPUT ;
    USE SIGNAL ;
    PORT
      LAYER M4 ;
        RECT 345.408 131.376 345.600 131.400 ;
    END
  END a_val[100]
  PIN a_val[101]
    DIRECTION INPUT ;
    USE SIGNAL ;
    PORT
      LAYER M4 ;
        RECT 345.408 131.712 345.600 131.736 ;
    END
  END a_val[101]
  PIN a_val[102]
    DIRECTION INPUT ;
    USE SIGNAL ;
    PORT
      LAYER M4 ;
        RECT 345.408 132.048 345.600 132.072 ;
    END
  END a_val[102]
  PIN a_val[103]
    DIRECTION INPUT ;
    USE SIGNAL ;
    PORT
      LAYER M4 ;
        RECT 345.408 132.384 345.600 132.408 ;
    END
  END a_val[103]
  PIN a_val[104]
    DIRECTION INPUT ;
    USE SIGNAL ;
    PORT
      LAYER M4 ;
        RECT 345.408 132.720 345.600 132.744 ;
    END
  END a_val[104]
  PIN a_val[105]
    DIRECTION INPUT ;
    USE SIGNAL ;
    PORT
      LAYER M4 ;
        RECT 345.408 133.104 345.600 133.128 ;
    END
  END a_val[105]
  PIN a_val[106]
    DIRECTION INPUT ;
    USE SIGNAL ;
    PORT
      LAYER M4 ;
        RECT 345.408 133.440 345.600 133.464 ;
    END
  END a_val[106]
  PIN a_val[107]
    DIRECTION INPUT ;
    USE SIGNAL ;
    PORT
      LAYER M4 ;
        RECT 345.408 133.776 345.600 133.800 ;
    END
  END a_val[107]
  PIN a_val[108]
    DIRECTION INPUT ;
    USE SIGNAL ;
    PORT
      LAYER M4 ;
        RECT 345.408 134.112 345.600 134.136 ;
    END
  END a_val[108]
  PIN a_val[109]
    DIRECTION INPUT ;
    USE SIGNAL ;
    PORT
      LAYER M4 ;
        RECT 345.408 134.448 345.600 134.472 ;
    END
  END a_val[109]
  PIN a_val[110]
    DIRECTION INPUT ;
    USE SIGNAL ;
    PORT
      LAYER M4 ;
        RECT 345.408 134.784 345.600 134.808 ;
    END
  END a_val[110]
  PIN a_val[111]
    DIRECTION INPUT ;
    USE SIGNAL ;
    PORT
      LAYER M4 ;
        RECT 345.408 135.120 345.600 135.144 ;
    END
  END a_val[111]
  PIN a_val[112]
    DIRECTION INPUT ;
    USE SIGNAL ;
    PORT
      LAYER M4 ;
        RECT 345.408 135.456 345.600 135.480 ;
    END
  END a_val[112]
  PIN a_val[113]
    DIRECTION INPUT ;
    USE SIGNAL ;
    PORT
      LAYER M4 ;
        RECT 345.408 135.792 345.600 135.816 ;
    END
  END a_val[113]
  PIN a_val[114]
    DIRECTION INPUT ;
    USE SIGNAL ;
    PORT
      LAYER M4 ;
        RECT 345.408 136.128 345.600 136.152 ;
    END
  END a_val[114]
  PIN a_val[115]
    DIRECTION INPUT ;
    USE SIGNAL ;
    PORT
      LAYER M4 ;
        RECT 345.408 136.464 345.600 136.488 ;
    END
  END a_val[115]
  PIN a_val[116]
    DIRECTION INPUT ;
    USE SIGNAL ;
    PORT
      LAYER M4 ;
        RECT 345.408 136.800 345.600 136.824 ;
    END
  END a_val[116]
  PIN a_val[117]
    DIRECTION INPUT ;
    USE SIGNAL ;
    PORT
      LAYER M4 ;
        RECT 345.408 137.136 345.600 137.160 ;
    END
  END a_val[117]
  PIN a_val[118]
    DIRECTION INPUT ;
    USE SIGNAL ;
    PORT
      LAYER M4 ;
        RECT 345.408 137.472 345.600 137.496 ;
    END
  END a_val[118]
  PIN a_val[119]
    DIRECTION INPUT ;
    USE SIGNAL ;
    PORT
      LAYER M4 ;
        RECT 345.408 137.808 345.600 137.832 ;
    END
  END a_val[119]
  PIN a_val[120]
    DIRECTION INPUT ;
    USE SIGNAL ;
    PORT
      LAYER M4 ;
        RECT 345.408 138.144 345.600 138.168 ;
    END
  END a_val[120]
  PIN a_val[121]
    DIRECTION INPUT ;
    USE SIGNAL ;
    PORT
      LAYER M4 ;
        RECT 345.408 138.480 345.600 138.504 ;
    END
  END a_val[121]
  PIN a_val[122]
    DIRECTION INPUT ;
    USE SIGNAL ;
    PORT
      LAYER M4 ;
        RECT 345.408 138.816 345.600 138.840 ;
    END
  END a_val[122]
  PIN a_val[123]
    DIRECTION INPUT ;
    USE SIGNAL ;
    PORT
      LAYER M4 ;
        RECT 345.408 139.152 345.600 139.176 ;
    END
  END a_val[123]
  PIN a_val[124]
    DIRECTION INPUT ;
    USE SIGNAL ;
    PORT
      LAYER M4 ;
        RECT 345.408 139.488 345.600 139.512 ;
    END
  END a_val[124]
  PIN a_val[125]
    DIRECTION INPUT ;
    USE SIGNAL ;
    PORT
      LAYER M4 ;
        RECT 345.408 139.824 345.600 139.848 ;
    END
  END a_val[125]
  PIN a_val[126]
    DIRECTION INPUT ;
    USE SIGNAL ;
    PORT
      LAYER M4 ;
        RECT 345.408 140.160 345.600 140.184 ;
    END
  END a_val[126]
  PIN a_val[127]
    DIRECTION INPUT ;
    USE SIGNAL ;
    PORT
      LAYER M4 ;
        RECT 345.408 140.496 345.600 140.520 ;
    END
  END a_val[127]
  PIN a_val[128]
    DIRECTION INPUT ;
    USE SIGNAL ;
    PORT
      LAYER M4 ;
        RECT 345.408 140.832 345.600 140.856 ;
    END
  END a_val[128]
  PIN a_val[129]
    DIRECTION INPUT ;
    USE SIGNAL ;
    PORT
      LAYER M4 ;
        RECT 345.408 141.168 345.600 141.192 ;
    END
  END a_val[129]
  PIN a_val[130]
    DIRECTION INPUT ;
    USE SIGNAL ;
    PORT
      LAYER M4 ;
        RECT 345.408 141.504 345.600 141.528 ;
    END
  END a_val[130]
  PIN a_val[131]
    DIRECTION INPUT ;
    USE SIGNAL ;
    PORT
      LAYER M4 ;
        RECT 345.408 141.840 345.600 141.864 ;
    END
  END a_val[131]
  PIN a_val[132]
    DIRECTION INPUT ;
    USE SIGNAL ;
    PORT
      LAYER M4 ;
        RECT 345.408 142.176 345.600 142.200 ;
    END
  END a_val[132]
  PIN a_val[133]
    DIRECTION INPUT ;
    USE SIGNAL ;
    PORT
      LAYER M4 ;
        RECT 345.408 142.512 345.600 142.536 ;
    END
  END a_val[133]
  PIN a_val[134]
    DIRECTION INPUT ;
    USE SIGNAL ;
    PORT
      LAYER M4 ;
        RECT 345.408 142.848 345.600 142.872 ;
    END
  END a_val[134]
  PIN a_val[135]
    DIRECTION INPUT ;
    USE SIGNAL ;
    PORT
      LAYER M4 ;
        RECT 345.408 143.184 345.600 143.208 ;
    END
  END a_val[135]
  PIN a_val[136]
    DIRECTION INPUT ;
    USE SIGNAL ;
    PORT
      LAYER M4 ;
        RECT 345.408 143.520 345.600 143.544 ;
    END
  END a_val[136]
  PIN a_val[137]
    DIRECTION INPUT ;
    USE SIGNAL ;
    PORT
      LAYER M4 ;
        RECT 345.408 143.856 345.600 143.880 ;
    END
  END a_val[137]
  PIN a_val[138]
    DIRECTION INPUT ;
    USE SIGNAL ;
    PORT
      LAYER M4 ;
        RECT 345.408 144.192 345.600 144.216 ;
    END
  END a_val[138]
  PIN a_val[139]
    DIRECTION INPUT ;
    USE SIGNAL ;
    PORT
      LAYER M4 ;
        RECT 345.408 144.576 345.600 144.600 ;
    END
  END a_val[139]
  PIN a_val[140]
    DIRECTION INPUT ;
    USE SIGNAL ;
    PORT
      LAYER M4 ;
        RECT 345.408 144.912 345.600 144.936 ;
    END
  END a_val[140]
  PIN a_val[141]
    DIRECTION INPUT ;
    USE SIGNAL ;
    PORT
      LAYER M4 ;
        RECT 345.408 145.248 345.600 145.272 ;
    END
  END a_val[141]
  PIN a_val[142]
    DIRECTION INPUT ;
    USE SIGNAL ;
    PORT
      LAYER M4 ;
        RECT 345.408 145.584 345.600 145.608 ;
    END
  END a_val[142]
  PIN a_val[143]
    DIRECTION INPUT ;
    USE SIGNAL ;
    PORT
      LAYER M4 ;
        RECT 345.408 145.920 345.600 145.944 ;
    END
  END a_val[143]
  PIN a_val[144]
    DIRECTION INPUT ;
    USE SIGNAL ;
    PORT
      LAYER M4 ;
        RECT 345.408 146.256 345.600 146.280 ;
    END
  END a_val[144]
  PIN a_val[145]
    DIRECTION INPUT ;
    USE SIGNAL ;
    PORT
      LAYER M4 ;
        RECT 345.408 146.592 345.600 146.616 ;
    END
  END a_val[145]
  PIN a_val[146]
    DIRECTION INPUT ;
    USE SIGNAL ;
    PORT
      LAYER M4 ;
        RECT 345.408 146.928 345.600 146.952 ;
    END
  END a_val[146]
  PIN a_val[147]
    DIRECTION INPUT ;
    USE SIGNAL ;
    PORT
      LAYER M4 ;
        RECT 345.408 147.264 345.600 147.288 ;
    END
  END a_val[147]
  PIN a_val[148]
    DIRECTION INPUT ;
    USE SIGNAL ;
    PORT
      LAYER M4 ;
        RECT 345.408 147.600 345.600 147.624 ;
    END
  END a_val[148]
  PIN a_val[149]
    DIRECTION INPUT ;
    USE SIGNAL ;
    PORT
      LAYER M4 ;
        RECT 345.408 147.936 345.600 147.960 ;
    END
  END a_val[149]
  PIN a_val[150]
    DIRECTION INPUT ;
    USE SIGNAL ;
    PORT
      LAYER M4 ;
        RECT 345.408 148.272 345.600 148.296 ;
    END
  END a_val[150]
  PIN a_val[151]
    DIRECTION INPUT ;
    USE SIGNAL ;
    PORT
      LAYER M4 ;
        RECT 345.408 148.608 345.600 148.632 ;
    END
  END a_val[151]
  PIN a_val[152]
    DIRECTION INPUT ;
    USE SIGNAL ;
    PORT
      LAYER M4 ;
        RECT 345.408 148.944 345.600 148.968 ;
    END
  END a_val[152]
  PIN a_val[153]
    DIRECTION INPUT ;
    USE SIGNAL ;
    PORT
      LAYER M4 ;
        RECT 345.408 149.280 345.600 149.304 ;
    END
  END a_val[153]
  PIN a_val[154]
    DIRECTION INPUT ;
    USE SIGNAL ;
    PORT
      LAYER M4 ;
        RECT 345.408 149.616 345.600 149.640 ;
    END
  END a_val[154]
  PIN a_val[155]
    DIRECTION INPUT ;
    USE SIGNAL ;
    PORT
      LAYER M4 ;
        RECT 345.408 149.952 345.600 149.976 ;
    END
  END a_val[155]
  PIN a_val[156]
    DIRECTION INPUT ;
    USE SIGNAL ;
    PORT
      LAYER M4 ;
        RECT 345.408 150.288 345.600 150.312 ;
    END
  END a_val[156]
  PIN a_val[157]
    DIRECTION INPUT ;
    USE SIGNAL ;
    PORT
      LAYER M4 ;
        RECT 345.408 150.624 345.600 150.648 ;
    END
  END a_val[157]
  PIN a_val[158]
    DIRECTION INPUT ;
    USE SIGNAL ;
    PORT
      LAYER M4 ;
        RECT 345.408 150.960 345.600 150.984 ;
    END
  END a_val[158]
  PIN a_val[159]
    DIRECTION INPUT ;
    USE SIGNAL ;
    PORT
      LAYER M4 ;
        RECT 345.408 151.296 345.600 151.320 ;
    END
  END a_val[159]
  PIN a_val[160]
    DIRECTION INPUT ;
    USE SIGNAL ;
    PORT
      LAYER M4 ;
        RECT 345.408 151.632 345.600 151.656 ;
    END
  END a_val[160]
  PIN a_val[161]
    DIRECTION INPUT ;
    USE SIGNAL ;
    PORT
      LAYER M4 ;
        RECT 345.408 151.968 345.600 151.992 ;
    END
  END a_val[161]
  PIN a_val[162]
    DIRECTION INPUT ;
    USE SIGNAL ;
    PORT
      LAYER M4 ;
        RECT 345.408 152.304 345.600 152.328 ;
    END
  END a_val[162]
  PIN a_val[163]
    DIRECTION INPUT ;
    USE SIGNAL ;
    PORT
      LAYER M4 ;
        RECT 345.408 152.640 345.600 152.664 ;
    END
  END a_val[163]
  PIN a_val[164]
    DIRECTION INPUT ;
    USE SIGNAL ;
    PORT
      LAYER M4 ;
        RECT 345.408 152.976 345.600 153.000 ;
    END
  END a_val[164]
  PIN a_val[165]
    DIRECTION INPUT ;
    USE SIGNAL ;
    PORT
      LAYER M4 ;
        RECT 345.408 153.312 345.600 153.336 ;
    END
  END a_val[165]
  PIN a_val[166]
    DIRECTION INPUT ;
    USE SIGNAL ;
    PORT
      LAYER M4 ;
        RECT 345.408 153.648 345.600 153.672 ;
    END
  END a_val[166]
  PIN a_val[167]
    DIRECTION INPUT ;
    USE SIGNAL ;
    PORT
      LAYER M4 ;
        RECT 345.408 153.984 345.600 154.008 ;
    END
  END a_val[167]
  PIN a_val[168]
    DIRECTION INPUT ;
    USE SIGNAL ;
    PORT
      LAYER M4 ;
        RECT 345.408 154.320 345.600 154.344 ;
    END
  END a_val[168]
  PIN a_val[169]
    DIRECTION INPUT ;
    USE SIGNAL ;
    PORT
      LAYER M4 ;
        RECT 345.408 154.656 345.600 154.680 ;
    END
  END a_val[169]
  PIN a_val[170]
    DIRECTION INPUT ;
    USE SIGNAL ;
    PORT
      LAYER M4 ;
        RECT 345.408 154.992 345.600 155.016 ;
    END
  END a_val[170]
  PIN a_val[171]
    DIRECTION INPUT ;
    USE SIGNAL ;
    PORT
      LAYER M4 ;
        RECT 345.408 155.328 345.600 155.352 ;
    END
  END a_val[171]
  PIN a_val[172]
    DIRECTION INPUT ;
    USE SIGNAL ;
    PORT
      LAYER M4 ;
        RECT 345.408 155.664 345.600 155.688 ;
    END
  END a_val[172]
  PIN a_val[173]
    DIRECTION INPUT ;
    USE SIGNAL ;
    PORT
      LAYER M4 ;
        RECT 345.408 156.048 345.600 156.072 ;
    END
  END a_val[173]
  PIN a_val[174]
    DIRECTION INPUT ;
    USE SIGNAL ;
    PORT
      LAYER M4 ;
        RECT 345.408 156.384 345.600 156.408 ;
    END
  END a_val[174]
  PIN a_val[175]
    DIRECTION INPUT ;
    USE SIGNAL ;
    PORT
      LAYER M4 ;
        RECT 345.408 156.720 345.600 156.744 ;
    END
  END a_val[175]
  PIN a_val[176]
    DIRECTION INPUT ;
    USE SIGNAL ;
    PORT
      LAYER M4 ;
        RECT 345.408 157.056 345.600 157.080 ;
    END
  END a_val[176]
  PIN a_val[177]
    DIRECTION INPUT ;
    USE SIGNAL ;
    PORT
      LAYER M4 ;
        RECT 345.408 157.392 345.600 157.416 ;
    END
  END a_val[177]
  PIN a_val[178]
    DIRECTION INPUT ;
    USE SIGNAL ;
    PORT
      LAYER M4 ;
        RECT 345.408 157.728 345.600 157.752 ;
    END
  END a_val[178]
  PIN a_val[179]
    DIRECTION INPUT ;
    USE SIGNAL ;
    PORT
      LAYER M4 ;
        RECT 345.408 158.064 345.600 158.088 ;
    END
  END a_val[179]
  PIN a_val[180]
    DIRECTION INPUT ;
    USE SIGNAL ;
    PORT
      LAYER M4 ;
        RECT 345.408 158.400 345.600 158.424 ;
    END
  END a_val[180]
  PIN a_val[181]
    DIRECTION INPUT ;
    USE SIGNAL ;
    PORT
      LAYER M4 ;
        RECT 345.408 158.736 345.600 158.760 ;
    END
  END a_val[181]
  PIN a_val[182]
    DIRECTION INPUT ;
    USE SIGNAL ;
    PORT
      LAYER M4 ;
        RECT 345.408 159.072 345.600 159.096 ;
    END
  END a_val[182]
  PIN a_val[183]
    DIRECTION INPUT ;
    USE SIGNAL ;
    PORT
      LAYER M4 ;
        RECT 345.408 159.408 345.600 159.432 ;
    END
  END a_val[183]
  PIN a_val[184]
    DIRECTION INPUT ;
    USE SIGNAL ;
    PORT
      LAYER M4 ;
        RECT 345.408 159.744 345.600 159.768 ;
    END
  END a_val[184]
  PIN a_val[185]
    DIRECTION INPUT ;
    USE SIGNAL ;
    PORT
      LAYER M4 ;
        RECT 345.408 160.080 345.600 160.104 ;
    END
  END a_val[185]
  PIN a_val[186]
    DIRECTION INPUT ;
    USE SIGNAL ;
    PORT
      LAYER M4 ;
        RECT 345.408 160.416 345.600 160.440 ;
    END
  END a_val[186]
  PIN a_val[187]
    DIRECTION INPUT ;
    USE SIGNAL ;
    PORT
      LAYER M4 ;
        RECT 345.408 160.752 345.600 160.776 ;
    END
  END a_val[187]
  PIN a_val[188]
    DIRECTION INPUT ;
    USE SIGNAL ;
    PORT
      LAYER M4 ;
        RECT 345.408 161.088 345.600 161.112 ;
    END
  END a_val[188]
  PIN a_val[189]
    DIRECTION INPUT ;
    USE SIGNAL ;
    PORT
      LAYER M4 ;
        RECT 345.408 161.424 345.600 161.448 ;
    END
  END a_val[189]
  PIN a_val[190]
    DIRECTION INPUT ;
    USE SIGNAL ;
    PORT
      LAYER M4 ;
        RECT 345.408 161.760 345.600 161.784 ;
    END
  END a_val[190]
  PIN a_val[191]
    DIRECTION INPUT ;
    USE SIGNAL ;
    PORT
      LAYER M4 ;
        RECT 345.408 162.096 345.600 162.120 ;
    END
  END a_val[191]
  PIN a_val[192]
    DIRECTION INPUT ;
    USE SIGNAL ;
    PORT
      LAYER M4 ;
        RECT 345.408 162.432 345.600 162.456 ;
    END
  END a_val[192]
  PIN a_val[193]
    DIRECTION INPUT ;
    USE SIGNAL ;
    PORT
      LAYER M4 ;
        RECT 345.408 162.768 345.600 162.792 ;
    END
  END a_val[193]
  PIN a_val[194]
    DIRECTION INPUT ;
    USE SIGNAL ;
    PORT
      LAYER M4 ;
        RECT 345.408 163.104 345.600 163.128 ;
    END
  END a_val[194]
  PIN a_val[195]
    DIRECTION INPUT ;
    USE SIGNAL ;
    PORT
      LAYER M4 ;
        RECT 345.408 163.440 345.600 163.464 ;
    END
  END a_val[195]
  PIN a_val[196]
    DIRECTION INPUT ;
    USE SIGNAL ;
    PORT
      LAYER M4 ;
        RECT 345.408 163.776 345.600 163.800 ;
    END
  END a_val[196]
  PIN a_val[197]
    DIRECTION INPUT ;
    USE SIGNAL ;
    PORT
      LAYER M4 ;
        RECT 345.408 164.112 345.600 164.136 ;
    END
  END a_val[197]
  PIN a_val[198]
    DIRECTION INPUT ;
    USE SIGNAL ;
    PORT
      LAYER M4 ;
        RECT 345.408 164.448 345.600 164.472 ;
    END
  END a_val[198]
  PIN a_val[199]
    DIRECTION INPUT ;
    USE SIGNAL ;
    PORT
      LAYER M4 ;
        RECT 345.408 164.784 345.600 164.808 ;
    END
  END a_val[199]
  PIN a_val[200]
    DIRECTION INPUT ;
    USE SIGNAL ;
    PORT
      LAYER M4 ;
        RECT 345.408 165.120 345.600 165.144 ;
    END
  END a_val[200]
  PIN a_val[201]
    DIRECTION INPUT ;
    USE SIGNAL ;
    PORT
      LAYER M4 ;
        RECT 345.408 165.456 345.600 165.480 ;
    END
  END a_val[201]
  PIN a_val[202]
    DIRECTION INPUT ;
    USE SIGNAL ;
    PORT
      LAYER M4 ;
        RECT 345.408 165.792 345.600 165.816 ;
    END
  END a_val[202]
  PIN a_val[203]
    DIRECTION INPUT ;
    USE SIGNAL ;
    PORT
      LAYER M4 ;
        RECT 345.408 166.128 345.600 166.152 ;
    END
  END a_val[203]
  PIN a_val[204]
    DIRECTION INPUT ;
    USE SIGNAL ;
    PORT
      LAYER M4 ;
        RECT 345.408 166.464 345.600 166.488 ;
    END
  END a_val[204]
  PIN a_val[205]
    DIRECTION INPUT ;
    USE SIGNAL ;
    PORT
      LAYER M4 ;
        RECT 345.408 166.800 345.600 166.824 ;
    END
  END a_val[205]
  PIN a_val[206]
    DIRECTION INPUT ;
    USE SIGNAL ;
    PORT
      LAYER M4 ;
        RECT 345.408 167.136 345.600 167.160 ;
    END
  END a_val[206]
  PIN a_val[207]
    DIRECTION INPUT ;
    USE SIGNAL ;
    PORT
      LAYER M4 ;
        RECT 345.408 167.520 345.600 167.544 ;
    END
  END a_val[207]
  PIN a_val[208]
    DIRECTION INPUT ;
    USE SIGNAL ;
    PORT
      LAYER M4 ;
        RECT 345.408 167.856 345.600 167.880 ;
    END
  END a_val[208]
  PIN a_val[209]
    DIRECTION INPUT ;
    USE SIGNAL ;
    PORT
      LAYER M4 ;
        RECT 345.408 168.192 345.600 168.216 ;
    END
  END a_val[209]
  PIN a_val[210]
    DIRECTION INPUT ;
    USE SIGNAL ;
    PORT
      LAYER M4 ;
        RECT 345.408 168.528 345.600 168.552 ;
    END
  END a_val[210]
  PIN a_val[211]
    DIRECTION INPUT ;
    USE SIGNAL ;
    PORT
      LAYER M4 ;
        RECT 345.408 168.864 345.600 168.888 ;
    END
  END a_val[211]
  PIN a_val[212]
    DIRECTION INPUT ;
    USE SIGNAL ;
    PORT
      LAYER M4 ;
        RECT 345.408 169.200 345.600 169.224 ;
    END
  END a_val[212]
  PIN a_val[213]
    DIRECTION INPUT ;
    USE SIGNAL ;
    PORT
      LAYER M4 ;
        RECT 345.408 169.536 345.600 169.560 ;
    END
  END a_val[213]
  PIN a_val[214]
    DIRECTION INPUT ;
    USE SIGNAL ;
    PORT
      LAYER M4 ;
        RECT 345.408 169.872 345.600 169.896 ;
    END
  END a_val[214]
  PIN a_val[215]
    DIRECTION INPUT ;
    USE SIGNAL ;
    PORT
      LAYER M4 ;
        RECT 345.408 170.208 345.600 170.232 ;
    END
  END a_val[215]
  PIN a_val[216]
    DIRECTION INPUT ;
    USE SIGNAL ;
    PORT
      LAYER M4 ;
        RECT 345.408 170.544 345.600 170.568 ;
    END
  END a_val[216]
  PIN a_val[217]
    DIRECTION INPUT ;
    USE SIGNAL ;
    PORT
      LAYER M4 ;
        RECT 345.408 170.880 345.600 170.904 ;
    END
  END a_val[217]
  PIN a_val[218]
    DIRECTION INPUT ;
    USE SIGNAL ;
    PORT
      LAYER M4 ;
        RECT 345.408 171.216 345.600 171.240 ;
    END
  END a_val[218]
  PIN a_val[219]
    DIRECTION INPUT ;
    USE SIGNAL ;
    PORT
      LAYER M4 ;
        RECT 345.408 171.552 345.600 171.576 ;
    END
  END a_val[219]
  PIN a_val[220]
    DIRECTION INPUT ;
    USE SIGNAL ;
    PORT
      LAYER M4 ;
        RECT 345.408 171.888 345.600 171.912 ;
    END
  END a_val[220]
  PIN a_val[221]
    DIRECTION INPUT ;
    USE SIGNAL ;
    PORT
      LAYER M4 ;
        RECT 345.408 172.224 345.600 172.248 ;
    END
  END a_val[221]
  PIN a_val[222]
    DIRECTION INPUT ;
    USE SIGNAL ;
    PORT
      LAYER M4 ;
        RECT 345.408 172.560 345.600 172.584 ;
    END
  END a_val[222]
  PIN a_val[223]
    DIRECTION INPUT ;
    USE SIGNAL ;
    PORT
      LAYER M4 ;
        RECT 345.408 172.896 345.600 172.920 ;
    END
  END a_val[223]
  PIN a_val[224]
    DIRECTION INPUT ;
    USE SIGNAL ;
    PORT
      LAYER M4 ;
        RECT 345.408 173.232 345.600 173.256 ;
    END
  END a_val[224]
  PIN a_val[225]
    DIRECTION INPUT ;
    USE SIGNAL ;
    PORT
      LAYER M4 ;
        RECT 345.408 173.568 345.600 173.592 ;
    END
  END a_val[225]
  PIN a_val[226]
    DIRECTION INPUT ;
    USE SIGNAL ;
    PORT
      LAYER M4 ;
        RECT 345.408 173.904 345.600 173.928 ;
    END
  END a_val[226]
  PIN a_val[227]
    DIRECTION INPUT ;
    USE SIGNAL ;
    PORT
      LAYER M4 ;
        RECT 345.408 174.240 345.600 174.264 ;
    END
  END a_val[227]
  PIN a_val[228]
    DIRECTION INPUT ;
    USE SIGNAL ;
    PORT
      LAYER M4 ;
        RECT 345.408 174.576 345.600 174.600 ;
    END
  END a_val[228]
  PIN a_val[229]
    DIRECTION INPUT ;
    USE SIGNAL ;
    PORT
      LAYER M4 ;
        RECT 345.408 174.912 345.600 174.936 ;
    END
  END a_val[229]
  PIN a_val[230]
    DIRECTION INPUT ;
    USE SIGNAL ;
    PORT
      LAYER M4 ;
        RECT 345.408 175.248 345.600 175.272 ;
    END
  END a_val[230]
  PIN a_val[231]
    DIRECTION INPUT ;
    USE SIGNAL ;
    PORT
      LAYER M4 ;
        RECT 345.408 175.584 345.600 175.608 ;
    END
  END a_val[231]
  PIN a_val[232]
    DIRECTION INPUT ;
    USE SIGNAL ;
    PORT
      LAYER M4 ;
        RECT 345.408 175.920 345.600 175.944 ;
    END
  END a_val[232]
  PIN a_val[233]
    DIRECTION INPUT ;
    USE SIGNAL ;
    PORT
      LAYER M4 ;
        RECT 345.408 176.256 345.600 176.280 ;
    END
  END a_val[233]
  PIN a_val[234]
    DIRECTION INPUT ;
    USE SIGNAL ;
    PORT
      LAYER M4 ;
        RECT 345.408 176.592 345.600 176.616 ;
    END
  END a_val[234]
  PIN a_val[235]
    DIRECTION INPUT ;
    USE SIGNAL ;
    PORT
      LAYER M4 ;
        RECT 345.408 176.928 345.600 176.952 ;
    END
  END a_val[235]
  PIN a_val[236]
    DIRECTION INPUT ;
    USE SIGNAL ;
    PORT
      LAYER M4 ;
        RECT 345.408 177.264 345.600 177.288 ;
    END
  END a_val[236]
  PIN a_val[237]
    DIRECTION INPUT ;
    USE SIGNAL ;
    PORT
      LAYER M4 ;
        RECT 345.408 177.600 345.600 177.624 ;
    END
  END a_val[237]
  PIN a_val[238]
    DIRECTION INPUT ;
    USE SIGNAL ;
    PORT
      LAYER M4 ;
        RECT 345.408 177.936 345.600 177.960 ;
    END
  END a_val[238]
  PIN a_val[239]
    DIRECTION INPUT ;
    USE SIGNAL ;
    PORT
      LAYER M4 ;
        RECT 345.408 178.272 345.600 178.296 ;
    END
  END a_val[239]
  PIN a_val[240]
    DIRECTION INPUT ;
    USE SIGNAL ;
    PORT
      LAYER M4 ;
        RECT 345.408 178.608 345.600 178.632 ;
    END
  END a_val[240]
  PIN a_val[241]
    DIRECTION INPUT ;
    USE SIGNAL ;
    PORT
      LAYER M4 ;
        RECT 345.408 178.992 345.600 179.016 ;
    END
  END a_val[241]
  PIN a_val[242]
    DIRECTION INPUT ;
    USE SIGNAL ;
    PORT
      LAYER M4 ;
        RECT 345.408 179.328 345.600 179.352 ;
    END
  END a_val[242]
  PIN a_val[243]
    DIRECTION INPUT ;
    USE SIGNAL ;
    PORT
      LAYER M4 ;
        RECT 345.408 179.664 345.600 179.688 ;
    END
  END a_val[243]
  PIN a_val[244]
    DIRECTION INPUT ;
    USE SIGNAL ;
    PORT
      LAYER M4 ;
        RECT 345.408 180.000 345.600 180.024 ;
    END
  END a_val[244]
  PIN a_val[245]
    DIRECTION INPUT ;
    USE SIGNAL ;
    PORT
      LAYER M4 ;
        RECT 345.408 180.336 345.600 180.360 ;
    END
  END a_val[245]
  PIN a_val[246]
    DIRECTION INPUT ;
    USE SIGNAL ;
    PORT
      LAYER M4 ;
        RECT 345.408 180.672 345.600 180.696 ;
    END
  END a_val[246]
  PIN a_val[247]
    DIRECTION INPUT ;
    USE SIGNAL ;
    PORT
      LAYER M4 ;
        RECT 345.408 181.008 345.600 181.032 ;
    END
  END a_val[247]
  PIN a_val[248]
    DIRECTION INPUT ;
    USE SIGNAL ;
    PORT
      LAYER M4 ;
        RECT 345.408 181.344 345.600 181.368 ;
    END
  END a_val[248]
  PIN a_val[249]
    DIRECTION INPUT ;
    USE SIGNAL ;
    PORT
      LAYER M4 ;
        RECT 345.408 181.680 345.600 181.704 ;
    END
  END a_val[249]
  PIN a_val[250]
    DIRECTION INPUT ;
    USE SIGNAL ;
    PORT
      LAYER M4 ;
        RECT 345.408 182.016 345.600 182.040 ;
    END
  END a_val[250]
  PIN a_val[251]
    DIRECTION INPUT ;
    USE SIGNAL ;
    PORT
      LAYER M4 ;
        RECT 345.408 182.352 345.600 182.376 ;
    END
  END a_val[251]
  PIN a_val[252]
    DIRECTION INPUT ;
    USE SIGNAL ;
    PORT
      LAYER M4 ;
        RECT 345.408 182.688 345.600 182.712 ;
    END
  END a_val[252]
  PIN a_val[253]
    DIRECTION INPUT ;
    USE SIGNAL ;
    PORT
      LAYER M4 ;
        RECT 345.408 183.024 345.600 183.048 ;
    END
  END a_val[253]
  PIN a_val[254]
    DIRECTION INPUT ;
    USE SIGNAL ;
    PORT
      LAYER M4 ;
        RECT 345.408 183.360 345.600 183.384 ;
    END
  END a_val[254]
  PIN a_val[255]
    DIRECTION INPUT ;
    USE SIGNAL ;
    PORT
      LAYER M4 ;
        RECT 345.408 183.696 345.600 183.720 ;
    END
  END a_val[255]
  PIN a_g[0]
    DIRECTION INPUT ;
    USE SIGNAL ;
    PORT
      LAYER M4 ;
        RECT 345.408 184.032 345.600 184.056 ;
    END
  END a_g[0]
  PIN a_g[1]
    DIRECTION INPUT ;
    USE SIGNAL ;
    PORT
      LAYER M4 ;
        RECT 345.408 184.464 345.600 184.488 ;
    END
  END a_g[1]
  PIN a_g[2]
    DIRECTION INPUT ;
    USE SIGNAL ;
    PORT
      LAYER M4 ;
        RECT 345.408 184.848 345.600 184.872 ;
    END
  END a_g[2]
  PIN a_g[3]
    DIRECTION INPUT ;
    USE SIGNAL ;
    PORT
      LAYER M4 ;
        RECT 345.408 185.232 345.600 185.256 ;
    END
  END a_g[3]
  PIN a_g[4]
    DIRECTION INPUT ;
    USE SIGNAL ;
    PORT
      LAYER M4 ;
        RECT 345.408 185.616 345.600 185.640 ;
    END
  END a_g[4]
  PIN a_g[5]
    DIRECTION INPUT ;
    USE SIGNAL ;
    PORT
      LAYER M4 ;
        RECT 345.408 186.000 345.600 186.024 ;
    END
  END a_g[5]
  PIN a_g[6]
    DIRECTION INPUT ;
    USE SIGNAL ;
    PORT
      LAYER M4 ;
        RECT 345.408 186.384 345.600 186.408 ;
    END
  END a_g[6]
  PIN a_g[7]
    DIRECTION INPUT ;
    USE SIGNAL ;
    PORT
      LAYER M4 ;
        RECT 345.408 186.768 345.600 186.792 ;
    END
  END a_g[7]
  PIN a_g[8]
    DIRECTION INPUT ;
    USE SIGNAL ;
    PORT
      LAYER M4 ;
        RECT 345.408 187.152 345.600 187.176 ;
    END
  END a_g[8]
  PIN a_g[9]
    DIRECTION INPUT ;
    USE SIGNAL ;
    PORT
      LAYER M4 ;
        RECT 345.408 187.536 345.600 187.560 ;
    END
  END a_g[9]
  PIN a_g[10]
    DIRECTION INPUT ;
    USE SIGNAL ;
    PORT
      LAYER M4 ;
        RECT 345.408 187.920 345.600 187.944 ;
    END
  END a_g[10]
  PIN a_g[11]
    DIRECTION INPUT ;
    USE SIGNAL ;
    PORT
      LAYER M4 ;
        RECT 345.408 188.304 345.600 188.328 ;
    END
  END a_g[11]
  PIN a_g[12]
    DIRECTION INPUT ;
    USE SIGNAL ;
    PORT
      LAYER M4 ;
        RECT 345.408 188.688 345.600 188.712 ;
    END
  END a_g[12]
  PIN a_g[13]
    DIRECTION INPUT ;
    USE SIGNAL ;
    PORT
      LAYER M4 ;
        RECT 345.408 189.072 345.600 189.096 ;
    END
  END a_g[13]
  PIN a_g[14]
    DIRECTION INPUT ;
    USE SIGNAL ;
    PORT
      LAYER M4 ;
        RECT 345.408 189.456 345.600 189.480 ;
    END
  END a_g[14]
  PIN a_g[15]
    DIRECTION INPUT ;
    USE SIGNAL ;
    PORT
      LAYER M4 ;
        RECT 345.408 189.840 345.600 189.864 ;
    END
  END a_g[15]
  PIN a_g[16]
    DIRECTION INPUT ;
    USE SIGNAL ;
    PORT
      LAYER M4 ;
        RECT 345.408 190.272 345.600 190.296 ;
    END
  END a_g[16]
  PIN a_g[17]
    DIRECTION INPUT ;
    USE SIGNAL ;
    PORT
      LAYER M4 ;
        RECT 345.408 190.656 345.600 190.680 ;
    END
  END a_g[17]
  PIN a_g[18]
    DIRECTION INPUT ;
    USE SIGNAL ;
    PORT
      LAYER M4 ;
        RECT 345.408 191.040 345.600 191.064 ;
    END
  END a_g[18]
  PIN a_g[19]
    DIRECTION INPUT ;
    USE SIGNAL ;
    PORT
      LAYER M4 ;
        RECT 345.408 191.424 345.600 191.448 ;
    END
  END a_g[19]
  PIN a_g[20]
    DIRECTION INPUT ;
    USE SIGNAL ;
    PORT
      LAYER M4 ;
        RECT 345.408 191.808 345.600 191.832 ;
    END
  END a_g[20]
  PIN a_g[21]
    DIRECTION INPUT ;
    USE SIGNAL ;
    PORT
      LAYER M4 ;
        RECT 345.408 192.192 345.600 192.216 ;
    END
  END a_g[21]
  PIN a_g[22]
    DIRECTION INPUT ;
    USE SIGNAL ;
    PORT
      LAYER M4 ;
        RECT 345.408 192.576 345.600 192.600 ;
    END
  END a_g[22]
  PIN a_g[23]
    DIRECTION INPUT ;
    USE SIGNAL ;
    PORT
      LAYER M4 ;
        RECT 345.408 192.960 345.600 192.984 ;
    END
  END a_g[23]
  PIN a_g[24]
    DIRECTION INPUT ;
    USE SIGNAL ;
    PORT
      LAYER M4 ;
        RECT 345.408 193.344 345.600 193.368 ;
    END
  END a_g[24]
  PIN a_g[25]
    DIRECTION INPUT ;
    USE SIGNAL ;
    PORT
      LAYER M4 ;
        RECT 345.408 193.728 345.600 193.752 ;
    END
  END a_g[25]
  PIN a_g[26]
    DIRECTION INPUT ;
    USE SIGNAL ;
    PORT
      LAYER M4 ;
        RECT 345.408 194.112 345.600 194.136 ;
    END
  END a_g[26]
  PIN a_g[27]
    DIRECTION INPUT ;
    USE SIGNAL ;
    PORT
      LAYER M4 ;
        RECT 345.408 194.496 345.600 194.520 ;
    END
  END a_g[27]
  PIN a_g[28]
    DIRECTION INPUT ;
    USE SIGNAL ;
    PORT
      LAYER M4 ;
        RECT 345.408 194.880 345.600 194.904 ;
    END
  END a_g[28]
  PIN a_g[29]
    DIRECTION INPUT ;
    USE SIGNAL ;
    PORT
      LAYER M4 ;
        RECT 345.408 195.264 345.600 195.288 ;
    END
  END a_g[29]
  PIN a_g[30]
    DIRECTION INPUT ;
    USE SIGNAL ;
    PORT
      LAYER M4 ;
        RECT 345.408 195.696 345.600 195.720 ;
    END
  END a_g[30]
  PIN a_g[31]
    DIRECTION INPUT ;
    USE SIGNAL ;
    PORT
      LAYER M4 ;
        RECT 345.408 196.080 345.600 196.104 ;
    END
  END a_g[31]
  PIN o_v
    DIRECTION OUTPUT ;
    USE SIGNAL ;
    PORT
      LAYER M4 ;
        RECT 345.408 197.328 345.600 197.352 ;
    END
  END o_v
  PIN o_c[0]
    DIRECTION OUTPUT ;
    USE SIGNAL ;
    PORT
      LAYER M4 ;
        RECT 345.408 199.008 345.600 199.032 ;
    END
  END o_c[0]
  PIN o_c[1]
    DIRECTION OUTPUT ;
    USE SIGNAL ;
    PORT
      LAYER M4 ;
        RECT 345.408 200.256 345.600 200.280 ;
    END
  END o_c[1]
  PIN o_y[0]
    DIRECTION OUTPUT ;
    USE SIGNAL ;
    PORT
      LAYER M4 ;
        RECT 345.408 201.072 345.600 201.096 ;
    END
  END o_y[0]
  PIN o_y[1]
    DIRECTION OUTPUT ;
    USE SIGNAL ;
    PORT
      LAYER M4 ;
        RECT 345.408 201.408 345.600 201.432 ;
    END
  END o_y[1]
  PIN o_y[2]
    DIRECTION OUTPUT ;
    USE SIGNAL ;
    PORT
      LAYER M4 ;
        RECT 345.408 201.744 345.600 201.768 ;
    END
  END o_y[2]
  PIN o_y[3]
    DIRECTION OUTPUT ;
    USE SIGNAL ;
    PORT
      LAYER M4 ;
        RECT 345.408 202.080 345.600 202.104 ;
    END
  END o_y[3]
  PIN o_y[4]
    DIRECTION OUTPUT ;
    USE SIGNAL ;
    PORT
      LAYER M4 ;
        RECT 345.408 202.416 345.600 202.440 ;
    END
  END o_y[4]
  PIN o_y[5]
    DIRECTION OUTPUT ;
    USE SIGNAL ;
    PORT
      LAYER M4 ;
        RECT 345.408 202.752 345.600 202.776 ;
    END
  END o_y[5]
  PIN o_y[6]
    DIRECTION OUTPUT ;
    USE SIGNAL ;
    PORT
      LAYER M4 ;
        RECT 345.408 203.088 345.600 203.112 ;
    END
  END o_y[6]
  PIN o_y[7]
    DIRECTION OUTPUT ;
    USE SIGNAL ;
    PORT
      LAYER M4 ;
        RECT 345.408 203.424 345.600 203.448 ;
    END
  END o_y[7]
  PIN o_y[8]
    DIRECTION OUTPUT ;
    USE SIGNAL ;
    PORT
      LAYER M4 ;
        RECT 345.408 203.760 345.600 203.784 ;
    END
  END o_y[8]
  PIN o_y[9]
    DIRECTION OUTPUT ;
    USE SIGNAL ;
    PORT
      LAYER M4 ;
        RECT 345.408 204.096 345.600 204.120 ;
    END
  END o_y[9]
  PIN o_y[10]
    DIRECTION OUTPUT ;
    USE SIGNAL ;
    PORT
      LAYER M4 ;
        RECT 345.408 204.432 345.600 204.456 ;
    END
  END o_y[10]
  PIN o_y[11]
    DIRECTION OUTPUT ;
    USE SIGNAL ;
    PORT
      LAYER M4 ;
        RECT 345.408 204.768 345.600 204.792 ;
    END
  END o_y[11]
  PIN o_y[12]
    DIRECTION OUTPUT ;
    USE SIGNAL ;
    PORT
      LAYER M4 ;
        RECT 345.408 205.104 345.600 205.128 ;
    END
  END o_y[12]
  PIN o_y[13]
    DIRECTION OUTPUT ;
    USE SIGNAL ;
    PORT
      LAYER M4 ;
        RECT 345.408 205.440 345.600 205.464 ;
    END
  END o_y[13]
  PIN o_y[14]
    DIRECTION OUTPUT ;
    USE SIGNAL ;
    PORT
      LAYER M4 ;
        RECT 345.408 205.776 345.600 205.800 ;
    END
  END o_y[14]
  PIN o_y[15]
    DIRECTION OUTPUT ;
    USE SIGNAL ;
    PORT
      LAYER M4 ;
        RECT 345.408 206.112 345.600 206.136 ;
    END
  END o_y[15]
  PIN o_y[16]
    DIRECTION OUTPUT ;
    USE SIGNAL ;
    PORT
      LAYER M4 ;
        RECT 345.408 206.448 345.600 206.472 ;
    END
  END o_y[16]
  PIN o_y[17]
    DIRECTION OUTPUT ;
    USE SIGNAL ;
    PORT
      LAYER M4 ;
        RECT 345.408 206.784 345.600 206.808 ;
    END
  END o_y[17]
  PIN o_y[18]
    DIRECTION OUTPUT ;
    USE SIGNAL ;
    PORT
      LAYER M4 ;
        RECT 345.408 207.120 345.600 207.144 ;
    END
  END o_y[18]
  PIN o_y[19]
    DIRECTION OUTPUT ;
    USE SIGNAL ;
    PORT
      LAYER M4 ;
        RECT 345.408 207.456 345.600 207.480 ;
    END
  END o_y[19]
  PIN o_y[20]
    DIRECTION OUTPUT ;
    USE SIGNAL ;
    PORT
      LAYER M4 ;
        RECT 345.408 207.792 345.600 207.816 ;
    END
  END o_y[20]
  PIN o_y[21]
    DIRECTION OUTPUT ;
    USE SIGNAL ;
    PORT
      LAYER M4 ;
        RECT 345.408 208.128 345.600 208.152 ;
    END
  END o_y[21]
  PIN o_y[22]
    DIRECTION OUTPUT ;
    USE SIGNAL ;
    PORT
      LAYER M4 ;
        RECT 345.408 208.464 345.600 208.488 ;
    END
  END o_y[22]
  PIN o_y[23]
    DIRECTION OUTPUT ;
    USE SIGNAL ;
    PORT
      LAYER M4 ;
        RECT 345.408 208.800 345.600 208.824 ;
    END
  END o_y[23]
  PIN o_y[24]
    DIRECTION OUTPUT ;
    USE SIGNAL ;
    PORT
      LAYER M4 ;
        RECT 345.408 209.136 345.600 209.160 ;
    END
  END o_y[24]
  PIN o_y[25]
    DIRECTION OUTPUT ;
    USE SIGNAL ;
    PORT
      LAYER M4 ;
        RECT 345.408 209.472 345.600 209.496 ;
    END
  END o_y[25]
  PIN o_y[26]
    DIRECTION OUTPUT ;
    USE SIGNAL ;
    PORT
      LAYER M4 ;
        RECT 345.408 209.856 345.600 209.880 ;
    END
  END o_y[26]
  PIN o_y[27]
    DIRECTION OUTPUT ;
    USE SIGNAL ;
    PORT
      LAYER M4 ;
        RECT 345.408 210.192 345.600 210.216 ;
    END
  END o_y[27]
  PIN o_y[28]
    DIRECTION OUTPUT ;
    USE SIGNAL ;
    PORT
      LAYER M4 ;
        RECT 345.408 210.528 345.600 210.552 ;
    END
  END o_y[28]
  PIN o_y[29]
    DIRECTION OUTPUT ;
    USE SIGNAL ;
    PORT
      LAYER M4 ;
        RECT 345.408 210.864 345.600 210.888 ;
    END
  END o_y[29]
  PIN o_y[30]
    DIRECTION OUTPUT ;
    USE SIGNAL ;
    PORT
      LAYER M4 ;
        RECT 345.408 211.200 345.600 211.224 ;
    END
  END o_y[30]
  PIN o_y[31]
    DIRECTION OUTPUT ;
    USE SIGNAL ;
    PORT
      LAYER M4 ;
        RECT 345.408 211.536 345.600 211.560 ;
    END
  END o_y[31]
  PIN o_y[32]
    DIRECTION OUTPUT ;
    USE SIGNAL ;
    PORT
      LAYER M4 ;
        RECT 345.408 211.872 345.600 211.896 ;
    END
  END o_y[32]
  PIN o_y[33]
    DIRECTION OUTPUT ;
    USE SIGNAL ;
    PORT
      LAYER M4 ;
        RECT 345.408 212.208 345.600 212.232 ;
    END
  END o_y[33]
  PIN o_y[34]
    DIRECTION OUTPUT ;
    USE SIGNAL ;
    PORT
      LAYER M4 ;
        RECT 345.408 212.544 345.600 212.568 ;
    END
  END o_y[34]
  PIN o_y[35]
    DIRECTION OUTPUT ;
    USE SIGNAL ;
    PORT
      LAYER M4 ;
        RECT 345.408 212.880 345.600 212.904 ;
    END
  END o_y[35]
  PIN o_y[36]
    DIRECTION OUTPUT ;
    USE SIGNAL ;
    PORT
      LAYER M4 ;
        RECT 345.408 213.216 345.600 213.240 ;
    END
  END o_y[36]
  PIN o_y[37]
    DIRECTION OUTPUT ;
    USE SIGNAL ;
    PORT
      LAYER M4 ;
        RECT 345.408 213.552 345.600 213.576 ;
    END
  END o_y[37]
  PIN o_y[38]
    DIRECTION OUTPUT ;
    USE SIGNAL ;
    PORT
      LAYER M4 ;
        RECT 345.408 213.888 345.600 213.912 ;
    END
  END o_y[38]
  PIN o_y[39]
    DIRECTION OUTPUT ;
    USE SIGNAL ;
    PORT
      LAYER M4 ;
        RECT 345.408 214.224 345.600 214.248 ;
    END
  END o_y[39]
  PIN o_y[40]
    DIRECTION OUTPUT ;
    USE SIGNAL ;
    PORT
      LAYER M4 ;
        RECT 345.408 214.560 345.600 214.584 ;
    END
  END o_y[40]
  PIN o_y[41]
    DIRECTION OUTPUT ;
    USE SIGNAL ;
    PORT
      LAYER M4 ;
        RECT 345.408 214.896 345.600 214.920 ;
    END
  END o_y[41]
  PIN o_y[42]
    DIRECTION OUTPUT ;
    USE SIGNAL ;
    PORT
      LAYER M4 ;
        RECT 345.408 215.232 345.600 215.256 ;
    END
  END o_y[42]
  PIN o_y[43]
    DIRECTION OUTPUT ;
    USE SIGNAL ;
    PORT
      LAYER M4 ;
        RECT 345.408 215.568 345.600 215.592 ;
    END
  END o_y[43]
  PIN o_y[44]
    DIRECTION OUTPUT ;
    USE SIGNAL ;
    PORT
      LAYER M4 ;
        RECT 345.408 215.904 345.600 215.928 ;
    END
  END o_y[44]
  PIN o_y[45]
    DIRECTION OUTPUT ;
    USE SIGNAL ;
    PORT
      LAYER M4 ;
        RECT 345.408 216.240 345.600 216.264 ;
    END
  END o_y[45]
  PIN o_y[46]
    DIRECTION OUTPUT ;
    USE SIGNAL ;
    PORT
      LAYER M4 ;
        RECT 345.408 216.576 345.600 216.600 ;
    END
  END o_y[46]
  PIN o_y[47]
    DIRECTION OUTPUT ;
    USE SIGNAL ;
    PORT
      LAYER M4 ;
        RECT 345.408 216.912 345.600 216.936 ;
    END
  END o_y[47]
  PIN o_y[48]
    DIRECTION OUTPUT ;
    USE SIGNAL ;
    PORT
      LAYER M4 ;
        RECT 345.408 217.248 345.600 217.272 ;
    END
  END o_y[48]
  PIN o_y[49]
    DIRECTION OUTPUT ;
    USE SIGNAL ;
    PORT
      LAYER M4 ;
        RECT 345.408 217.584 345.600 217.608 ;
    END
  END o_y[49]
  PIN o_y[50]
    DIRECTION OUTPUT ;
    USE SIGNAL ;
    PORT
      LAYER M4 ;
        RECT 345.408 217.920 345.600 217.944 ;
    END
  END o_y[50]
  PIN o_y[51]
    DIRECTION OUTPUT ;
    USE SIGNAL ;
    PORT
      LAYER M4 ;
        RECT 345.408 218.256 345.600 218.280 ;
    END
  END o_y[51]
  PIN o_y[52]
    DIRECTION OUTPUT ;
    USE SIGNAL ;
    PORT
      LAYER M4 ;
        RECT 345.408 218.592 345.600 218.616 ;
    END
  END o_y[52]
  PIN o_y[53]
    DIRECTION OUTPUT ;
    USE SIGNAL ;
    PORT
      LAYER M4 ;
        RECT 345.408 218.928 345.600 218.952 ;
    END
  END o_y[53]
  PIN o_y[54]
    DIRECTION OUTPUT ;
    USE SIGNAL ;
    PORT
      LAYER M4 ;
        RECT 345.408 219.264 345.600 219.288 ;
    END
  END o_y[54]
  PIN o_y[55]
    DIRECTION OUTPUT ;
    USE SIGNAL ;
    PORT
      LAYER M4 ;
        RECT 345.408 219.600 345.600 219.624 ;
    END
  END o_y[55]
  PIN o_y[56]
    DIRECTION OUTPUT ;
    USE SIGNAL ;
    PORT
      LAYER M4 ;
        RECT 345.408 219.936 345.600 219.960 ;
    END
  END o_y[56]
  PIN o_y[57]
    DIRECTION OUTPUT ;
    USE SIGNAL ;
    PORT
      LAYER M4 ;
        RECT 345.408 220.272 345.600 220.296 ;
    END
  END o_y[57]
  PIN o_y[58]
    DIRECTION OUTPUT ;
    USE SIGNAL ;
    PORT
      LAYER M4 ;
        RECT 345.408 220.608 345.600 220.632 ;
    END
  END o_y[58]
  PIN o_y[59]
    DIRECTION OUTPUT ;
    USE SIGNAL ;
    PORT
      LAYER M4 ;
        RECT 345.408 220.944 345.600 220.968 ;
    END
  END o_y[59]
  PIN o_y[60]
    DIRECTION OUTPUT ;
    USE SIGNAL ;
    PORT
      LAYER M4 ;
        RECT 345.408 221.328 345.600 221.352 ;
    END
  END o_y[60]
  PIN o_y[61]
    DIRECTION OUTPUT ;
    USE SIGNAL ;
    PORT
      LAYER M4 ;
        RECT 345.408 221.664 345.600 221.688 ;
    END
  END o_y[61]
  PIN o_y[62]
    DIRECTION OUTPUT ;
    USE SIGNAL ;
    PORT
      LAYER M4 ;
        RECT 345.408 222.000 345.600 222.024 ;
    END
  END o_y[62]
  PIN o_y[63]
    DIRECTION OUTPUT ;
    USE SIGNAL ;
    PORT
      LAYER M4 ;
        RECT 345.408 222.336 345.600 222.360 ;
    END
  END o_y[63]
  PIN o_y[64]
    DIRECTION OUTPUT ;
    USE SIGNAL ;
    PORT
      LAYER M4 ;
        RECT 345.408 222.672 345.600 222.696 ;
    END
  END o_y[64]
  PIN o_y[65]
    DIRECTION OUTPUT ;
    USE SIGNAL ;
    PORT
      LAYER M4 ;
        RECT 345.408 223.008 345.600 223.032 ;
    END
  END o_y[65]
  PIN o_y[66]
    DIRECTION OUTPUT ;
    USE SIGNAL ;
    PORT
      LAYER M4 ;
        RECT 345.408 223.344 345.600 223.368 ;
    END
  END o_y[66]
  PIN o_y[67]
    DIRECTION OUTPUT ;
    USE SIGNAL ;
    PORT
      LAYER M4 ;
        RECT 345.408 223.680 345.600 223.704 ;
    END
  END o_y[67]
  PIN o_y[68]
    DIRECTION OUTPUT ;
    USE SIGNAL ;
    PORT
      LAYER M4 ;
        RECT 345.408 224.016 345.600 224.040 ;
    END
  END o_y[68]
  PIN o_y[69]
    DIRECTION OUTPUT ;
    USE SIGNAL ;
    PORT
      LAYER M4 ;
        RECT 345.408 224.352 345.600 224.376 ;
    END
  END o_y[69]
  PIN o_y[70]
    DIRECTION OUTPUT ;
    USE SIGNAL ;
    PORT
      LAYER M4 ;
        RECT 345.408 224.688 345.600 224.712 ;
    END
  END o_y[70]
  PIN o_y[71]
    DIRECTION OUTPUT ;
    USE SIGNAL ;
    PORT
      LAYER M4 ;
        RECT 345.408 225.024 345.600 225.048 ;
    END
  END o_y[71]
  PIN o_y[72]
    DIRECTION OUTPUT ;
    USE SIGNAL ;
    PORT
      LAYER M4 ;
        RECT 345.408 225.360 345.600 225.384 ;
    END
  END o_y[72]
  PIN o_y[73]
    DIRECTION OUTPUT ;
    USE SIGNAL ;
    PORT
      LAYER M4 ;
        RECT 345.408 225.696 345.600 225.720 ;
    END
  END o_y[73]
  PIN o_y[74]
    DIRECTION OUTPUT ;
    USE SIGNAL ;
    PORT
      LAYER M4 ;
        RECT 345.408 226.032 345.600 226.056 ;
    END
  END o_y[74]
  PIN o_y[75]
    DIRECTION OUTPUT ;
    USE SIGNAL ;
    PORT
      LAYER M4 ;
        RECT 345.408 226.368 345.600 226.392 ;
    END
  END o_y[75]
  PIN o_y[76]
    DIRECTION OUTPUT ;
    USE SIGNAL ;
    PORT
      LAYER M4 ;
        RECT 345.408 226.704 345.600 226.728 ;
    END
  END o_y[76]
  PIN o_y[77]
    DIRECTION OUTPUT ;
    USE SIGNAL ;
    PORT
      LAYER M4 ;
        RECT 345.408 227.040 345.600 227.064 ;
    END
  END o_y[77]
  PIN o_y[78]
    DIRECTION OUTPUT ;
    USE SIGNAL ;
    PORT
      LAYER M4 ;
        RECT 345.408 227.376 345.600 227.400 ;
    END
  END o_y[78]
  PIN o_y[79]
    DIRECTION OUTPUT ;
    USE SIGNAL ;
    PORT
      LAYER M4 ;
        RECT 345.408 227.712 345.600 227.736 ;
    END
  END o_y[79]
  PIN o_y[80]
    DIRECTION OUTPUT ;
    USE SIGNAL ;
    PORT
      LAYER M4 ;
        RECT 345.408 228.048 345.600 228.072 ;
    END
  END o_y[80]
  PIN o_y[81]
    DIRECTION OUTPUT ;
    USE SIGNAL ;
    PORT
      LAYER M4 ;
        RECT 345.408 228.384 345.600 228.408 ;
    END
  END o_y[81]
  PIN o_y[82]
    DIRECTION OUTPUT ;
    USE SIGNAL ;
    PORT
      LAYER M4 ;
        RECT 345.408 228.720 345.600 228.744 ;
    END
  END o_y[82]
  PIN o_y[83]
    DIRECTION OUTPUT ;
    USE SIGNAL ;
    PORT
      LAYER M4 ;
        RECT 345.408 229.056 345.600 229.080 ;
    END
  END o_y[83]
  PIN o_y[84]
    DIRECTION OUTPUT ;
    USE SIGNAL ;
    PORT
      LAYER M4 ;
        RECT 345.408 229.392 345.600 229.416 ;
    END
  END o_y[84]
  PIN o_y[85]
    DIRECTION OUTPUT ;
    USE SIGNAL ;
    PORT
      LAYER M4 ;
        RECT 345.408 229.728 345.600 229.752 ;
    END
  END o_y[85]
  PIN o_y[86]
    DIRECTION OUTPUT ;
    USE SIGNAL ;
    PORT
      LAYER M4 ;
        RECT 345.408 230.064 345.600 230.088 ;
    END
  END o_y[86]
  PIN o_y[87]
    DIRECTION OUTPUT ;
    USE SIGNAL ;
    PORT
      LAYER M4 ;
        RECT 345.408 230.400 345.600 230.424 ;
    END
  END o_y[87]
  PIN o_y[88]
    DIRECTION OUTPUT ;
    USE SIGNAL ;
    PORT
      LAYER M4 ;
        RECT 345.408 230.736 345.600 230.760 ;
    END
  END o_y[88]
  PIN o_y[89]
    DIRECTION OUTPUT ;
    USE SIGNAL ;
    PORT
      LAYER M4 ;
        RECT 345.408 231.072 345.600 231.096 ;
    END
  END o_y[89]
  PIN o_y[90]
    DIRECTION OUTPUT ;
    USE SIGNAL ;
    PORT
      LAYER M4 ;
        RECT 345.408 231.408 345.600 231.432 ;
    END
  END o_y[90]
  PIN o_y[91]
    DIRECTION OUTPUT ;
    USE SIGNAL ;
    PORT
      LAYER M4 ;
        RECT 345.408 231.744 345.600 231.768 ;
    END
  END o_y[91]
  PIN o_y[92]
    DIRECTION OUTPUT ;
    USE SIGNAL ;
    PORT
      LAYER M4 ;
        RECT 345.408 232.080 345.600 232.104 ;
    END
  END o_y[92]
  PIN o_y[93]
    DIRECTION OUTPUT ;
    USE SIGNAL ;
    PORT
      LAYER M4 ;
        RECT 345.408 232.416 345.600 232.440 ;
    END
  END o_y[93]
  PIN o_y[94]
    DIRECTION OUTPUT ;
    USE SIGNAL ;
    PORT
      LAYER M4 ;
        RECT 345.408 232.800 345.600 232.824 ;
    END
  END o_y[94]
  PIN o_y[95]
    DIRECTION OUTPUT ;
    USE SIGNAL ;
    PORT
      LAYER M4 ;
        RECT 345.408 233.136 345.600 233.160 ;
    END
  END o_y[95]
  PIN o_y[96]
    DIRECTION OUTPUT ;
    USE SIGNAL ;
    PORT
      LAYER M4 ;
        RECT 345.408 233.472 345.600 233.496 ;
    END
  END o_y[96]
  PIN o_y[97]
    DIRECTION OUTPUT ;
    USE SIGNAL ;
    PORT
      LAYER M4 ;
        RECT 345.408 233.808 345.600 233.832 ;
    END
  END o_y[97]
  PIN o_y[98]
    DIRECTION OUTPUT ;
    USE SIGNAL ;
    PORT
      LAYER M4 ;
        RECT 345.408 234.144 345.600 234.168 ;
    END
  END o_y[98]
  PIN o_y[99]
    DIRECTION OUTPUT ;
    USE SIGNAL ;
    PORT
      LAYER M4 ;
        RECT 345.408 234.480 345.600 234.504 ;
    END
  END o_y[99]
  PIN o_y[100]
    DIRECTION OUTPUT ;
    USE SIGNAL ;
    PORT
      LAYER M4 ;
        RECT 345.408 234.816 345.600 234.840 ;
    END
  END o_y[100]
  PIN o_y[101]
    DIRECTION OUTPUT ;
    USE SIGNAL ;
    PORT
      LAYER M4 ;
        RECT 345.408 235.152 345.600 235.176 ;
    END
  END o_y[101]
  PIN o_y[102]
    DIRECTION OUTPUT ;
    USE SIGNAL ;
    PORT
      LAYER M4 ;
        RECT 345.408 235.488 345.600 235.512 ;
    END
  END o_y[102]
  PIN o_y[103]
    DIRECTION OUTPUT ;
    USE SIGNAL ;
    PORT
      LAYER M4 ;
        RECT 345.408 235.824 345.600 235.848 ;
    END
  END o_y[103]
  PIN o_y[104]
    DIRECTION OUTPUT ;
    USE SIGNAL ;
    PORT
      LAYER M4 ;
        RECT 345.408 236.160 345.600 236.184 ;
    END
  END o_y[104]
  PIN o_y[105]
    DIRECTION OUTPUT ;
    USE SIGNAL ;
    PORT
      LAYER M4 ;
        RECT 345.408 236.496 345.600 236.520 ;
    END
  END o_y[105]
  PIN o_y[106]
    DIRECTION OUTPUT ;
    USE SIGNAL ;
    PORT
      LAYER M4 ;
        RECT 345.408 236.832 345.600 236.856 ;
    END
  END o_y[106]
  PIN o_y[107]
    DIRECTION OUTPUT ;
    USE SIGNAL ;
    PORT
      LAYER M4 ;
        RECT 345.408 237.168 345.600 237.192 ;
    END
  END o_y[107]
  PIN o_y[108]
    DIRECTION OUTPUT ;
    USE SIGNAL ;
    PORT
      LAYER M4 ;
        RECT 345.408 237.504 345.600 237.528 ;
    END
  END o_y[108]
  PIN o_y[109]
    DIRECTION OUTPUT ;
    USE SIGNAL ;
    PORT
      LAYER M4 ;
        RECT 345.408 237.840 345.600 237.864 ;
    END
  END o_y[109]
  PIN o_y[110]
    DIRECTION OUTPUT ;
    USE SIGNAL ;
    PORT
      LAYER M4 ;
        RECT 345.408 238.176 345.600 238.200 ;
    END
  END o_y[110]
  PIN o_y[111]
    DIRECTION OUTPUT ;
    USE SIGNAL ;
    PORT
      LAYER M4 ;
        RECT 345.408 238.512 345.600 238.536 ;
    END
  END o_y[111]
  PIN o_y[112]
    DIRECTION OUTPUT ;
    USE SIGNAL ;
    PORT
      LAYER M4 ;
        RECT 345.408 238.848 345.600 238.872 ;
    END
  END o_y[112]
  PIN o_y[113]
    DIRECTION OUTPUT ;
    USE SIGNAL ;
    PORT
      LAYER M4 ;
        RECT 345.408 239.184 345.600 239.208 ;
    END
  END o_y[113]
  PIN o_y[114]
    DIRECTION OUTPUT ;
    USE SIGNAL ;
    PORT
      LAYER M4 ;
        RECT 345.408 239.520 345.600 239.544 ;
    END
  END o_y[114]
  PIN o_y[115]
    DIRECTION OUTPUT ;
    USE SIGNAL ;
    PORT
      LAYER M4 ;
        RECT 345.408 239.856 345.600 239.880 ;
    END
  END o_y[115]
  PIN o_y[116]
    DIRECTION OUTPUT ;
    USE SIGNAL ;
    PORT
      LAYER M4 ;
        RECT 345.408 240.192 345.600 240.216 ;
    END
  END o_y[116]
  PIN o_y[117]
    DIRECTION OUTPUT ;
    USE SIGNAL ;
    PORT
      LAYER M4 ;
        RECT 345.408 240.528 345.600 240.552 ;
    END
  END o_y[117]
  PIN o_y[118]
    DIRECTION OUTPUT ;
    USE SIGNAL ;
    PORT
      LAYER M4 ;
        RECT 345.408 240.864 345.600 240.888 ;
    END
  END o_y[118]
  PIN o_y[119]
    DIRECTION OUTPUT ;
    USE SIGNAL ;
    PORT
      LAYER M4 ;
        RECT 345.408 241.200 345.600 241.224 ;
    END
  END o_y[119]
  PIN o_y[120]
    DIRECTION OUTPUT ;
    USE SIGNAL ;
    PORT
      LAYER M4 ;
        RECT 345.408 241.536 345.600 241.560 ;
    END
  END o_y[120]
  PIN o_y[121]
    DIRECTION OUTPUT ;
    USE SIGNAL ;
    PORT
      LAYER M4 ;
        RECT 345.408 241.872 345.600 241.896 ;
    END
  END o_y[121]
  PIN o_y[122]
    DIRECTION OUTPUT ;
    USE SIGNAL ;
    PORT
      LAYER M4 ;
        RECT 345.408 242.208 345.600 242.232 ;
    END
  END o_y[122]
  PIN o_y[123]
    DIRECTION OUTPUT ;
    USE SIGNAL ;
    PORT
      LAYER M4 ;
        RECT 345.408 242.544 345.600 242.568 ;
    END
  END o_y[123]
  PIN o_y[124]
    DIRECTION OUTPUT ;
    USE SIGNAL ;
    PORT
      LAYER M4 ;
        RECT 345.408 242.880 345.600 242.904 ;
    END
  END o_y[124]
  PIN o_y[125]
    DIRECTION OUTPUT ;
    USE SIGNAL ;
    PORT
      LAYER M4 ;
        RECT 345.408 243.216 345.600 243.240 ;
    END
  END o_y[125]
  PIN o_y[126]
    DIRECTION OUTPUT ;
    USE SIGNAL ;
    PORT
      LAYER M4 ;
        RECT 345.408 243.552 345.600 243.576 ;
    END
  END o_y[126]
  PIN o_y[127]
    DIRECTION OUTPUT ;
    USE SIGNAL ;
    PORT
      LAYER M4 ;
        RECT 345.408 243.888 345.600 243.912 ;
    END
  END o_y[127]
  PIN o_y[128]
    DIRECTION OUTPUT ;
    USE SIGNAL ;
    PORT
      LAYER M4 ;
        RECT 345.408 244.272 345.600 244.296 ;
    END
  END o_y[128]
  PIN o_y[129]
    DIRECTION OUTPUT ;
    USE SIGNAL ;
    PORT
      LAYER M4 ;
        RECT 345.408 244.608 345.600 244.632 ;
    END
  END o_y[129]
  PIN o_y[130]
    DIRECTION OUTPUT ;
    USE SIGNAL ;
    PORT
      LAYER M4 ;
        RECT 345.408 244.944 345.600 244.968 ;
    END
  END o_y[130]
  PIN o_y[131]
    DIRECTION OUTPUT ;
    USE SIGNAL ;
    PORT
      LAYER M4 ;
        RECT 345.408 245.280 345.600 245.304 ;
    END
  END o_y[131]
  PIN o_y[132]
    DIRECTION OUTPUT ;
    USE SIGNAL ;
    PORT
      LAYER M4 ;
        RECT 345.408 245.616 345.600 245.640 ;
    END
  END o_y[132]
  PIN o_y[133]
    DIRECTION OUTPUT ;
    USE SIGNAL ;
    PORT
      LAYER M4 ;
        RECT 345.408 245.952 345.600 245.976 ;
    END
  END o_y[133]
  PIN o_y[134]
    DIRECTION OUTPUT ;
    USE SIGNAL ;
    PORT
      LAYER M4 ;
        RECT 345.408 246.288 345.600 246.312 ;
    END
  END o_y[134]
  PIN o_y[135]
    DIRECTION OUTPUT ;
    USE SIGNAL ;
    PORT
      LAYER M4 ;
        RECT 345.408 246.624 345.600 246.648 ;
    END
  END o_y[135]
  PIN o_y[136]
    DIRECTION OUTPUT ;
    USE SIGNAL ;
    PORT
      LAYER M4 ;
        RECT 345.408 246.960 345.600 246.984 ;
    END
  END o_y[136]
  PIN o_y[137]
    DIRECTION OUTPUT ;
    USE SIGNAL ;
    PORT
      LAYER M4 ;
        RECT 345.408 247.296 345.600 247.320 ;
    END
  END o_y[137]
  PIN o_y[138]
    DIRECTION OUTPUT ;
    USE SIGNAL ;
    PORT
      LAYER M4 ;
        RECT 345.408 247.632 345.600 247.656 ;
    END
  END o_y[138]
  PIN o_y[139]
    DIRECTION OUTPUT ;
    USE SIGNAL ;
    PORT
      LAYER M4 ;
        RECT 345.408 247.968 345.600 247.992 ;
    END
  END o_y[139]
  PIN o_y[140]
    DIRECTION OUTPUT ;
    USE SIGNAL ;
    PORT
      LAYER M4 ;
        RECT 345.408 248.304 345.600 248.328 ;
    END
  END o_y[140]
  PIN o_y[141]
    DIRECTION OUTPUT ;
    USE SIGNAL ;
    PORT
      LAYER M4 ;
        RECT 345.408 248.640 345.600 248.664 ;
    END
  END o_y[141]
  PIN o_y[142]
    DIRECTION OUTPUT ;
    USE SIGNAL ;
    PORT
      LAYER M4 ;
        RECT 345.408 248.976 345.600 249.000 ;
    END
  END o_y[142]
  PIN o_y[143]
    DIRECTION OUTPUT ;
    USE SIGNAL ;
    PORT
      LAYER M4 ;
        RECT 345.408 249.312 345.600 249.336 ;
    END
  END o_y[143]
  PIN o_y[144]
    DIRECTION OUTPUT ;
    USE SIGNAL ;
    PORT
      LAYER M4 ;
        RECT 345.408 249.648 345.600 249.672 ;
    END
  END o_y[144]
  PIN o_y[145]
    DIRECTION OUTPUT ;
    USE SIGNAL ;
    PORT
      LAYER M4 ;
        RECT 345.408 249.984 345.600 250.008 ;
    END
  END o_y[145]
  PIN o_y[146]
    DIRECTION OUTPUT ;
    USE SIGNAL ;
    PORT
      LAYER M4 ;
        RECT 345.408 250.320 345.600 250.344 ;
    END
  END o_y[146]
  PIN o_y[147]
    DIRECTION OUTPUT ;
    USE SIGNAL ;
    PORT
      LAYER M4 ;
        RECT 345.408 250.656 345.600 250.680 ;
    END
  END o_y[147]
  PIN o_y[148]
    DIRECTION OUTPUT ;
    USE SIGNAL ;
    PORT
      LAYER M4 ;
        RECT 345.408 250.992 345.600 251.016 ;
    END
  END o_y[148]
  PIN o_y[149]
    DIRECTION OUTPUT ;
    USE SIGNAL ;
    PORT
      LAYER M4 ;
        RECT 345.408 251.328 345.600 251.352 ;
    END
  END o_y[149]
  PIN o_y[150]
    DIRECTION OUTPUT ;
    USE SIGNAL ;
    PORT
      LAYER M4 ;
        RECT 345.408 251.664 345.600 251.688 ;
    END
  END o_y[150]
  PIN o_y[151]
    DIRECTION OUTPUT ;
    USE SIGNAL ;
    PORT
      LAYER M4 ;
        RECT 345.408 252.000 345.600 252.024 ;
    END
  END o_y[151]
  PIN o_y[152]
    DIRECTION OUTPUT ;
    USE SIGNAL ;
    PORT
      LAYER M4 ;
        RECT 345.408 252.336 345.600 252.360 ;
    END
  END o_y[152]
  PIN o_y[153]
    DIRECTION OUTPUT ;
    USE SIGNAL ;
    PORT
      LAYER M4 ;
        RECT 345.408 252.672 345.600 252.696 ;
    END
  END o_y[153]
  PIN o_y[154]
    DIRECTION OUTPUT ;
    USE SIGNAL ;
    PORT
      LAYER M4 ;
        RECT 345.408 253.008 345.600 253.032 ;
    END
  END o_y[154]
  PIN o_y[155]
    DIRECTION OUTPUT ;
    USE SIGNAL ;
    PORT
      LAYER M4 ;
        RECT 345.408 253.344 345.600 253.368 ;
    END
  END o_y[155]
  PIN o_y[156]
    DIRECTION OUTPUT ;
    USE SIGNAL ;
    PORT
      LAYER M4 ;
        RECT 345.408 253.680 345.600 253.704 ;
    END
  END o_y[156]
  PIN o_y[157]
    DIRECTION OUTPUT ;
    USE SIGNAL ;
    PORT
      LAYER M4 ;
        RECT 345.408 254.016 345.600 254.040 ;
    END
  END o_y[157]
  PIN o_y[158]
    DIRECTION OUTPUT ;
    USE SIGNAL ;
    PORT
      LAYER M4 ;
        RECT 345.408 254.352 345.600 254.376 ;
    END
  END o_y[158]
  PIN o_y[159]
    DIRECTION OUTPUT ;
    USE SIGNAL ;
    PORT
      LAYER M4 ;
        RECT 345.408 254.688 345.600 254.712 ;
    END
  END o_y[159]
  PIN o_y[160]
    DIRECTION OUTPUT ;
    USE SIGNAL ;
    PORT
      LAYER M4 ;
        RECT 345.408 255.024 345.600 255.048 ;
    END
  END o_y[160]
  PIN o_y[161]
    DIRECTION OUTPUT ;
    USE SIGNAL ;
    PORT
      LAYER M4 ;
        RECT 345.408 255.360 345.600 255.384 ;
    END
  END o_y[161]
  PIN o_y[162]
    DIRECTION OUTPUT ;
    USE SIGNAL ;
    PORT
      LAYER M4 ;
        RECT 345.408 255.744 345.600 255.768 ;
    END
  END o_y[162]
  PIN o_y[163]
    DIRECTION OUTPUT ;
    USE SIGNAL ;
    PORT
      LAYER M4 ;
        RECT 345.408 256.080 345.600 256.104 ;
    END
  END o_y[163]
  PIN o_y[164]
    DIRECTION OUTPUT ;
    USE SIGNAL ;
    PORT
      LAYER M4 ;
        RECT 345.408 256.416 345.600 256.440 ;
    END
  END o_y[164]
  PIN o_y[165]
    DIRECTION OUTPUT ;
    USE SIGNAL ;
    PORT
      LAYER M4 ;
        RECT 345.408 256.752 345.600 256.776 ;
    END
  END o_y[165]
  PIN o_y[166]
    DIRECTION OUTPUT ;
    USE SIGNAL ;
    PORT
      LAYER M4 ;
        RECT 345.408 257.088 345.600 257.112 ;
    END
  END o_y[166]
  PIN o_y[167]
    DIRECTION OUTPUT ;
    USE SIGNAL ;
    PORT
      LAYER M4 ;
        RECT 345.408 257.424 345.600 257.448 ;
    END
  END o_y[167]
  PIN o_y[168]
    DIRECTION OUTPUT ;
    USE SIGNAL ;
    PORT
      LAYER M4 ;
        RECT 345.408 257.760 345.600 257.784 ;
    END
  END o_y[168]
  PIN o_y[169]
    DIRECTION OUTPUT ;
    USE SIGNAL ;
    PORT
      LAYER M4 ;
        RECT 345.408 258.096 345.600 258.120 ;
    END
  END o_y[169]
  PIN o_y[170]
    DIRECTION OUTPUT ;
    USE SIGNAL ;
    PORT
      LAYER M4 ;
        RECT 345.408 258.432 345.600 258.456 ;
    END
  END o_y[170]
  PIN o_y[171]
    DIRECTION OUTPUT ;
    USE SIGNAL ;
    PORT
      LAYER M4 ;
        RECT 345.408 258.768 345.600 258.792 ;
    END
  END o_y[171]
  PIN o_y[172]
    DIRECTION OUTPUT ;
    USE SIGNAL ;
    PORT
      LAYER M4 ;
        RECT 345.408 259.104 345.600 259.128 ;
    END
  END o_y[172]
  PIN o_y[173]
    DIRECTION OUTPUT ;
    USE SIGNAL ;
    PORT
      LAYER M4 ;
        RECT 345.408 259.440 345.600 259.464 ;
    END
  END o_y[173]
  PIN o_y[174]
    DIRECTION OUTPUT ;
    USE SIGNAL ;
    PORT
      LAYER M4 ;
        RECT 345.408 259.776 345.600 259.800 ;
    END
  END o_y[174]
  PIN o_y[175]
    DIRECTION OUTPUT ;
    USE SIGNAL ;
    PORT
      LAYER M4 ;
        RECT 345.408 260.112 345.600 260.136 ;
    END
  END o_y[175]
  PIN o_y[176]
    DIRECTION OUTPUT ;
    USE SIGNAL ;
    PORT
      LAYER M4 ;
        RECT 345.408 260.448 345.600 260.472 ;
    END
  END o_y[176]
  PIN o_y[177]
    DIRECTION OUTPUT ;
    USE SIGNAL ;
    PORT
      LAYER M4 ;
        RECT 345.408 260.784 345.600 260.808 ;
    END
  END o_y[177]
  PIN o_y[178]
    DIRECTION OUTPUT ;
    USE SIGNAL ;
    PORT
      LAYER M4 ;
        RECT 345.408 261.120 345.600 261.144 ;
    END
  END o_y[178]
  PIN o_y[179]
    DIRECTION OUTPUT ;
    USE SIGNAL ;
    PORT
      LAYER M4 ;
        RECT 345.408 261.456 345.600 261.480 ;
    END
  END o_y[179]
  PIN o_y[180]
    DIRECTION OUTPUT ;
    USE SIGNAL ;
    PORT
      LAYER M4 ;
        RECT 345.408 261.792 345.600 261.816 ;
    END
  END o_y[180]
  PIN o_y[181]
    DIRECTION OUTPUT ;
    USE SIGNAL ;
    PORT
      LAYER M4 ;
        RECT 345.408 262.128 345.600 262.152 ;
    END
  END o_y[181]
  PIN o_y[182]
    DIRECTION OUTPUT ;
    USE SIGNAL ;
    PORT
      LAYER M4 ;
        RECT 345.408 262.464 345.600 262.488 ;
    END
  END o_y[182]
  PIN o_y[183]
    DIRECTION OUTPUT ;
    USE SIGNAL ;
    PORT
      LAYER M4 ;
        RECT 345.408 262.800 345.600 262.824 ;
    END
  END o_y[183]
  PIN o_y[184]
    DIRECTION OUTPUT ;
    USE SIGNAL ;
    PORT
      LAYER M4 ;
        RECT 345.408 263.136 345.600 263.160 ;
    END
  END o_y[184]
  PIN o_y[185]
    DIRECTION OUTPUT ;
    USE SIGNAL ;
    PORT
      LAYER M4 ;
        RECT 345.408 263.472 345.600 263.496 ;
    END
  END o_y[185]
  PIN o_y[186]
    DIRECTION OUTPUT ;
    USE SIGNAL ;
    PORT
      LAYER M4 ;
        RECT 345.408 263.808 345.600 263.832 ;
    END
  END o_y[186]
  PIN o_y[187]
    DIRECTION OUTPUT ;
    USE SIGNAL ;
    PORT
      LAYER M4 ;
        RECT 345.408 264.144 345.600 264.168 ;
    END
  END o_y[187]
  PIN o_y[188]
    DIRECTION OUTPUT ;
    USE SIGNAL ;
    PORT
      LAYER M4 ;
        RECT 345.408 264.480 345.600 264.504 ;
    END
  END o_y[188]
  PIN o_y[189]
    DIRECTION OUTPUT ;
    USE SIGNAL ;
    PORT
      LAYER M4 ;
        RECT 345.408 264.816 345.600 264.840 ;
    END
  END o_y[189]
  PIN o_y[190]
    DIRECTION OUTPUT ;
    USE SIGNAL ;
    PORT
      LAYER M4 ;
        RECT 345.408 265.152 345.600 265.176 ;
    END
  END o_y[190]
  PIN o_y[191]
    DIRECTION OUTPUT ;
    USE SIGNAL ;
    PORT
      LAYER M4 ;
        RECT 345.408 265.488 345.600 265.512 ;
    END
  END o_y[191]
  PIN o_y[192]
    DIRECTION OUTPUT ;
    USE SIGNAL ;
    PORT
      LAYER M4 ;
        RECT 345.408 265.824 345.600 265.848 ;
    END
  END o_y[192]
  PIN o_y[193]
    DIRECTION OUTPUT ;
    USE SIGNAL ;
    PORT
      LAYER M4 ;
        RECT 345.408 266.160 345.600 266.184 ;
    END
  END o_y[193]
  PIN o_y[194]
    DIRECTION OUTPUT ;
    USE SIGNAL ;
    PORT
      LAYER M4 ;
        RECT 345.408 266.496 345.600 266.520 ;
    END
  END o_y[194]
  PIN o_y[195]
    DIRECTION OUTPUT ;
    USE SIGNAL ;
    PORT
      LAYER M4 ;
        RECT 345.408 266.832 345.600 266.856 ;
    END
  END o_y[195]
  PIN o_y[196]
    DIRECTION OUTPUT ;
    USE SIGNAL ;
    PORT
      LAYER M4 ;
        RECT 345.408 267.216 345.600 267.240 ;
    END
  END o_y[196]
  PIN o_y[197]
    DIRECTION OUTPUT ;
    USE SIGNAL ;
    PORT
      LAYER M4 ;
        RECT 345.408 267.552 345.600 267.576 ;
    END
  END o_y[197]
  PIN o_y[198]
    DIRECTION OUTPUT ;
    USE SIGNAL ;
    PORT
      LAYER M4 ;
        RECT 345.408 267.888 345.600 267.912 ;
    END
  END o_y[198]
  PIN o_y[199]
    DIRECTION OUTPUT ;
    USE SIGNAL ;
    PORT
      LAYER M4 ;
        RECT 345.408 268.224 345.600 268.248 ;
    END
  END o_y[199]
  PIN o_y[200]
    DIRECTION OUTPUT ;
    USE SIGNAL ;
    PORT
      LAYER M4 ;
        RECT 345.408 268.560 345.600 268.584 ;
    END
  END o_y[200]
  PIN o_y[201]
    DIRECTION OUTPUT ;
    USE SIGNAL ;
    PORT
      LAYER M4 ;
        RECT 345.408 268.896 345.600 268.920 ;
    END
  END o_y[201]
  PIN o_y[202]
    DIRECTION OUTPUT ;
    USE SIGNAL ;
    PORT
      LAYER M4 ;
        RECT 345.408 269.232 345.600 269.256 ;
    END
  END o_y[202]
  PIN o_y[203]
    DIRECTION OUTPUT ;
    USE SIGNAL ;
    PORT
      LAYER M4 ;
        RECT 345.408 269.568 345.600 269.592 ;
    END
  END o_y[203]
  PIN o_y[204]
    DIRECTION OUTPUT ;
    USE SIGNAL ;
    PORT
      LAYER M4 ;
        RECT 345.408 269.904 345.600 269.928 ;
    END
  END o_y[204]
  PIN o_y[205]
    DIRECTION OUTPUT ;
    USE SIGNAL ;
    PORT
      LAYER M4 ;
        RECT 345.408 270.240 345.600 270.264 ;
    END
  END o_y[205]
  PIN o_y[206]
    DIRECTION OUTPUT ;
    USE SIGNAL ;
    PORT
      LAYER M4 ;
        RECT 345.408 270.576 345.600 270.600 ;
    END
  END o_y[206]
  PIN o_y[207]
    DIRECTION OUTPUT ;
    USE SIGNAL ;
    PORT
      LAYER M4 ;
        RECT 345.408 270.912 345.600 270.936 ;
    END
  END o_y[207]
  PIN o_y[208]
    DIRECTION OUTPUT ;
    USE SIGNAL ;
    PORT
      LAYER M4 ;
        RECT 345.408 271.248 345.600 271.272 ;
    END
  END o_y[208]
  PIN o_y[209]
    DIRECTION OUTPUT ;
    USE SIGNAL ;
    PORT
      LAYER M4 ;
        RECT 345.408 271.584 345.600 271.608 ;
    END
  END o_y[209]
  PIN o_y[210]
    DIRECTION OUTPUT ;
    USE SIGNAL ;
    PORT
      LAYER M4 ;
        RECT 345.408 271.920 345.600 271.944 ;
    END
  END o_y[210]
  PIN o_y[211]
    DIRECTION OUTPUT ;
    USE SIGNAL ;
    PORT
      LAYER M4 ;
        RECT 345.408 272.256 345.600 272.280 ;
    END
  END o_y[211]
  PIN o_y[212]
    DIRECTION OUTPUT ;
    USE SIGNAL ;
    PORT
      LAYER M4 ;
        RECT 345.408 272.592 345.600 272.616 ;
    END
  END o_y[212]
  PIN o_y[213]
    DIRECTION OUTPUT ;
    USE SIGNAL ;
    PORT
      LAYER M4 ;
        RECT 345.408 272.928 345.600 272.952 ;
    END
  END o_y[213]
  PIN o_y[214]
    DIRECTION OUTPUT ;
    USE SIGNAL ;
    PORT
      LAYER M4 ;
        RECT 345.408 273.264 345.600 273.288 ;
    END
  END o_y[214]
  PIN o_y[215]
    DIRECTION OUTPUT ;
    USE SIGNAL ;
    PORT
      LAYER M4 ;
        RECT 345.408 273.600 345.600 273.624 ;
    END
  END o_y[215]
  PIN o_y[216]
    DIRECTION OUTPUT ;
    USE SIGNAL ;
    PORT
      LAYER M4 ;
        RECT 345.408 273.936 345.600 273.960 ;
    END
  END o_y[216]
  PIN o_y[217]
    DIRECTION OUTPUT ;
    USE SIGNAL ;
    PORT
      LAYER M4 ;
        RECT 345.408 274.272 345.600 274.296 ;
    END
  END o_y[217]
  PIN o_y[218]
    DIRECTION OUTPUT ;
    USE SIGNAL ;
    PORT
      LAYER M4 ;
        RECT 345.408 274.608 345.600 274.632 ;
    END
  END o_y[218]
  PIN o_y[219]
    DIRECTION OUTPUT ;
    USE SIGNAL ;
    PORT
      LAYER M4 ;
        RECT 345.408 274.944 345.600 274.968 ;
    END
  END o_y[219]
  PIN o_y[220]
    DIRECTION OUTPUT ;
    USE SIGNAL ;
    PORT
      LAYER M4 ;
        RECT 345.408 275.280 345.600 275.304 ;
    END
  END o_y[220]
  PIN o_y[221]
    DIRECTION OUTPUT ;
    USE SIGNAL ;
    PORT
      LAYER M4 ;
        RECT 345.408 275.616 345.600 275.640 ;
    END
  END o_y[221]
  PIN o_y[222]
    DIRECTION OUTPUT ;
    USE SIGNAL ;
    PORT
      LAYER M4 ;
        RECT 345.408 275.952 345.600 275.976 ;
    END
  END o_y[222]
  PIN o_y[223]
    DIRECTION OUTPUT ;
    USE SIGNAL ;
    PORT
      LAYER M4 ;
        RECT 345.408 276.288 345.600 276.312 ;
    END
  END o_y[223]
  PIN o_y[224]
    DIRECTION OUTPUT ;
    USE SIGNAL ;
    PORT
      LAYER M4 ;
        RECT 345.408 276.624 345.600 276.648 ;
    END
  END o_y[224]
  PIN o_y[225]
    DIRECTION OUTPUT ;
    USE SIGNAL ;
    PORT
      LAYER M4 ;
        RECT 345.408 276.960 345.600 276.984 ;
    END
  END o_y[225]
  PIN o_y[226]
    DIRECTION OUTPUT ;
    USE SIGNAL ;
    PORT
      LAYER M4 ;
        RECT 345.408 277.296 345.600 277.320 ;
    END
  END o_y[226]
  PIN o_y[227]
    DIRECTION OUTPUT ;
    USE SIGNAL ;
    PORT
      LAYER M4 ;
        RECT 345.408 277.632 345.600 277.656 ;
    END
  END o_y[227]
  PIN o_y[228]
    DIRECTION OUTPUT ;
    USE SIGNAL ;
    PORT
      LAYER M4 ;
        RECT 345.408 277.968 345.600 277.992 ;
    END
  END o_y[228]
  PIN o_y[229]
    DIRECTION OUTPUT ;
    USE SIGNAL ;
    PORT
      LAYER M4 ;
        RECT 345.408 278.304 345.600 278.328 ;
    END
  END o_y[229]
  PIN o_y[230]
    DIRECTION OUTPUT ;
    USE SIGNAL ;
    PORT
      LAYER M4 ;
        RECT 345.408 278.688 345.600 278.712 ;
    END
  END o_y[230]
  PIN o_y[231]
    DIRECTION OUTPUT ;
    USE SIGNAL ;
    PORT
      LAYER M4 ;
        RECT 345.408 279.024 345.600 279.048 ;
    END
  END o_y[231]
  PIN o_y[232]
    DIRECTION OUTPUT ;
    USE SIGNAL ;
    PORT
      LAYER M4 ;
        RECT 345.408 279.360 345.600 279.384 ;
    END
  END o_y[232]
  PIN o_y[233]
    DIRECTION OUTPUT ;
    USE SIGNAL ;
    PORT
      LAYER M4 ;
        RECT 345.408 279.696 345.600 279.720 ;
    END
  END o_y[233]
  PIN o_y[234]
    DIRECTION OUTPUT ;
    USE SIGNAL ;
    PORT
      LAYER M4 ;
        RECT 345.408 280.032 345.600 280.056 ;
    END
  END o_y[234]
  PIN o_y[235]
    DIRECTION OUTPUT ;
    USE SIGNAL ;
    PORT
      LAYER M4 ;
        RECT 345.408 280.368 345.600 280.392 ;
    END
  END o_y[235]
  PIN o_y[236]
    DIRECTION OUTPUT ;
    USE SIGNAL ;
    PORT
      LAYER M4 ;
        RECT 345.408 280.704 345.600 280.728 ;
    END
  END o_y[236]
  PIN o_y[237]
    DIRECTION OUTPUT ;
    USE SIGNAL ;
    PORT
      LAYER M4 ;
        RECT 345.408 281.040 345.600 281.064 ;
    END
  END o_y[237]
  PIN o_y[238]
    DIRECTION OUTPUT ;
    USE SIGNAL ;
    PORT
      LAYER M4 ;
        RECT 345.408 281.376 345.600 281.400 ;
    END
  END o_y[238]
  PIN o_y[239]
    DIRECTION OUTPUT ;
    USE SIGNAL ;
    PORT
      LAYER M4 ;
        RECT 345.408 281.712 345.600 281.736 ;
    END
  END o_y[239]
  PIN o_y[240]
    DIRECTION OUTPUT ;
    USE SIGNAL ;
    PORT
      LAYER M4 ;
        RECT 345.408 282.048 345.600 282.072 ;
    END
  END o_y[240]
  PIN o_y[241]
    DIRECTION OUTPUT ;
    USE SIGNAL ;
    PORT
      LAYER M4 ;
        RECT 345.408 282.384 345.600 282.408 ;
    END
  END o_y[241]
  PIN o_y[242]
    DIRECTION OUTPUT ;
    USE SIGNAL ;
    PORT
      LAYER M4 ;
        RECT 345.408 282.720 345.600 282.744 ;
    END
  END o_y[242]
  PIN o_y[243]
    DIRECTION OUTPUT ;
    USE SIGNAL ;
    PORT
      LAYER M4 ;
        RECT 345.408 283.056 345.600 283.080 ;
    END
  END o_y[243]
  PIN o_y[244]
    DIRECTION OUTPUT ;
    USE SIGNAL ;
    PORT
      LAYER M4 ;
        RECT 345.408 283.392 345.600 283.416 ;
    END
  END o_y[244]
  PIN o_y[245]
    DIRECTION OUTPUT ;
    USE SIGNAL ;
    PORT
      LAYER M4 ;
        RECT 345.408 283.728 345.600 283.752 ;
    END
  END o_y[245]
  PIN o_y[246]
    DIRECTION OUTPUT ;
    USE SIGNAL ;
    PORT
      LAYER M4 ;
        RECT 345.408 284.064 345.600 284.088 ;
    END
  END o_y[246]
  PIN o_y[247]
    DIRECTION OUTPUT ;
    USE SIGNAL ;
    PORT
      LAYER M4 ;
        RECT 345.408 284.400 345.600 284.424 ;
    END
  END o_y[247]
  PIN o_y[248]
    DIRECTION OUTPUT ;
    USE SIGNAL ;
    PORT
      LAYER M4 ;
        RECT 345.408 284.736 345.600 284.760 ;
    END
  END o_y[248]
  PIN o_y[249]
    DIRECTION OUTPUT ;
    USE SIGNAL ;
    PORT
      LAYER M4 ;
        RECT 345.408 285.072 345.600 285.096 ;
    END
  END o_y[249]
  PIN o_y[250]
    DIRECTION OUTPUT ;
    USE SIGNAL ;
    PORT
      LAYER M4 ;
        RECT 345.408 285.408 345.600 285.432 ;
    END
  END o_y[250]
  PIN o_y[251]
    DIRECTION OUTPUT ;
    USE SIGNAL ;
    PORT
      LAYER M4 ;
        RECT 345.408 285.744 345.600 285.768 ;
    END
  END o_y[251]
  PIN o_y[252]
    DIRECTION OUTPUT ;
    USE SIGNAL ;
    PORT
      LAYER M4 ;
        RECT 345.408 286.080 345.600 286.104 ;
    END
  END o_y[252]
  PIN o_y[253]
    DIRECTION OUTPUT ;
    USE SIGNAL ;
    PORT
      LAYER M4 ;
        RECT 345.408 286.416 345.600 286.440 ;
    END
  END o_y[253]
  PIN o_y[254]
    DIRECTION OUTPUT ;
    USE SIGNAL ;
    PORT
      LAYER M4 ;
        RECT 345.408 286.752 345.600 286.776 ;
    END
  END o_y[254]
  PIN o_y[255]
    DIRECTION OUTPUT ;
    USE SIGNAL ;
    PORT
      LAYER M4 ;
        RECT 345.408 287.088 345.600 287.112 ;
    END
  END o_y[255]
  PIN clk
    DIRECTION INPUT ;
    USE CLOCK ;
    PORT
      LAYER M5 ;
        RECT 87.456 0.000 87.480 0.192 ;
    END
  END clk
  PIN rst_n
    DIRECTION INPUT ;
    USE SIGNAL ;
    PORT
      LAYER M5 ;
        RECT 258.096 0.000 258.120 0.192 ;
    END
  END rst_n
  PIN fault
    DIRECTION OUTPUT ;
    USE SIGNAL ;
    PORT
      LAYER M3 ;
        RECT 146.877 0.000 146.901 0.192 ;
    END
  END fault
  PIN VDD
    DIRECTION INOUT ;
    USE POWER ;
    PORT
      LAYER M5 ;
        RECT 2.460 0.500 2.580 345.100 ;
        RECT 7.860 0.500 7.980 345.100 ;
        RECT 13.260 0.500 13.380 345.100 ;
        RECT 18.660 0.500 18.780 345.100 ;
        RECT 24.060 0.500 24.180 345.100 ;
        RECT 29.460 0.500 29.580 345.100 ;
        RECT 34.860 0.500 34.980 345.100 ;
        RECT 40.260 0.500 40.380 345.100 ;
        RECT 45.660 0.500 45.780 345.100 ;
        RECT 51.060 0.500 51.180 345.100 ;
        RECT 56.460 0.500 56.580 345.100 ;
        RECT 61.860 0.500 61.980 345.100 ;
        RECT 67.260 0.500 67.380 345.100 ;
        RECT 72.660 0.500 72.780 345.100 ;
        RECT 78.060 0.500 78.180 345.100 ;
        RECT 83.460 0.500 83.580 345.100 ;
        RECT 88.860 0.500 88.980 345.100 ;
        RECT 94.260 0.500 94.380 345.100 ;
        RECT 99.660 0.500 99.780 345.100 ;
        RECT 105.060 0.500 105.180 345.100 ;
        RECT 110.460 0.500 110.580 345.100 ;
        RECT 115.860 0.500 115.980 345.100 ;
        RECT 121.260 0.500 121.380 345.100 ;
        RECT 126.660 0.500 126.780 345.100 ;
        RECT 132.060 0.500 132.180 345.100 ;
        RECT 137.460 0.500 137.580 345.100 ;
        RECT 142.860 0.500 142.980 345.100 ;
        RECT 148.260 0.500 148.380 345.100 ;
        RECT 153.660 0.500 153.780 345.100 ;
        RECT 159.060 0.500 159.180 345.100 ;
        RECT 164.460 0.500 164.580 345.100 ;
        RECT 169.860 0.500 169.980 345.100 ;
        RECT 175.260 0.500 175.380 345.100 ;
        RECT 180.660 0.500 180.780 345.100 ;
        RECT 186.060 0.500 186.180 345.100 ;
        RECT 191.460 0.500 191.580 345.100 ;
        RECT 196.860 0.500 196.980 345.100 ;
        RECT 202.260 0.500 202.380 345.100 ;
        RECT 207.660 0.500 207.780 345.100 ;
        RECT 213.060 0.500 213.180 345.100 ;
        RECT 218.460 0.500 218.580 345.100 ;
        RECT 223.860 0.500 223.980 345.100 ;
        RECT 229.260 0.500 229.380 345.100 ;
        RECT 234.660 0.500 234.780 345.100 ;
        RECT 240.060 0.500 240.180 345.100 ;
        RECT 245.460 0.500 245.580 345.100 ;
        RECT 250.860 0.500 250.980 345.100 ;
        RECT 256.260 0.500 256.380 345.100 ;
        RECT 261.660 0.500 261.780 345.100 ;
        RECT 267.060 0.500 267.180 345.100 ;
        RECT 272.460 0.500 272.580 345.100 ;
        RECT 277.860 0.500 277.980 345.100 ;
        RECT 283.260 0.500 283.380 345.100 ;
        RECT 288.660 0.500 288.780 345.100 ;
        RECT 294.060 0.500 294.180 345.100 ;
        RECT 299.460 0.500 299.580 345.100 ;
        RECT 304.860 0.500 304.980 345.100 ;
        RECT 310.260 0.500 310.380 345.100 ;
        RECT 315.660 0.500 315.780 345.100 ;
        RECT 321.060 0.500 321.180 345.100 ;
        RECT 326.460 0.500 326.580 345.100 ;
        RECT 331.860 0.500 331.980 345.100 ;
        RECT 337.260 0.500 337.380 345.100 ;
        RECT 342.660 0.500 342.780 345.100 ;
    END
  END VDD
  PIN VSS
    DIRECTION INOUT ;
    USE GROUND ;
    PORT
      LAYER M5 ;
        RECT 2.652 0.500 2.772 345.100 ;
        RECT 8.052 0.500 8.172 345.100 ;
        RECT 13.452 0.500 13.572 345.100 ;
        RECT 18.852 0.500 18.972 345.100 ;
        RECT 24.252 0.500 24.372 345.100 ;
        RECT 29.652 0.500 29.772 345.100 ;
        RECT 35.052 0.500 35.172 345.100 ;
        RECT 40.452 0.500 40.572 345.100 ;
        RECT 45.852 0.500 45.972 345.100 ;
        RECT 51.252 0.500 51.372 345.100 ;
        RECT 56.652 0.500 56.772 345.100 ;
        RECT 62.052 0.500 62.172 345.100 ;
        RECT 67.452 0.500 67.572 345.100 ;
        RECT 72.852 0.500 72.972 345.100 ;
        RECT 78.252 0.500 78.372 345.100 ;
        RECT 83.652 0.500 83.772 345.100 ;
        RECT 89.052 0.500 89.172 345.100 ;
        RECT 94.452 0.500 94.572 345.100 ;
        RECT 99.852 0.500 99.972 345.100 ;
        RECT 105.252 0.500 105.372 345.100 ;
        RECT 110.652 0.500 110.772 345.100 ;
        RECT 116.052 0.500 116.172 345.100 ;
        RECT 121.452 0.500 121.572 345.100 ;
        RECT 126.852 0.500 126.972 345.100 ;
        RECT 132.252 0.500 132.372 345.100 ;
        RECT 137.652 0.500 137.772 345.100 ;
        RECT 143.052 0.500 143.172 345.100 ;
        RECT 148.452 0.500 148.572 345.100 ;
        RECT 153.852 0.500 153.972 345.100 ;
        RECT 159.252 0.500 159.372 345.100 ;
        RECT 164.652 0.500 164.772 345.100 ;
        RECT 170.052 0.500 170.172 345.100 ;
        RECT 175.452 0.500 175.572 345.100 ;
        RECT 180.852 0.500 180.972 345.100 ;
        RECT 186.252 0.500 186.372 345.100 ;
        RECT 191.652 0.500 191.772 345.100 ;
        RECT 197.052 0.500 197.172 345.100 ;
        RECT 202.452 0.500 202.572 345.100 ;
        RECT 207.852 0.500 207.972 345.100 ;
        RECT 213.252 0.500 213.372 345.100 ;
        RECT 218.652 0.500 218.772 345.100 ;
        RECT 224.052 0.500 224.172 345.100 ;
        RECT 229.452 0.500 229.572 345.100 ;
        RECT 234.852 0.500 234.972 345.100 ;
        RECT 240.252 0.500 240.372 345.100 ;
        RECT 245.652 0.500 245.772 345.100 ;
        RECT 251.052 0.500 251.172 345.100 ;
        RECT 256.452 0.500 256.572 345.100 ;
        RECT 261.852 0.500 261.972 345.100 ;
        RECT 267.252 0.500 267.372 345.100 ;
        RECT 272.652 0.500 272.772 345.100 ;
        RECT 278.052 0.500 278.172 345.100 ;
        RECT 283.452 0.500 283.572 345.100 ;
        RECT 288.852 0.500 288.972 345.100 ;
        RECT 294.252 0.500 294.372 345.100 ;
        RECT 299.652 0.500 299.772 345.100 ;
        RECT 305.052 0.500 305.172 345.100 ;
        RECT 310.452 0.500 310.572 345.100 ;
        RECT 315.852 0.500 315.972 345.100 ;
        RECT 321.252 0.500 321.372 345.100 ;
        RECT 326.652 0.500 326.772 345.100 ;
        RECT 332.052 0.500 332.172 345.100 ;
        RECT 337.452 0.500 337.572 345.100 ;
        RECT 342.852 0.500 342.972 345.100 ;
    END
  END VSS
  OBS
    LAYER M1 ;
      RECT 0.500 0.500 345.100 345.100 ;
    LAYER M2 ;
      RECT 0.500 0.500 345.100 345.100 ;
    LAYER M3 ;
      RECT 0.500 297.816 10.800 345.100 ;
      RECT 10.800 0.500 76.656 345.100 ;
      RECT 76.656 10.800 98.280 345.100 ;
      RECT 98.280 0.500 136.077 345.100 ;
      RECT 136.077 10.800 157.701 345.100 ;
      RECT 157.701 0.500 247.296 345.100 ;
      RECT 247.296 10.800 268.920 345.100 ;
      RECT 268.920 0.500 334.800 345.100 ;
      RECT 334.800 297.912 345.100 345.100 ;
    LAYER M4 ;
      RECT 0.500 297.816 10.800 345.100 ;
      RECT 10.800 0.500 76.656 345.100 ;
      RECT 76.656 10.800 98.280 345.100 ;
      RECT 98.280 0.500 136.077 345.100 ;
      RECT 136.077 10.800 157.701 345.100 ;
      RECT 157.701 0.500 247.296 345.100 ;
      RECT 247.296 10.800 268.920 345.100 ;
      RECT 268.920 0.500 334.800 345.100 ;
      RECT 334.800 297.912 345.100 345.100 ;
    LAYER M5 ;
      RECT 0.500 297.816 2.460 344.700 ;
      RECT 2.580 297.816 2.652 344.700 ;
      RECT 2.772 297.816 7.860 344.700 ;
      RECT 7.980 297.816 8.052 344.700 ;
      RECT 8.172 297.816 10.800 344.700 ;
      RECT 10.800 0.900 13.260 344.700 ;
      RECT 13.380 0.900 13.452 344.700 ;
      RECT 13.572 0.900 18.660 344.700 ;
      RECT 18.780 0.900 18.852 344.700 ;
      RECT 18.972 0.900 24.060 344.700 ;
      RECT 24.180 0.900 24.252 344.700 ;
      RECT 24.372 0.900 29.460 344.700 ;
      RECT 29.580 0.900 29.652 344.700 ;
      RECT 29.772 0.900 34.860 344.700 ;
      RECT 34.980 0.900 35.052 344.700 ;
      RECT 35.172 0.900 40.260 344.700 ;
      RECT 40.380 0.900 40.452 344.700 ;
      RECT 40.572 0.900 45.660 344.700 ;
      RECT 45.780 0.900 45.852 344.700 ;
      RECT 45.972 0.900 51.060 344.700 ;
      RECT 51.180 0.900 51.252 344.700 ;
      RECT 51.372 0.900 56.460 344.700 ;
      RECT 56.580 0.900 56.652 344.700 ;
      RECT 56.772 0.900 61.860 344.700 ;
      RECT 61.980 0.900 62.052 344.700 ;
      RECT 62.172 0.900 67.260 344.700 ;
      RECT 67.380 0.900 67.452 344.700 ;
      RECT 67.572 0.900 72.660 344.700 ;
      RECT 72.780 0.900 72.852 344.700 ;
      RECT 72.972 0.900 76.656 344.700 ;
      RECT 76.656 10.800 78.060 344.700 ;
      RECT 78.180 10.800 78.252 344.700 ;
      RECT 78.372 10.800 83.460 344.700 ;
      RECT 83.580 10.800 83.652 344.700 ;
      RECT 83.772 10.800 88.860 344.700 ;
      RECT 88.980 10.800 89.052 344.700 ;
      RECT 89.172 10.800 94.260 344.700 ;
      RECT 94.380 10.800 94.452 344.700 ;
      RECT 94.572 10.800 98.280 344.700 ;
      RECT 98.280 0.900 99.660 344.700 ;
      RECT 99.780 0.900 99.852 344.700 ;
      RECT 99.972 0.900 105.060 344.700 ;
      RECT 105.180 0.900 105.252 344.700 ;
      RECT 105.372 0.900 110.460 344.700 ;
      RECT 110.580 0.900 110.652 344.700 ;
      RECT 110.772 0.900 115.860 344.700 ;
      RECT 115.980 0.900 116.052 344.700 ;
      RECT 116.172 0.900 121.260 344.700 ;
      RECT 121.380 0.900 121.452 344.700 ;
      RECT 121.572 0.900 126.660 344.700 ;
      RECT 126.780 0.900 126.852 344.700 ;
      RECT 126.972 0.900 132.060 344.700 ;
      RECT 132.180 0.900 132.252 344.700 ;
      RECT 132.372 0.900 136.077 344.700 ;
      RECT 136.077 10.800 137.460 344.700 ;
      RECT 137.580 10.800 137.652 344.700 ;
      RECT 137.772 10.800 142.860 344.700 ;
      RECT 142.980 10.800 143.052 344.700 ;
      RECT 143.172 10.800 148.260 344.700 ;
      RECT 148.380 10.800 148.452 344.700 ;
      RECT 148.572 10.800 153.660 344.700 ;
      RECT 153.780 10.800 153.852 344.700 ;
      RECT 153.972 10.800 157.701 344.700 ;
      RECT 157.701 0.900 159.060 344.700 ;
      RECT 159.180 0.900 159.252 344.700 ;
      RECT 159.372 0.900 164.460 344.700 ;
      RECT 164.580 0.900 164.652 344.700 ;
      RECT 164.772 0.900 169.860 344.700 ;
      RECT 169.980 0.900 170.052 344.700 ;
      RECT 170.172 0.900 175.260 344.700 ;
      RECT 175.380 0.900 175.452 344.700 ;
      RECT 175.572 0.900 180.660 344.700 ;
      RECT 180.780 0.900 180.852 344.700 ;
      RECT 180.972 0.900 186.060 344.700 ;
      RECT 186.180 0.900 186.252 344.700 ;
      RECT 186.372 0.900 191.460 344.700 ;
      RECT 191.580 0.900 191.652 344.700 ;
      RECT 191.772 0.900 196.860 344.700 ;
      RECT 196.980 0.900 197.052 344.700 ;
      RECT 197.172 0.900 202.260 344.700 ;
      RECT 202.380 0.900 202.452 344.700 ;
      RECT 202.572 0.900 207.660 344.700 ;
      RECT 207.780 0.900 207.852 344.700 ;
      RECT 207.972 0.900 213.060 344.700 ;
      RECT 213.180 0.900 213.252 344.700 ;
      RECT 213.372 0.900 218.460 344.700 ;
      RECT 218.580 0.900 218.652 344.700 ;
      RECT 218.772 0.900 223.860 344.700 ;
      RECT 223.980 0.900 224.052 344.700 ;
      RECT 224.172 0.900 229.260 344.700 ;
      RECT 229.380 0.900 229.452 344.700 ;
      RECT 229.572 0.900 234.660 344.700 ;
      RECT 234.780 0.900 234.852 344.700 ;
      RECT 234.972 0.900 240.060 344.700 ;
      RECT 240.180 0.900 240.252 344.700 ;
      RECT 240.372 0.900 245.460 344.700 ;
      RECT 245.580 0.900 245.652 344.700 ;
      RECT 245.772 0.900 247.296 344.700 ;
      RECT 247.296 10.800 250.860 344.700 ;
      RECT 250.980 10.800 251.052 344.700 ;
      RECT 251.172 10.800 256.260 344.700 ;
      RECT 256.380 10.800 256.452 344.700 ;
      RECT 256.572 10.800 261.660 344.700 ;
      RECT 261.780 10.800 261.852 344.700 ;
      RECT 261.972 10.800 267.060 344.700 ;
      RECT 267.180 10.800 267.252 344.700 ;
      RECT 267.372 10.800 268.920 344.700 ;
      RECT 268.920 0.900 272.460 344.700 ;
      RECT 272.580 0.900 272.652 344.700 ;
      RECT 272.772 0.900 277.860 344.700 ;
      RECT 277.980 0.900 278.052 344.700 ;
      RECT 278.172 0.900 283.260 344.700 ;
      RECT 283.380 0.900 283.452 344.700 ;
      RECT 283.572 0.900 288.660 344.700 ;
      RECT 288.780 0.900 288.852 344.700 ;
      RECT 288.972 0.900 294.060 344.700 ;
      RECT 294.180 0.900 294.252 344.700 ;
      RECT 294.372 0.900 299.460 344.700 ;
      RECT 299.580 0.900 299.652 344.700 ;
      RECT 299.772 0.900 304.860 344.700 ;
      RECT 304.980 0.900 305.052 344.700 ;
      RECT 305.172 0.900 310.260 344.700 ;
      RECT 310.380 0.900 310.452 344.700 ;
      RECT 310.572 0.900 315.660 344.700 ;
      RECT 315.780 0.900 315.852 344.700 ;
      RECT 315.972 0.900 321.060 344.700 ;
      RECT 321.180 0.900 321.252 344.700 ;
      RECT 321.372 0.900 326.460 344.700 ;
      RECT 326.580 0.900 326.652 344.700 ;
      RECT 326.772 0.900 331.860 344.700 ;
      RECT 331.980 0.900 332.052 344.700 ;
      RECT 332.172 0.900 334.800 344.700 ;
      RECT 334.800 297.912 337.260 344.700 ;
      RECT 337.380 297.912 337.452 344.700 ;
      RECT 337.572 297.912 342.660 344.700 ;
      RECT 342.780 297.912 342.852 344.700 ;
      RECT 342.972 297.912 345.100 344.700 ;
  END
END ot_s81sl_ve
END LIBRARY
